VERSION 5.8 ;
BUSBITCHARS "[]" ;
DIVIDERCHAR "/" ;
UNITS
    DATABASE MICRONS 1000 ;
END UNITS

VIA ino_fetch_via1_2_1000_440_1_2_410_410
  VIARULE via1Array ;
  CUTSIZE 0.19 0.19 ;
  LAYERS Metal1 Via1 Metal2 ;
  CUTSPACING 0.22 0.22 ;
  ENCLOSURE 0.05 0.125 0.005 0.05 ;
  ROWCOL 1 2 ;
END ino_fetch_via1_2_1000_440_1_2_410_410

VIA ino_fetch_via2_3_1000_440_1_2_410_410
  VIARULE via2Array ;
  CUTSIZE 0.19 0.19 ;
  LAYERS Metal2 Via2 Metal3 ;
  CUTSPACING 0.22 0.22 ;
  ENCLOSURE 0.005 0.05 0.05 0.005 ;
  ROWCOL 1 2 ;
END ino_fetch_via2_3_1000_440_1_2_410_410

VIA ino_fetch_via3_4_1000_440_1_2_410_410
  VIARULE via3Array ;
  CUTSIZE 0.19 0.19 ;
  LAYERS Metal3 Via3 Metal4 ;
  CUTSPACING 0.22 0.22 ;
  ENCLOSURE 0.05 0.005 0.2 0.05 ;
  ROWCOL 1 2 ;
END ino_fetch_via3_4_1000_440_1_2_410_410

VIA ino_fetch_via4_5_1000_2000_1_1_840_840
  VIARULE viaTop1Array ;
  CUTSIZE 0.42 0.42 ;
  LAYERS Metal4 TopVia1 TopMetal1 ;
  CUTSPACING 0.42 0.42 ;
  ENCLOSURE 0.29 0.1 0.42 0.79 ;
END ino_fetch_via4_5_1000_2000_1_1_840_840

VIA ino_fetch_via4_5_1000_1640_1_1_840_840
  VIARULE viaTop1Array ;
  CUTSIZE 0.42 0.42 ;
  LAYERS Metal4 TopVia1 TopMetal1 ;
  CUTSPACING 0.42 0.42 ;
  ENCLOSURE 0.29 0.1 0.42 0.61 ;
END ino_fetch_via4_5_1000_1640_1_1_840_840

VIA ino_fetch_via4_5_1000_1400_1_1_840_840
  VIARULE viaTop1Array ;
  CUTSIZE 0.42 0.42 ;
  LAYERS Metal4 TopVia1 TopMetal1 ;
  CUTSPACING 0.42 0.42 ;
  ENCLOSURE 0.29 0.1 0.42 0.49 ;
END ino_fetch_via4_5_1000_1400_1_1_840_840

VIA ino_fetch_via4_5_4420_2000_1_4_840_840
  VIARULE viaTop1Array ;
  CUTSIZE 0.42 0.42 ;
  LAYERS Metal4 TopVia1 TopMetal1 ;
  CUTSPACING 0.42 0.42 ;
  ENCLOSURE 0.74 0.79 0.42 0.79 ;
  ROWCOL 1 4 ;
END ino_fetch_via4_5_4420_2000_1_4_840_840

VIA ino_fetch_via4_5_2810_2000_1_2_840_840
  VIARULE viaTop1Array ;
  CUTSIZE 0.42 0.42 ;
  LAYERS Metal4 TopVia1 TopMetal1 ;
  CUTSPACING 0.42 0.42 ;
  ENCLOSURE 0.775 0.79 0.42 0.79 ;
  ROWCOL 1 2 ;
END ino_fetch_via4_5_2810_2000_1_2_840_840

VIA ino_fetch_via4_5_4420_1650_1_4_840_840
  VIARULE viaTop1Array ;
  CUTSIZE 0.42 0.42 ;
  LAYERS Metal4 TopVia1 TopMetal1 ;
  CUTSPACING 0.42 0.42 ;
  ENCLOSURE 0.74 0.615 0.42 0.615 ;
  ROWCOL 1 4 ;
END ino_fetch_via4_5_4420_1650_1_4_840_840

VIA ino_fetch_via4_5_2810_1650_1_2_840_840
  VIARULE viaTop1Array ;
  CUTSIZE 0.42 0.42 ;
  LAYERS Metal4 TopVia1 TopMetal1 ;
  CUTSPACING 0.42 0.42 ;
  ENCLOSURE 0.775 0.615 0.42 0.615 ;
  ROWCOL 1 2 ;
END ino_fetch_via4_5_2810_1650_1_2_840_840

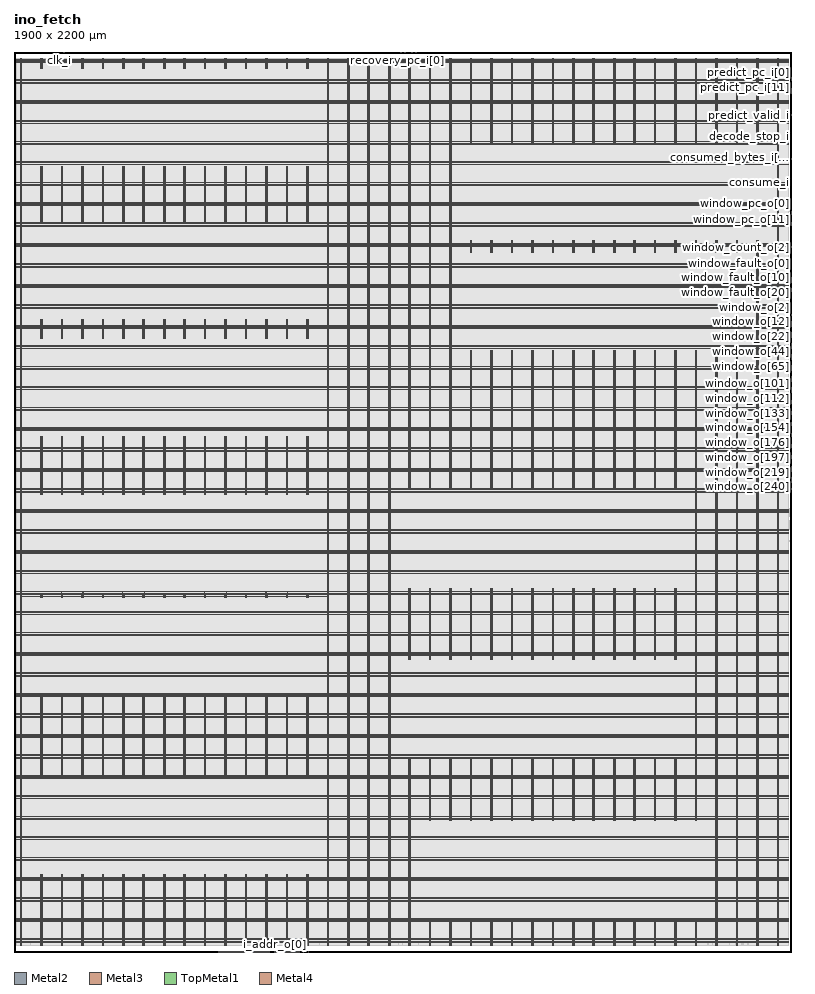
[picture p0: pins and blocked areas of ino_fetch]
MACRO ino_fetch
  FOREIGN ino_fetch 0 0 ;
  CLASS BLOCK ;
  SIZE 1900 BY 2200 ;
  PIN clk_i
    DIRECTION INPUT ;
    USE SIGNAL ;
    PORT
      LAYER Metal2 ;
        RECT  110.68 2199.6 111.08 2200 ;
    END
  END clk_i
  PIN consume_i
    DIRECTION INPUT ;
    USE SIGNAL ;
    PORT
      LAYER Metal3 ;
        RECT  1899.6 1880.98 1900 1881.38 ;
    END
  END consume_i
  PIN consumed_bytes_i[0]
    DIRECTION INPUT ;
    USE SIGNAL ;
    PORT
      LAYER Metal3 ;
        RECT  1899.6 1941.46 1900 1941.86 ;
    END
  END consumed_bytes_i[0]
  PIN consumed_bytes_i[1]
    DIRECTION INPUT ;
    USE SIGNAL ;
    PORT
      LAYER Metal3 ;
        RECT  1899.6 1939.78 1900 1940.18 ;
    END
  END consumed_bytes_i[1]
  PIN consumed_bytes_i[2]
    DIRECTION INPUT ;
    USE SIGNAL ;
    PORT
      LAYER Metal3 ;
        RECT  1899.6 1938.1 1900 1938.5 ;
    END
  END consumed_bytes_i[2]
  PIN consumed_bytes_i[3]
    DIRECTION INPUT ;
    USE SIGNAL ;
    PORT
      LAYER Metal3 ;
        RECT  1899.6 1936.42 1900 1936.82 ;
    END
  END consumed_bytes_i[3]
  PIN consumed_bytes_i[4]
    DIRECTION INPUT ;
    USE SIGNAL ;
    PORT
      LAYER Metal3 ;
        RECT  1899.6 1934.74 1900 1935.14 ;
    END
  END consumed_bytes_i[4]
  PIN consumed_bytes_i[5]
    DIRECTION INPUT ;
    USE SIGNAL ;
    PORT
      LAYER Metal3 ;
        RECT  1899.6 1933.06 1900 1933.46 ;
    END
  END consumed_bytes_i[5]
  PIN decode_stop_i
    DIRECTION INPUT ;
    USE SIGNAL ;
    PORT
      LAYER Metal3 ;
        RECT  1899.6 1993.54 1900 1993.94 ;
    END
  END decode_stop_i
  PIN halt_i
    DIRECTION INPUT ;
    USE SIGNAL ;
    PORT
      LAYER Metal2 ;
        RECT  122.2 2199.6 122.6 2200 ;
    END
  END halt_i
  PIN i_addr_o[0]
    DIRECTION OUTPUT ;
    USE SIGNAL ;
    PORT
      LAYER Metal2 ;
        RECT  636.76 0 637.16 0.4 ;
    END
  END i_addr_o[0]
  PIN i_addr_o[10]
    DIRECTION OUTPUT ;
    USE SIGNAL ;
    PORT
      LAYER Metal2 ;
        RECT  655.96 0 656.36 0.4 ;
    END
  END i_addr_o[10]
  PIN i_addr_o[11]
    DIRECTION OUTPUT ;
    USE SIGNAL ;
    PORT
      LAYER Metal2 ;
        RECT  657.88 0 658.28 0.4 ;
    END
  END i_addr_o[11]
  PIN i_addr_o[12]
    DIRECTION OUTPUT ;
    USE SIGNAL ;
    PORT
      LAYER Metal2 ;
        RECT  659.8 0 660.2 0.4 ;
    END
  END i_addr_o[12]
  PIN i_addr_o[13]
    DIRECTION OUTPUT ;
    USE SIGNAL ;
    PORT
      LAYER Metal2 ;
        RECT  661.72 0 662.12 0.4 ;
    END
  END i_addr_o[13]
  PIN i_addr_o[14]
    DIRECTION OUTPUT ;
    USE SIGNAL ;
    PORT
      LAYER Metal2 ;
        RECT  663.64 0 664.04 0.4 ;
    END
  END i_addr_o[14]
  PIN i_addr_o[15]
    DIRECTION OUTPUT ;
    USE SIGNAL ;
    PORT
      LAYER Metal2 ;
        RECT  665.56 0 665.96 0.4 ;
    END
  END i_addr_o[15]
  PIN i_addr_o[16]
    DIRECTION OUTPUT ;
    USE SIGNAL ;
    PORT
      LAYER Metal2 ;
        RECT  667.48 0 667.88 0.4 ;
    END
  END i_addr_o[16]
  PIN i_addr_o[17]
    DIRECTION OUTPUT ;
    USE SIGNAL ;
    PORT
      LAYER Metal2 ;
        RECT  669.4 0 669.8 0.4 ;
    END
  END i_addr_o[17]
  PIN i_addr_o[18]
    DIRECTION OUTPUT ;
    USE SIGNAL ;
    PORT
      LAYER Metal2 ;
        RECT  671.32 0 671.72 0.4 ;
    END
  END i_addr_o[18]
  PIN i_addr_o[19]
    DIRECTION OUTPUT ;
    USE SIGNAL ;
    PORT
      LAYER Metal2 ;
        RECT  673.24 0 673.64 0.4 ;
    END
  END i_addr_o[19]
  PIN i_addr_o[1]
    DIRECTION OUTPUT ;
    USE SIGNAL ;
    PORT
      LAYER Metal2 ;
        RECT  638.68 0 639.08 0.4 ;
    END
  END i_addr_o[1]
  PIN i_addr_o[20]
    DIRECTION OUTPUT ;
    USE SIGNAL ;
    PORT
      LAYER Metal2 ;
        RECT  675.16 0 675.56 0.4 ;
    END
  END i_addr_o[20]
  PIN i_addr_o[21]
    DIRECTION OUTPUT ;
    USE SIGNAL ;
    PORT
      LAYER Metal2 ;
        RECT  677.08 0 677.48 0.4 ;
    END
  END i_addr_o[21]
  PIN i_addr_o[22]
    DIRECTION OUTPUT ;
    USE SIGNAL ;
    PORT
      LAYER Metal2 ;
        RECT  679 0 679.4 0.4 ;
    END
  END i_addr_o[22]
  PIN i_addr_o[23]
    DIRECTION OUTPUT ;
    USE SIGNAL ;
    PORT
      LAYER Metal2 ;
        RECT  680.92 0 681.32 0.4 ;
    END
  END i_addr_o[23]
  PIN i_addr_o[24]
    DIRECTION OUTPUT ;
    USE SIGNAL ;
    PORT
      LAYER Metal2 ;
        RECT  682.84 0 683.24 0.4 ;
    END
  END i_addr_o[24]
  PIN i_addr_o[25]
    DIRECTION OUTPUT ;
    USE SIGNAL ;
    PORT
      LAYER Metal2 ;
        RECT  684.76 0 685.16 0.4 ;
    END
  END i_addr_o[25]
  PIN i_addr_o[26]
    DIRECTION OUTPUT ;
    USE SIGNAL ;
    PORT
      LAYER Metal2 ;
        RECT  686.68 0 687.08 0.4 ;
    END
  END i_addr_o[26]
  PIN i_addr_o[27]
    DIRECTION OUTPUT ;
    USE SIGNAL ;
    PORT
      LAYER Metal2 ;
        RECT  688.6 0 689 0.4 ;
    END
  END i_addr_o[27]
  PIN i_addr_o[28]
    DIRECTION OUTPUT ;
    USE SIGNAL ;
    PORT
      LAYER Metal2 ;
        RECT  690.52 0 690.92 0.4 ;
    END
  END i_addr_o[28]
  PIN i_addr_o[29]
    DIRECTION OUTPUT ;
    USE SIGNAL ;
    PORT
      LAYER Metal2 ;
        RECT  692.44 0 692.84 0.4 ;
    END
  END i_addr_o[29]
  PIN i_addr_o[2]
    DIRECTION OUTPUT ;
    USE SIGNAL ;
    PORT
      LAYER Metal2 ;
        RECT  640.6 0 641 0.4 ;
    END
  END i_addr_o[2]
  PIN i_addr_o[30]
    DIRECTION OUTPUT ;
    USE SIGNAL ;
    PORT
      LAYER Metal2 ;
        RECT  694.36 0 694.76 0.4 ;
    END
  END i_addr_o[30]
  PIN i_addr_o[31]
    DIRECTION OUTPUT ;
    USE SIGNAL ;
    PORT
      LAYER Metal2 ;
        RECT  696.28 0 696.68 0.4 ;
    END
  END i_addr_o[31]
  PIN i_addr_o[3]
    DIRECTION OUTPUT ;
    USE SIGNAL ;
    PORT
      LAYER Metal2 ;
        RECT  642.52 0 642.92 0.4 ;
    END
  END i_addr_o[3]
  PIN i_addr_o[4]
    DIRECTION OUTPUT ;
    USE SIGNAL ;
    PORT
      LAYER Metal2 ;
        RECT  644.44 0 644.84 0.4 ;
    END
  END i_addr_o[4]
  PIN i_addr_o[5]
    DIRECTION OUTPUT ;
    USE SIGNAL ;
    PORT
      LAYER Metal2 ;
        RECT  646.36 0 646.76 0.4 ;
    END
  END i_addr_o[5]
  PIN i_addr_o[6]
    DIRECTION OUTPUT ;
    USE SIGNAL ;
    PORT
      LAYER Metal2 ;
        RECT  648.28 0 648.68 0.4 ;
    END
  END i_addr_o[6]
  PIN i_addr_o[7]
    DIRECTION OUTPUT ;
    USE SIGNAL ;
    PORT
      LAYER Metal2 ;
        RECT  650.2 0 650.6 0.4 ;
    END
  END i_addr_o[7]
  PIN i_addr_o[8]
    DIRECTION OUTPUT ;
    USE SIGNAL ;
    PORT
      LAYER Metal2 ;
        RECT  652.12 0 652.52 0.4 ;
    END
  END i_addr_o[8]
  PIN i_addr_o[9]
    DIRECTION OUTPUT ;
    USE SIGNAL ;
    PORT
      LAYER Metal2 ;
        RECT  654.04 0 654.44 0.4 ;
    END
  END i_addr_o[9]
  PIN i_fault_i
    DIRECTION INPUT ;
    USE SIGNAL ;
    PORT
      LAYER Metal2 ;
        RECT  719.32 0 719.72 0.4 ;
    END
  END i_fault_i
  PIN i_rdata_i[0]
    DIRECTION INPUT ;
    USE SIGNAL ;
    PORT
      LAYER Metal2 ;
        RECT  500.44 0 500.84 0.4 ;
    END
  END i_rdata_i[0]
  PIN i_rdata_i[10]
    DIRECTION INPUT ;
    USE SIGNAL ;
    PORT
      LAYER Metal2 ;
        RECT  519.64 0 520.04 0.4 ;
    END
  END i_rdata_i[10]
  PIN i_rdata_i[11]
    DIRECTION INPUT ;
    USE SIGNAL ;
    PORT
      LAYER Metal2 ;
        RECT  521.56 0 521.96 0.4 ;
    END
  END i_rdata_i[11]
  PIN i_rdata_i[12]
    DIRECTION INPUT ;
    USE SIGNAL ;
    PORT
      LAYER Metal2 ;
        RECT  523.48 0 523.88 0.4 ;
    END
  END i_rdata_i[12]
  PIN i_rdata_i[13]
    DIRECTION INPUT ;
    USE SIGNAL ;
    PORT
      LAYER Metal2 ;
        RECT  525.4 0 525.8 0.4 ;
    END
  END i_rdata_i[13]
  PIN i_rdata_i[14]
    DIRECTION INPUT ;
    USE SIGNAL ;
    PORT
      LAYER Metal2 ;
        RECT  527.32 0 527.72 0.4 ;
    END
  END i_rdata_i[14]
  PIN i_rdata_i[15]
    DIRECTION INPUT ;
    USE SIGNAL ;
    PORT
      LAYER Metal2 ;
        RECT  529.24 0 529.64 0.4 ;
    END
  END i_rdata_i[15]
  PIN i_rdata_i[16]
    DIRECTION INPUT ;
    USE SIGNAL ;
    PORT
      LAYER Metal2 ;
        RECT  531.16 0 531.56 0.4 ;
    END
  END i_rdata_i[16]
  PIN i_rdata_i[17]
    DIRECTION INPUT ;
    USE SIGNAL ;
    PORT
      LAYER Metal2 ;
        RECT  533.08 0 533.48 0.4 ;
    END
  END i_rdata_i[17]
  PIN i_rdata_i[18]
    DIRECTION INPUT ;
    USE SIGNAL ;
    PORT
      LAYER Metal2 ;
        RECT  535 0 535.4 0.4 ;
    END
  END i_rdata_i[18]
  PIN i_rdata_i[19]
    DIRECTION INPUT ;
    USE SIGNAL ;
    PORT
      LAYER Metal2 ;
        RECT  536.92 0 537.32 0.4 ;
    END
  END i_rdata_i[19]
  PIN i_rdata_i[1]
    DIRECTION INPUT ;
    USE SIGNAL ;
    PORT
      LAYER Metal2 ;
        RECT  502.36 0 502.76 0.4 ;
    END
  END i_rdata_i[1]
  PIN i_rdata_i[20]
    DIRECTION INPUT ;
    USE SIGNAL ;
    PORT
      LAYER Metal2 ;
        RECT  538.84 0 539.24 0.4 ;
    END
  END i_rdata_i[20]
  PIN i_rdata_i[21]
    DIRECTION INPUT ;
    USE SIGNAL ;
    PORT
      LAYER Metal2 ;
        RECT  540.76 0 541.16 0.4 ;
    END
  END i_rdata_i[21]
  PIN i_rdata_i[22]
    DIRECTION INPUT ;
    USE SIGNAL ;
    PORT
      LAYER Metal2 ;
        RECT  542.68 0 543.08 0.4 ;
    END
  END i_rdata_i[22]
  PIN i_rdata_i[23]
    DIRECTION INPUT ;
    USE SIGNAL ;
    PORT
      LAYER Metal2 ;
        RECT  544.6 0 545 0.4 ;
    END
  END i_rdata_i[23]
  PIN i_rdata_i[24]
    DIRECTION INPUT ;
    USE SIGNAL ;
    PORT
      LAYER Metal2 ;
        RECT  546.52 0 546.92 0.4 ;
    END
  END i_rdata_i[24]
  PIN i_rdata_i[25]
    DIRECTION INPUT ;
    USE SIGNAL ;
    PORT
      LAYER Metal2 ;
        RECT  548.44 0 548.84 0.4 ;
    END
  END i_rdata_i[25]
  PIN i_rdata_i[26]
    DIRECTION INPUT ;
    USE SIGNAL ;
    PORT
      LAYER Metal2 ;
        RECT  550.36 0 550.76 0.4 ;
    END
  END i_rdata_i[26]
  PIN i_rdata_i[27]
    DIRECTION INPUT ;
    USE SIGNAL ;
    PORT
      LAYER Metal2 ;
        RECT  552.28 0 552.68 0.4 ;
    END
  END i_rdata_i[27]
  PIN i_rdata_i[28]
    DIRECTION INPUT ;
    USE SIGNAL ;
    PORT
      LAYER Metal2 ;
        RECT  554.2 0 554.6 0.4 ;
    END
  END i_rdata_i[28]
  PIN i_rdata_i[29]
    DIRECTION INPUT ;
    USE SIGNAL ;
    PORT
      LAYER Metal2 ;
        RECT  556.12 0 556.52 0.4 ;
    END
  END i_rdata_i[29]
  PIN i_rdata_i[2]
    DIRECTION INPUT ;
    USE SIGNAL ;
    PORT
      LAYER Metal2 ;
        RECT  504.28 0 504.68 0.4 ;
    END
  END i_rdata_i[2]
  PIN i_rdata_i[30]
    DIRECTION INPUT ;
    USE SIGNAL ;
    PORT
      LAYER Metal2 ;
        RECT  558.04 0 558.44 0.4 ;
    END
  END i_rdata_i[30]
  PIN i_rdata_i[31]
    DIRECTION INPUT ;
    USE SIGNAL ;
    PORT
      LAYER Metal2 ;
        RECT  559.96 0 560.36 0.4 ;
    END
  END i_rdata_i[31]
  PIN i_rdata_i[32]
    DIRECTION INPUT ;
    USE SIGNAL ;
    PORT
      LAYER Metal2 ;
        RECT  561.88 0 562.28 0.4 ;
    END
  END i_rdata_i[32]
  PIN i_rdata_i[33]
    DIRECTION INPUT ;
    USE SIGNAL ;
    PORT
      LAYER Metal2 ;
        RECT  563.8 0 564.2 0.4 ;
    END
  END i_rdata_i[33]
  PIN i_rdata_i[34]
    DIRECTION INPUT ;
    USE SIGNAL ;
    PORT
      LAYER Metal2 ;
        RECT  565.72 0 566.12 0.4 ;
    END
  END i_rdata_i[34]
  PIN i_rdata_i[35]
    DIRECTION INPUT ;
    USE SIGNAL ;
    PORT
      LAYER Metal2 ;
        RECT  567.64 0 568.04 0.4 ;
    END
  END i_rdata_i[35]
  PIN i_rdata_i[36]
    DIRECTION INPUT ;
    USE SIGNAL ;
    PORT
      LAYER Metal2 ;
        RECT  569.56 0 569.96 0.4 ;
    END
  END i_rdata_i[36]
  PIN i_rdata_i[37]
    DIRECTION INPUT ;
    USE SIGNAL ;
    PORT
      LAYER Metal2 ;
        RECT  571.48 0 571.88 0.4 ;
    END
  END i_rdata_i[37]
  PIN i_rdata_i[38]
    DIRECTION INPUT ;
    USE SIGNAL ;
    PORT
      LAYER Metal2 ;
        RECT  573.4 0 573.8 0.4 ;
    END
  END i_rdata_i[38]
  PIN i_rdata_i[39]
    DIRECTION INPUT ;
    USE SIGNAL ;
    PORT
      LAYER Metal2 ;
        RECT  575.32 0 575.72 0.4 ;
    END
  END i_rdata_i[39]
  PIN i_rdata_i[3]
    DIRECTION INPUT ;
    USE SIGNAL ;
    PORT
      LAYER Metal2 ;
        RECT  506.2 0 506.6 0.4 ;
    END
  END i_rdata_i[3]
  PIN i_rdata_i[40]
    DIRECTION INPUT ;
    USE SIGNAL ;
    PORT
      LAYER Metal2 ;
        RECT  577.24 0 577.64 0.4 ;
    END
  END i_rdata_i[40]
  PIN i_rdata_i[41]
    DIRECTION INPUT ;
    USE SIGNAL ;
    PORT
      LAYER Metal2 ;
        RECT  579.16 0 579.56 0.4 ;
    END
  END i_rdata_i[41]
  PIN i_rdata_i[42]
    DIRECTION INPUT ;
    USE SIGNAL ;
    PORT
      LAYER Metal2 ;
        RECT  581.08 0 581.48 0.4 ;
    END
  END i_rdata_i[42]
  PIN i_rdata_i[43]
    DIRECTION INPUT ;
    USE SIGNAL ;
    PORT
      LAYER Metal2 ;
        RECT  583 0 583.4 0.4 ;
    END
  END i_rdata_i[43]
  PIN i_rdata_i[44]
    DIRECTION INPUT ;
    USE SIGNAL ;
    PORT
      LAYER Metal2 ;
        RECT  584.92 0 585.32 0.4 ;
    END
  END i_rdata_i[44]
  PIN i_rdata_i[45]
    DIRECTION INPUT ;
    USE SIGNAL ;
    PORT
      LAYER Metal2 ;
        RECT  586.84 0 587.24 0.4 ;
    END
  END i_rdata_i[45]
  PIN i_rdata_i[46]
    DIRECTION INPUT ;
    USE SIGNAL ;
    PORT
      LAYER Metal2 ;
        RECT  588.76 0 589.16 0.4 ;
    END
  END i_rdata_i[46]
  PIN i_rdata_i[47]
    DIRECTION INPUT ;
    USE SIGNAL ;
    PORT
      LAYER Metal2 ;
        RECT  590.68 0 591.08 0.4 ;
    END
  END i_rdata_i[47]
  PIN i_rdata_i[48]
    DIRECTION INPUT ;
    USE SIGNAL ;
    PORT
      LAYER Metal2 ;
        RECT  592.6 0 593 0.4 ;
    END
  END i_rdata_i[48]
  PIN i_rdata_i[49]
    DIRECTION INPUT ;
    USE SIGNAL ;
    PORT
      LAYER Metal2 ;
        RECT  594.52 0 594.92 0.4 ;
    END
  END i_rdata_i[49]
  PIN i_rdata_i[4]
    DIRECTION INPUT ;
    USE SIGNAL ;
    PORT
      LAYER Metal2 ;
        RECT  508.12 0 508.52 0.4 ;
    END
  END i_rdata_i[4]
  PIN i_rdata_i[50]
    DIRECTION INPUT ;
    USE SIGNAL ;
    PORT
      LAYER Metal2 ;
        RECT  596.44 0 596.84 0.4 ;
    END
  END i_rdata_i[50]
  PIN i_rdata_i[51]
    DIRECTION INPUT ;
    USE SIGNAL ;
    PORT
      LAYER Metal2 ;
        RECT  598.36 0 598.76 0.4 ;
    END
  END i_rdata_i[51]
  PIN i_rdata_i[52]
    DIRECTION INPUT ;
    USE SIGNAL ;
    PORT
      LAYER Metal2 ;
        RECT  600.28 0 600.68 0.4 ;
    END
  END i_rdata_i[52]
  PIN i_rdata_i[53]
    DIRECTION INPUT ;
    USE SIGNAL ;
    PORT
      LAYER Metal2 ;
        RECT  602.2 0 602.6 0.4 ;
    END
  END i_rdata_i[53]
  PIN i_rdata_i[54]
    DIRECTION INPUT ;
    USE SIGNAL ;
    PORT
      LAYER Metal2 ;
        RECT  604.12 0 604.52 0.4 ;
    END
  END i_rdata_i[54]
  PIN i_rdata_i[55]
    DIRECTION INPUT ;
    USE SIGNAL ;
    PORT
      LAYER Metal2 ;
        RECT  606.04 0 606.44 0.4 ;
    END
  END i_rdata_i[55]
  PIN i_rdata_i[56]
    DIRECTION INPUT ;
    USE SIGNAL ;
    PORT
      LAYER Metal2 ;
        RECT  607.96 0 608.36 0.4 ;
    END
  END i_rdata_i[56]
  PIN i_rdata_i[57]
    DIRECTION INPUT ;
    USE SIGNAL ;
    PORT
      LAYER Metal2 ;
        RECT  609.88 0 610.28 0.4 ;
    END
  END i_rdata_i[57]
  PIN i_rdata_i[58]
    DIRECTION INPUT ;
    USE SIGNAL ;
    PORT
      LAYER Metal2 ;
        RECT  611.8 0 612.2 0.4 ;
    END
  END i_rdata_i[58]
  PIN i_rdata_i[59]
    DIRECTION INPUT ;
    USE SIGNAL ;
    PORT
      LAYER Metal2 ;
        RECT  613.72 0 614.12 0.4 ;
    END
  END i_rdata_i[59]
  PIN i_rdata_i[5]
    DIRECTION INPUT ;
    USE SIGNAL ;
    PORT
      LAYER Metal2 ;
        RECT  510.04 0 510.44 0.4 ;
    END
  END i_rdata_i[5]
  PIN i_rdata_i[60]
    DIRECTION INPUT ;
    USE SIGNAL ;
    PORT
      LAYER Metal2 ;
        RECT  615.64 0 616.04 0.4 ;
    END
  END i_rdata_i[60]
  PIN i_rdata_i[61]
    DIRECTION INPUT ;
    USE SIGNAL ;
    PORT
      LAYER Metal2 ;
        RECT  617.56 0 617.96 0.4 ;
    END
  END i_rdata_i[61]
  PIN i_rdata_i[62]
    DIRECTION INPUT ;
    USE SIGNAL ;
    PORT
      LAYER Metal2 ;
        RECT  619.48 0 619.88 0.4 ;
    END
  END i_rdata_i[62]
  PIN i_rdata_i[63]
    DIRECTION INPUT ;
    USE SIGNAL ;
    PORT
      LAYER Metal2 ;
        RECT  621.4 0 621.8 0.4 ;
    END
  END i_rdata_i[63]
  PIN i_rdata_i[6]
    DIRECTION INPUT ;
    USE SIGNAL ;
    PORT
      LAYER Metal2 ;
        RECT  511.96 0 512.36 0.4 ;
    END
  END i_rdata_i[6]
  PIN i_rdata_i[7]
    DIRECTION INPUT ;
    USE SIGNAL ;
    PORT
      LAYER Metal2 ;
        RECT  513.88 0 514.28 0.4 ;
    END
  END i_rdata_i[7]
  PIN i_rdata_i[8]
    DIRECTION INPUT ;
    USE SIGNAL ;
    PORT
      LAYER Metal2 ;
        RECT  515.8 0 516.2 0.4 ;
    END
  END i_rdata_i[8]
  PIN i_rdata_i[9]
    DIRECTION INPUT ;
    USE SIGNAL ;
    PORT
      LAYER Metal2 ;
        RECT  517.72 0 518.12 0.4 ;
    END
  END i_rdata_i[9]
  PIN i_ready_i
    DIRECTION INPUT ;
    USE SIGNAL ;
    PORT
      LAYER Metal2 ;
        RECT  625.24 0 625.64 0.4 ;
    END
  END i_ready_i
  PIN i_req_o
    DIRECTION OUTPUT ;
    USE SIGNAL ;
    PORT
      LAYER Metal2 ;
        RECT  707.8 0 708.2 0.4 ;
    END
  END i_req_o
  PIN i_rvalid_i
    DIRECTION INPUT ;
    USE SIGNAL ;
    PORT
      LAYER Metal2 ;
        RECT  623.32 0 623.72 0.4 ;
    END
  END i_rvalid_i
  PIN icache_invalidate_i
    DIRECTION INPUT ;
    USE SIGNAL ;
    PORT
      LAYER Metal2 ;
        RECT  133.72 2199.6 134.12 2200 ;
    END
  END icache_invalidate_i
  PIN predict_pc_i[0]
    DIRECTION INPUT ;
    USE SIGNAL ;
    PORT
      LAYER Metal3 ;
        RECT  1899.6 2149.78 1900 2150.18 ;
    END
  END predict_pc_i[0]
  PIN predict_pc_i[10]
    DIRECTION INPUT ;
    USE SIGNAL ;
    PORT
      LAYER Metal3 ;
        RECT  1899.6 2132.98 1900 2133.38 ;
    END
  END predict_pc_i[10]
  PIN predict_pc_i[11]
    DIRECTION INPUT ;
    USE SIGNAL ;
    PORT
      LAYER Metal3 ;
        RECT  1899.6 2131.3 1900 2131.7 ;
    END
  END predict_pc_i[11]
  PIN predict_pc_i[12]
    DIRECTION INPUT ;
    USE SIGNAL ;
    PORT
      LAYER Metal3 ;
        RECT  1899.6 2129.62 1900 2130.02 ;
    END
  END predict_pc_i[12]
  PIN predict_pc_i[13]
    DIRECTION INPUT ;
    USE SIGNAL ;
    PORT
      LAYER Metal3 ;
        RECT  1899.6 2127.94 1900 2128.34 ;
    END
  END predict_pc_i[13]
  PIN predict_pc_i[14]
    DIRECTION INPUT ;
    USE SIGNAL ;
    PORT
      LAYER Metal3 ;
        RECT  1899.6 2126.26 1900 2126.66 ;
    END
  END predict_pc_i[14]
  PIN predict_pc_i[15]
    DIRECTION INPUT ;
    USE SIGNAL ;
    PORT
      LAYER Metal3 ;
        RECT  1899.6 2124.58 1900 2124.98 ;
    END
  END predict_pc_i[15]
  PIN predict_pc_i[16]
    DIRECTION INPUT ;
    USE SIGNAL ;
    PORT
      LAYER Metal3 ;
        RECT  1899.6 2122.9 1900 2123.3 ;
    END
  END predict_pc_i[16]
  PIN predict_pc_i[17]
    DIRECTION INPUT ;
    USE SIGNAL ;
    PORT
      LAYER Metal3 ;
        RECT  1899.6 2121.22 1900 2121.62 ;
    END
  END predict_pc_i[17]
  PIN predict_pc_i[18]
    DIRECTION INPUT ;
    USE SIGNAL ;
    PORT
      LAYER Metal3 ;
        RECT  1899.6 2119.54 1900 2119.94 ;
    END
  END predict_pc_i[18]
  PIN predict_pc_i[19]
    DIRECTION INPUT ;
    USE SIGNAL ;
    PORT
      LAYER Metal3 ;
        RECT  1899.6 2117.86 1900 2118.26 ;
    END
  END predict_pc_i[19]
  PIN predict_pc_i[1]
    DIRECTION INPUT ;
    USE SIGNAL ;
    PORT
      LAYER Metal3 ;
        RECT  1899.6 2148.1 1900 2148.5 ;
    END
  END predict_pc_i[1]
  PIN predict_pc_i[20]
    DIRECTION INPUT ;
    USE SIGNAL ;
    PORT
      LAYER Metal3 ;
        RECT  1899.6 2116.18 1900 2116.58 ;
    END
  END predict_pc_i[20]
  PIN predict_pc_i[21]
    DIRECTION INPUT ;
    USE SIGNAL ;
    PORT
      LAYER Metal3 ;
        RECT  1899.6 2114.5 1900 2114.9 ;
    END
  END predict_pc_i[21]
  PIN predict_pc_i[22]
    DIRECTION INPUT ;
    USE SIGNAL ;
    PORT
      LAYER Metal3 ;
        RECT  1899.6 2112.82 1900 2113.22 ;
    END
  END predict_pc_i[22]
  PIN predict_pc_i[23]
    DIRECTION INPUT ;
    USE SIGNAL ;
    PORT
      LAYER Metal3 ;
        RECT  1899.6 2111.14 1900 2111.54 ;
    END
  END predict_pc_i[23]
  PIN predict_pc_i[24]
    DIRECTION INPUT ;
    USE SIGNAL ;
    PORT
      LAYER Metal3 ;
        RECT  1899.6 2109.46 1900 2109.86 ;
    END
  END predict_pc_i[24]
  PIN predict_pc_i[25]
    DIRECTION INPUT ;
    USE SIGNAL ;
    PORT
      LAYER Metal3 ;
        RECT  1899.6 2107.78 1900 2108.18 ;
    END
  END predict_pc_i[25]
  PIN predict_pc_i[26]
    DIRECTION INPUT ;
    USE SIGNAL ;
    PORT
      LAYER Metal3 ;
        RECT  1899.6 2106.1 1900 2106.5 ;
    END
  END predict_pc_i[26]
  PIN predict_pc_i[27]
    DIRECTION INPUT ;
    USE SIGNAL ;
    PORT
      LAYER Metal3 ;
        RECT  1899.6 2104.42 1900 2104.82 ;
    END
  END predict_pc_i[27]
  PIN predict_pc_i[28]
    DIRECTION INPUT ;
    USE SIGNAL ;
    PORT
      LAYER Metal3 ;
        RECT  1899.6 2102.74 1900 2103.14 ;
    END
  END predict_pc_i[28]
  PIN predict_pc_i[29]
    DIRECTION INPUT ;
    USE SIGNAL ;
    PORT
      LAYER Metal3 ;
        RECT  1899.6 2101.06 1900 2101.46 ;
    END
  END predict_pc_i[29]
  PIN predict_pc_i[2]
    DIRECTION INPUT ;
    USE SIGNAL ;
    PORT
      LAYER Metal3 ;
        RECT  1899.6 2146.42 1900 2146.82 ;
    END
  END predict_pc_i[2]
  PIN predict_pc_i[30]
    DIRECTION INPUT ;
    USE SIGNAL ;
    PORT
      LAYER Metal3 ;
        RECT  1899.6 2099.38 1900 2099.78 ;
    END
  END predict_pc_i[30]
  PIN predict_pc_i[31]
    DIRECTION INPUT ;
    USE SIGNAL ;
    PORT
      LAYER Metal3 ;
        RECT  1899.6 2097.7 1900 2098.1 ;
    END
  END predict_pc_i[31]
  PIN predict_pc_i[3]
    DIRECTION INPUT ;
    USE SIGNAL ;
    PORT
      LAYER Metal3 ;
        RECT  1899.6 2144.74 1900 2145.14 ;
    END
  END predict_pc_i[3]
  PIN predict_pc_i[4]
    DIRECTION INPUT ;
    USE SIGNAL ;
    PORT
      LAYER Metal3 ;
        RECT  1899.6 2143.06 1900 2143.46 ;
    END
  END predict_pc_i[4]
  PIN predict_pc_i[5]
    DIRECTION INPUT ;
    USE SIGNAL ;
    PORT
      LAYER Metal3 ;
        RECT  1899.6 2141.38 1900 2141.78 ;
    END
  END predict_pc_i[5]
  PIN predict_pc_i[6]
    DIRECTION INPUT ;
    USE SIGNAL ;
    PORT
      LAYER Metal3 ;
        RECT  1899.6 2139.7 1900 2140.1 ;
    END
  END predict_pc_i[6]
  PIN predict_pc_i[7]
    DIRECTION INPUT ;
    USE SIGNAL ;
    PORT
      LAYER Metal3 ;
        RECT  1899.6 2138.02 1900 2138.42 ;
    END
  END predict_pc_i[7]
  PIN predict_pc_i[8]
    DIRECTION INPUT ;
    USE SIGNAL ;
    PORT
      LAYER Metal3 ;
        RECT  1899.6 2136.34 1900 2136.74 ;
    END
  END predict_pc_i[8]
  PIN predict_pc_i[9]
    DIRECTION INPUT ;
    USE SIGNAL ;
    PORT
      LAYER Metal3 ;
        RECT  1899.6 2134.66 1900 2135.06 ;
    END
  END predict_pc_i[9]
  PIN predict_valid_i
    DIRECTION INPUT ;
    USE SIGNAL ;
    PORT
      LAYER Metal3 ;
        RECT  1899.6 2045.62 1900 2046.02 ;
    END
  END predict_valid_i
  PIN recovery_pc_i[0]
    DIRECTION INPUT ;
    USE SIGNAL ;
    PORT
      LAYER Metal2 ;
        RECT  938.2 2199.6 938.6 2200 ;
    END
  END recovery_pc_i[0]
  PIN recovery_pc_i[10]
    DIRECTION INPUT ;
    USE SIGNAL ;
    PORT
      LAYER Metal2 ;
        RECT  957.4 2199.6 957.8 2200 ;
    END
  END recovery_pc_i[10]
  PIN recovery_pc_i[11]
    DIRECTION INPUT ;
    USE SIGNAL ;
    PORT
      LAYER Metal2 ;
        RECT  959.32 2199.6 959.72 2200 ;
    END
  END recovery_pc_i[11]
  PIN recovery_pc_i[12]
    DIRECTION INPUT ;
    USE SIGNAL ;
    PORT
      LAYER Metal2 ;
        RECT  961.24 2199.6 961.64 2200 ;
    END
  END recovery_pc_i[12]
  PIN recovery_pc_i[13]
    DIRECTION INPUT ;
    USE SIGNAL ;
    PORT
      LAYER Metal2 ;
        RECT  963.16 2199.6 963.56 2200 ;
    END
  END recovery_pc_i[13]
  PIN recovery_pc_i[14]
    DIRECTION INPUT ;
    USE SIGNAL ;
    PORT
      LAYER Metal2 ;
        RECT  965.08 2199.6 965.48 2200 ;
    END
  END recovery_pc_i[14]
  PIN recovery_pc_i[15]
    DIRECTION INPUT ;
    USE SIGNAL ;
    PORT
      LAYER Metal2 ;
        RECT  967 2199.6 967.4 2200 ;
    END
  END recovery_pc_i[15]
  PIN recovery_pc_i[16]
    DIRECTION INPUT ;
    USE SIGNAL ;
    PORT
      LAYER Metal2 ;
        RECT  968.92 2199.6 969.32 2200 ;
    END
  END recovery_pc_i[16]
  PIN recovery_pc_i[17]
    DIRECTION INPUT ;
    USE SIGNAL ;
    PORT
      LAYER Metal2 ;
        RECT  970.84 2199.6 971.24 2200 ;
    END
  END recovery_pc_i[17]
  PIN recovery_pc_i[18]
    DIRECTION INPUT ;
    USE SIGNAL ;
    PORT
      LAYER Metal2 ;
        RECT  972.76 2199.6 973.16 2200 ;
    END
  END recovery_pc_i[18]
  PIN recovery_pc_i[19]
    DIRECTION INPUT ;
    USE SIGNAL ;
    PORT
      LAYER Metal2 ;
        RECT  974.68 2199.6 975.08 2200 ;
    END
  END recovery_pc_i[19]
  PIN recovery_pc_i[1]
    DIRECTION INPUT ;
    USE SIGNAL ;
    PORT
      LAYER Metal2 ;
        RECT  940.12 2199.6 940.52 2200 ;
    END
  END recovery_pc_i[1]
  PIN recovery_pc_i[20]
    DIRECTION INPUT ;
    USE SIGNAL ;
    PORT
      LAYER Metal2 ;
        RECT  976.6 2199.6 977 2200 ;
    END
  END recovery_pc_i[20]
  PIN recovery_pc_i[21]
    DIRECTION INPUT ;
    USE SIGNAL ;
    PORT
      LAYER Metal2 ;
        RECT  978.52 2199.6 978.92 2200 ;
    END
  END recovery_pc_i[21]
  PIN recovery_pc_i[22]
    DIRECTION INPUT ;
    USE SIGNAL ;
    PORT
      LAYER Metal2 ;
        RECT  980.44 2199.6 980.84 2200 ;
    END
  END recovery_pc_i[22]
  PIN recovery_pc_i[23]
    DIRECTION INPUT ;
    USE SIGNAL ;
    PORT
      LAYER Metal2 ;
        RECT  982.36 2199.6 982.76 2200 ;
    END
  END recovery_pc_i[23]
  PIN recovery_pc_i[24]
    DIRECTION INPUT ;
    USE SIGNAL ;
    PORT
      LAYER Metal2 ;
        RECT  984.28 2199.6 984.68 2200 ;
    END
  END recovery_pc_i[24]
  PIN recovery_pc_i[25]
    DIRECTION INPUT ;
    USE SIGNAL ;
    PORT
      LAYER Metal2 ;
        RECT  986.2 2199.6 986.6 2200 ;
    END
  END recovery_pc_i[25]
  PIN recovery_pc_i[26]
    DIRECTION INPUT ;
    USE SIGNAL ;
    PORT
      LAYER Metal2 ;
        RECT  988.12 2199.6 988.52 2200 ;
    END
  END recovery_pc_i[26]
  PIN recovery_pc_i[27]
    DIRECTION INPUT ;
    USE SIGNAL ;
    PORT
      LAYER Metal2 ;
        RECT  990.04 2199.6 990.44 2200 ;
    END
  END recovery_pc_i[27]
  PIN recovery_pc_i[28]
    DIRECTION INPUT ;
    USE SIGNAL ;
    PORT
      LAYER Metal2 ;
        RECT  991.96 2199.6 992.36 2200 ;
    END
  END recovery_pc_i[28]
  PIN recovery_pc_i[29]
    DIRECTION INPUT ;
    USE SIGNAL ;
    PORT
      LAYER Metal2 ;
        RECT  993.88 2199.6 994.28 2200 ;
    END
  END recovery_pc_i[29]
  PIN recovery_pc_i[2]
    DIRECTION INPUT ;
    USE SIGNAL ;
    PORT
      LAYER Metal2 ;
        RECT  942.04 2199.6 942.44 2200 ;
    END
  END recovery_pc_i[2]
  PIN recovery_pc_i[30]
    DIRECTION INPUT ;
    USE SIGNAL ;
    PORT
      LAYER Metal2 ;
        RECT  995.8 2199.6 996.2 2200 ;
    END
  END recovery_pc_i[30]
  PIN recovery_pc_i[31]
    DIRECTION INPUT ;
    USE SIGNAL ;
    PORT
      LAYER Metal2 ;
        RECT  997.72 2199.6 998.12 2200 ;
    END
  END recovery_pc_i[31]
  PIN recovery_pc_i[3]
    DIRECTION INPUT ;
    USE SIGNAL ;
    PORT
      LAYER Metal2 ;
        RECT  943.96 2199.6 944.36 2200 ;
    END
  END recovery_pc_i[3]
  PIN recovery_pc_i[4]
    DIRECTION INPUT ;
    USE SIGNAL ;
    PORT
      LAYER Metal2 ;
        RECT  945.88 2199.6 946.28 2200 ;
    END
  END recovery_pc_i[4]
  PIN recovery_pc_i[5]
    DIRECTION INPUT ;
    USE SIGNAL ;
    PORT
      LAYER Metal2 ;
        RECT  947.8 2199.6 948.2 2200 ;
    END
  END recovery_pc_i[5]
  PIN recovery_pc_i[6]
    DIRECTION INPUT ;
    USE SIGNAL ;
    PORT
      LAYER Metal2 ;
        RECT  949.72 2199.6 950.12 2200 ;
    END
  END recovery_pc_i[6]
  PIN recovery_pc_i[7]
    DIRECTION INPUT ;
    USE SIGNAL ;
    PORT
      LAYER Metal2 ;
        RECT  951.64 2199.6 952.04 2200 ;
    END
  END recovery_pc_i[7]
  PIN recovery_pc_i[8]
    DIRECTION INPUT ;
    USE SIGNAL ;
    PORT
      LAYER Metal2 ;
        RECT  953.56 2199.6 953.96 2200 ;
    END
  END recovery_pc_i[8]
  PIN recovery_pc_i[9]
    DIRECTION INPUT ;
    USE SIGNAL ;
    PORT
      LAYER Metal2 ;
        RECT  955.48 2199.6 955.88 2200 ;
    END
  END recovery_pc_i[9]
  PIN recovery_valid_i
    DIRECTION INPUT ;
    USE SIGNAL ;
    PORT
      LAYER Metal2 ;
        RECT  936.28 2199.6 936.68 2200 ;
    END
  END recovery_valid_i
  PIN reset_i
    DIRECTION INPUT ;
    USE SIGNAL ;
    PORT
      LAYER Metal2 ;
        RECT  99.16 2199.6 99.56 2200 ;
    END
  END reset_i
  PIN window_count_o[0]
    DIRECTION OUTPUT ;
    USE SIGNAL ;
    PORT
      LAYER Metal3 ;
        RECT  1899.6 1724.74 1900 1725.14 ;
    END
  END window_count_o[0]
  PIN window_count_o[1]
    DIRECTION OUTPUT ;
    USE SIGNAL ;
    PORT
      LAYER Metal3 ;
        RECT  1899.6 1723.06 1900 1723.46 ;
    END
  END window_count_o[1]
  PIN window_count_o[2]
    DIRECTION OUTPUT ;
    USE SIGNAL ;
    PORT
      LAYER Metal3 ;
        RECT  1899.6 1721.38 1900 1721.78 ;
    END
  END window_count_o[2]
  PIN window_count_o[3]
    DIRECTION OUTPUT ;
    USE SIGNAL ;
    PORT
      LAYER Metal3 ;
        RECT  1899.6 1719.7 1900 1720.1 ;
    END
  END window_count_o[3]
  PIN window_count_o[4]
    DIRECTION OUTPUT ;
    USE SIGNAL ;
    PORT
      LAYER Metal3 ;
        RECT  1899.6 1718.02 1900 1718.42 ;
    END
  END window_count_o[4]
  PIN window_count_o[5]
    DIRECTION OUTPUT ;
    USE SIGNAL ;
    PORT
      LAYER Metal3 ;
        RECT  1899.6 1716.34 1900 1716.74 ;
    END
  END window_count_o[5]
  PIN window_fault_o[0]
    DIRECTION OUTPUT ;
    USE SIGNAL ;
    PORT
      LAYER Metal3 ;
        RECT  1899.6 1664.26 1900 1664.66 ;
    END
  END window_fault_o[0]
  PIN window_fault_o[10]
    DIRECTION OUTPUT ;
    USE SIGNAL ;
    PORT
      LAYER Metal3 ;
        RECT  1899.6 1647.46 1900 1647.86 ;
    END
  END window_fault_o[10]
  PIN window_fault_o[11]
    DIRECTION OUTPUT ;
    USE SIGNAL ;
    PORT
      LAYER Metal3 ;
        RECT  1899.6 1645.78 1900 1646.18 ;
    END
  END window_fault_o[11]
  PIN window_fault_o[12]
    DIRECTION OUTPUT ;
    USE SIGNAL ;
    PORT
      LAYER Metal3 ;
        RECT  1899.6 1644.1 1900 1644.5 ;
    END
  END window_fault_o[12]
  PIN window_fault_o[13]
    DIRECTION OUTPUT ;
    USE SIGNAL ;
    PORT
      LAYER Metal3 ;
        RECT  1899.6 1642.42 1900 1642.82 ;
    END
  END window_fault_o[13]
  PIN window_fault_o[14]
    DIRECTION OUTPUT ;
    USE SIGNAL ;
    PORT
      LAYER Metal3 ;
        RECT  1899.6 1640.74 1900 1641.14 ;
    END
  END window_fault_o[14]
  PIN window_fault_o[15]
    DIRECTION OUTPUT ;
    USE SIGNAL ;
    PORT
      LAYER Metal3 ;
        RECT  1899.6 1639.06 1900 1639.46 ;
    END
  END window_fault_o[15]
  PIN window_fault_o[16]
    DIRECTION OUTPUT ;
    USE SIGNAL ;
    PORT
      LAYER Metal3 ;
        RECT  1899.6 1637.38 1900 1637.78 ;
    END
  END window_fault_o[16]
  PIN window_fault_o[17]
    DIRECTION OUTPUT ;
    USE SIGNAL ;
    PORT
      LAYER Metal3 ;
        RECT  1899.6 1635.7 1900 1636.1 ;
    END
  END window_fault_o[17]
  PIN window_fault_o[18]
    DIRECTION OUTPUT ;
    USE SIGNAL ;
    PORT
      LAYER Metal3 ;
        RECT  1899.6 1634.02 1900 1634.42 ;
    END
  END window_fault_o[18]
  PIN window_fault_o[19]
    DIRECTION OUTPUT ;
    USE SIGNAL ;
    PORT
      LAYER Metal3 ;
        RECT  1899.6 1632.34 1900 1632.74 ;
    END
  END window_fault_o[19]
  PIN window_fault_o[1]
    DIRECTION OUTPUT ;
    USE SIGNAL ;
    PORT
      LAYER Metal3 ;
        RECT  1899.6 1662.58 1900 1662.98 ;
    END
  END window_fault_o[1]
  PIN window_fault_o[20]
    DIRECTION OUTPUT ;
    USE SIGNAL ;
    PORT
      LAYER Metal3 ;
        RECT  1899.6 1630.66 1900 1631.06 ;
    END
  END window_fault_o[20]
  PIN window_fault_o[21]
    DIRECTION OUTPUT ;
    USE SIGNAL ;
    PORT
      LAYER Metal3 ;
        RECT  1899.6 1628.98 1900 1629.38 ;
    END
  END window_fault_o[21]
  PIN window_fault_o[22]
    DIRECTION OUTPUT ;
    USE SIGNAL ;
    PORT
      LAYER Metal3 ;
        RECT  1899.6 1627.3 1900 1627.7 ;
    END
  END window_fault_o[22]
  PIN window_fault_o[23]
    DIRECTION OUTPUT ;
    USE SIGNAL ;
    PORT
      LAYER Metal3 ;
        RECT  1899.6 1625.62 1900 1626.02 ;
    END
  END window_fault_o[23]
  PIN window_fault_o[24]
    DIRECTION OUTPUT ;
    USE SIGNAL ;
    PORT
      LAYER Metal3 ;
        RECT  1899.6 1623.94 1900 1624.34 ;
    END
  END window_fault_o[24]
  PIN window_fault_o[25]
    DIRECTION OUTPUT ;
    USE SIGNAL ;
    PORT
      LAYER Metal3 ;
        RECT  1899.6 1622.26 1900 1622.66 ;
    END
  END window_fault_o[25]
  PIN window_fault_o[26]
    DIRECTION OUTPUT ;
    USE SIGNAL ;
    PORT
      LAYER Metal3 ;
        RECT  1899.6 1620.58 1900 1620.98 ;
    END
  END window_fault_o[26]
  PIN window_fault_o[27]
    DIRECTION OUTPUT ;
    USE SIGNAL ;
    PORT
      LAYER Metal3 ;
        RECT  1899.6 1618.9 1900 1619.3 ;
    END
  END window_fault_o[27]
  PIN window_fault_o[28]
    DIRECTION OUTPUT ;
    USE SIGNAL ;
    PORT
      LAYER Metal3 ;
        RECT  1899.6 1617.22 1900 1617.62 ;
    END
  END window_fault_o[28]
  PIN window_fault_o[29]
    DIRECTION OUTPUT ;
    USE SIGNAL ;
    PORT
      LAYER Metal3 ;
        RECT  1899.6 1615.54 1900 1615.94 ;
    END
  END window_fault_o[29]
  PIN window_fault_o[2]
    DIRECTION OUTPUT ;
    USE SIGNAL ;
    PORT
      LAYER Metal3 ;
        RECT  1899.6 1660.9 1900 1661.3 ;
    END
  END window_fault_o[2]
  PIN window_fault_o[30]
    DIRECTION OUTPUT ;
    USE SIGNAL ;
    PORT
      LAYER Metal3 ;
        RECT  1899.6 1613.86 1900 1614.26 ;
    END
  END window_fault_o[30]
  PIN window_fault_o[31]
    DIRECTION OUTPUT ;
    USE SIGNAL ;
    PORT
      LAYER Metal3 ;
        RECT  1899.6 1612.18 1900 1612.58 ;
    END
  END window_fault_o[31]
  PIN window_fault_o[3]
    DIRECTION OUTPUT ;
    USE SIGNAL ;
    PORT
      LAYER Metal3 ;
        RECT  1899.6 1659.22 1900 1659.62 ;
    END
  END window_fault_o[3]
  PIN window_fault_o[4]
    DIRECTION OUTPUT ;
    USE SIGNAL ;
    PORT
      LAYER Metal3 ;
        RECT  1899.6 1657.54 1900 1657.94 ;
    END
  END window_fault_o[4]
  PIN window_fault_o[5]
    DIRECTION OUTPUT ;
    USE SIGNAL ;
    PORT
      LAYER Metal3 ;
        RECT  1899.6 1655.86 1900 1656.26 ;
    END
  END window_fault_o[5]
  PIN window_fault_o[6]
    DIRECTION OUTPUT ;
    USE SIGNAL ;
    PORT
      LAYER Metal3 ;
        RECT  1899.6 1654.18 1900 1654.58 ;
    END
  END window_fault_o[6]
  PIN window_fault_o[7]
    DIRECTION OUTPUT ;
    USE SIGNAL ;
    PORT
      LAYER Metal3 ;
        RECT  1899.6 1652.5 1900 1652.9 ;
    END
  END window_fault_o[7]
  PIN window_fault_o[8]
    DIRECTION OUTPUT ;
    USE SIGNAL ;
    PORT
      LAYER Metal3 ;
        RECT  1899.6 1650.82 1900 1651.22 ;
    END
  END window_fault_o[8]
  PIN window_fault_o[9]
    DIRECTION OUTPUT ;
    USE SIGNAL ;
    PORT
      LAYER Metal3 ;
        RECT  1899.6 1649.14 1900 1649.54 ;
    END
  END window_fault_o[9]
  PIN window_o[0]
    DIRECTION OUTPUT ;
    USE SIGNAL ;
    PORT
      LAYER Metal3 ;
        RECT  1899.6 1560.1 1900 1560.5 ;
    END
  END window_o[0]
  PIN window_o[100]
    DIRECTION OUTPUT ;
    USE SIGNAL ;
    PORT
      LAYER Metal3 ;
        RECT  1899.6 1392.1 1900 1392.5 ;
    END
  END window_o[100]
  PIN window_o[101]
    DIRECTION OUTPUT ;
    USE SIGNAL ;
    PORT
      LAYER Metal3 ;
        RECT  1899.6 1390.42 1900 1390.82 ;
    END
  END window_o[101]
  PIN window_o[102]
    DIRECTION OUTPUT ;
    USE SIGNAL ;
    PORT
      LAYER Metal3 ;
        RECT  1899.6 1388.74 1900 1389.14 ;
    END
  END window_o[102]
  PIN window_o[103]
    DIRECTION OUTPUT ;
    USE SIGNAL ;
    PORT
      LAYER Metal3 ;
        RECT  1899.6 1387.06 1900 1387.46 ;
    END
  END window_o[103]
  PIN window_o[104]
    DIRECTION OUTPUT ;
    USE SIGNAL ;
    PORT
      LAYER Metal3 ;
        RECT  1899.6 1385.38 1900 1385.78 ;
    END
  END window_o[104]
  PIN window_o[105]
    DIRECTION OUTPUT ;
    USE SIGNAL ;
    PORT
      LAYER Metal3 ;
        RECT  1899.6 1383.7 1900 1384.1 ;
    END
  END window_o[105]
  PIN window_o[106]
    DIRECTION OUTPUT ;
    USE SIGNAL ;
    PORT
      LAYER Metal3 ;
        RECT  1899.6 1382.02 1900 1382.42 ;
    END
  END window_o[106]
  PIN window_o[107]
    DIRECTION OUTPUT ;
    USE SIGNAL ;
    PORT
      LAYER Metal3 ;
        RECT  1899.6 1380.34 1900 1380.74 ;
    END
  END window_o[107]
  PIN window_o[108]
    DIRECTION OUTPUT ;
    USE SIGNAL ;
    PORT
      LAYER Metal3 ;
        RECT  1899.6 1378.66 1900 1379.06 ;
    END
  END window_o[108]
  PIN window_o[109]
    DIRECTION OUTPUT ;
    USE SIGNAL ;
    PORT
      LAYER Metal3 ;
        RECT  1899.6 1376.98 1900 1377.38 ;
    END
  END window_o[109]
  PIN window_o[10]
    DIRECTION OUTPUT ;
    USE SIGNAL ;
    PORT
      LAYER Metal3 ;
        RECT  1899.6 1543.3 1900 1543.7 ;
    END
  END window_o[10]
  PIN window_o[110]
    DIRECTION OUTPUT ;
    USE SIGNAL ;
    PORT
      LAYER Metal3 ;
        RECT  1899.6 1375.3 1900 1375.7 ;
    END
  END window_o[110]
  PIN window_o[111]
    DIRECTION OUTPUT ;
    USE SIGNAL ;
    PORT
      LAYER Metal3 ;
        RECT  1899.6 1373.62 1900 1374.02 ;
    END
  END window_o[111]
  PIN window_o[112]
    DIRECTION OUTPUT ;
    USE SIGNAL ;
    PORT
      LAYER Metal3 ;
        RECT  1899.6 1371.94 1900 1372.34 ;
    END
  END window_o[112]
  PIN window_o[113]
    DIRECTION OUTPUT ;
    USE SIGNAL ;
    PORT
      LAYER Metal3 ;
        RECT  1899.6 1370.26 1900 1370.66 ;
    END
  END window_o[113]
  PIN window_o[114]
    DIRECTION OUTPUT ;
    USE SIGNAL ;
    PORT
      LAYER Metal3 ;
        RECT  1899.6 1368.58 1900 1368.98 ;
    END
  END window_o[114]
  PIN window_o[115]
    DIRECTION OUTPUT ;
    USE SIGNAL ;
    PORT
      LAYER Metal3 ;
        RECT  1899.6 1366.9 1900 1367.3 ;
    END
  END window_o[115]
  PIN window_o[116]
    DIRECTION OUTPUT ;
    USE SIGNAL ;
    PORT
      LAYER Metal3 ;
        RECT  1899.6 1365.22 1900 1365.62 ;
    END
  END window_o[116]
  PIN window_o[117]
    DIRECTION OUTPUT ;
    USE SIGNAL ;
    PORT
      LAYER Metal3 ;
        RECT  1899.6 1363.54 1900 1363.94 ;
    END
  END window_o[117]
  PIN window_o[118]
    DIRECTION OUTPUT ;
    USE SIGNAL ;
    PORT
      LAYER Metal3 ;
        RECT  1899.6 1361.86 1900 1362.26 ;
    END
  END window_o[118]
  PIN window_o[119]
    DIRECTION OUTPUT ;
    USE SIGNAL ;
    PORT
      LAYER Metal3 ;
        RECT  1899.6 1360.18 1900 1360.58 ;
    END
  END window_o[119]
  PIN window_o[11]
    DIRECTION OUTPUT ;
    USE SIGNAL ;
    PORT
      LAYER Metal3 ;
        RECT  1899.6 1541.62 1900 1542.02 ;
    END
  END window_o[11]
  PIN window_o[120]
    DIRECTION OUTPUT ;
    USE SIGNAL ;
    PORT
      LAYER Metal3 ;
        RECT  1899.6 1358.5 1900 1358.9 ;
    END
  END window_o[120]
  PIN window_o[121]
    DIRECTION OUTPUT ;
    USE SIGNAL ;
    PORT
      LAYER Metal3 ;
        RECT  1899.6 1356.82 1900 1357.22 ;
    END
  END window_o[121]
  PIN window_o[122]
    DIRECTION OUTPUT ;
    USE SIGNAL ;
    PORT
      LAYER Metal3 ;
        RECT  1899.6 1355.14 1900 1355.54 ;
    END
  END window_o[122]
  PIN window_o[123]
    DIRECTION OUTPUT ;
    USE SIGNAL ;
    PORT
      LAYER Metal3 ;
        RECT  1899.6 1353.46 1900 1353.86 ;
    END
  END window_o[123]
  PIN window_o[124]
    DIRECTION OUTPUT ;
    USE SIGNAL ;
    PORT
      LAYER Metal3 ;
        RECT  1899.6 1351.78 1900 1352.18 ;
    END
  END window_o[124]
  PIN window_o[125]
    DIRECTION OUTPUT ;
    USE SIGNAL ;
    PORT
      LAYER Metal3 ;
        RECT  1899.6 1350.1 1900 1350.5 ;
    END
  END window_o[125]
  PIN window_o[126]
    DIRECTION OUTPUT ;
    USE SIGNAL ;
    PORT
      LAYER Metal3 ;
        RECT  1899.6 1348.42 1900 1348.82 ;
    END
  END window_o[126]
  PIN window_o[127]
    DIRECTION OUTPUT ;
    USE SIGNAL ;
    PORT
      LAYER Metal3 ;
        RECT  1899.6 1346.74 1900 1347.14 ;
    END
  END window_o[127]
  PIN window_o[128]
    DIRECTION OUTPUT ;
    USE SIGNAL ;
    PORT
      LAYER Metal3 ;
        RECT  1899.6 1345.06 1900 1345.46 ;
    END
  END window_o[128]
  PIN window_o[129]
    DIRECTION OUTPUT ;
    USE SIGNAL ;
    PORT
      LAYER Metal3 ;
        RECT  1899.6 1343.38 1900 1343.78 ;
    END
  END window_o[129]
  PIN window_o[12]
    DIRECTION OUTPUT ;
    USE SIGNAL ;
    PORT
      LAYER Metal3 ;
        RECT  1899.6 1539.94 1900 1540.34 ;
    END
  END window_o[12]
  PIN window_o[130]
    DIRECTION OUTPUT ;
    USE SIGNAL ;
    PORT
      LAYER Metal3 ;
        RECT  1899.6 1341.7 1900 1342.1 ;
    END
  END window_o[130]
  PIN window_o[131]
    DIRECTION OUTPUT ;
    USE SIGNAL ;
    PORT
      LAYER Metal3 ;
        RECT  1899.6 1340.02 1900 1340.42 ;
    END
  END window_o[131]
  PIN window_o[132]
    DIRECTION OUTPUT ;
    USE SIGNAL ;
    PORT
      LAYER Metal3 ;
        RECT  1899.6 1338.34 1900 1338.74 ;
    END
  END window_o[132]
  PIN window_o[133]
    DIRECTION OUTPUT ;
    USE SIGNAL ;
    PORT
      LAYER Metal3 ;
        RECT  1899.6 1336.66 1900 1337.06 ;
    END
  END window_o[133]
  PIN window_o[134]
    DIRECTION OUTPUT ;
    USE SIGNAL ;
    PORT
      LAYER Metal3 ;
        RECT  1899.6 1334.98 1900 1335.38 ;
    END
  END window_o[134]
  PIN window_o[135]
    DIRECTION OUTPUT ;
    USE SIGNAL ;
    PORT
      LAYER Metal3 ;
        RECT  1899.6 1333.3 1900 1333.7 ;
    END
  END window_o[135]
  PIN window_o[136]
    DIRECTION OUTPUT ;
    USE SIGNAL ;
    PORT
      LAYER Metal3 ;
        RECT  1899.6 1331.62 1900 1332.02 ;
    END
  END window_o[136]
  PIN window_o[137]
    DIRECTION OUTPUT ;
    USE SIGNAL ;
    PORT
      LAYER Metal3 ;
        RECT  1899.6 1329.94 1900 1330.34 ;
    END
  END window_o[137]
  PIN window_o[138]
    DIRECTION OUTPUT ;
    USE SIGNAL ;
    PORT
      LAYER Metal3 ;
        RECT  1899.6 1328.26 1900 1328.66 ;
    END
  END window_o[138]
  PIN window_o[139]
    DIRECTION OUTPUT ;
    USE SIGNAL ;
    PORT
      LAYER Metal3 ;
        RECT  1899.6 1326.58 1900 1326.98 ;
    END
  END window_o[139]
  PIN window_o[13]
    DIRECTION OUTPUT ;
    USE SIGNAL ;
    PORT
      LAYER Metal3 ;
        RECT  1899.6 1538.26 1900 1538.66 ;
    END
  END window_o[13]
  PIN window_o[140]
    DIRECTION OUTPUT ;
    USE SIGNAL ;
    PORT
      LAYER Metal3 ;
        RECT  1899.6 1324.9 1900 1325.3 ;
    END
  END window_o[140]
  PIN window_o[141]
    DIRECTION OUTPUT ;
    USE SIGNAL ;
    PORT
      LAYER Metal3 ;
        RECT  1899.6 1323.22 1900 1323.62 ;
    END
  END window_o[141]
  PIN window_o[142]
    DIRECTION OUTPUT ;
    USE SIGNAL ;
    PORT
      LAYER Metal3 ;
        RECT  1899.6 1321.54 1900 1321.94 ;
    END
  END window_o[142]
  PIN window_o[143]
    DIRECTION OUTPUT ;
    USE SIGNAL ;
    PORT
      LAYER Metal3 ;
        RECT  1899.6 1319.86 1900 1320.26 ;
    END
  END window_o[143]
  PIN window_o[144]
    DIRECTION OUTPUT ;
    USE SIGNAL ;
    PORT
      LAYER Metal3 ;
        RECT  1899.6 1318.18 1900 1318.58 ;
    END
  END window_o[144]
  PIN window_o[145]
    DIRECTION OUTPUT ;
    USE SIGNAL ;
    PORT
      LAYER Metal3 ;
        RECT  1899.6 1316.5 1900 1316.9 ;
    END
  END window_o[145]
  PIN window_o[146]
    DIRECTION OUTPUT ;
    USE SIGNAL ;
    PORT
      LAYER Metal3 ;
        RECT  1899.6 1314.82 1900 1315.22 ;
    END
  END window_o[146]
  PIN window_o[147]
    DIRECTION OUTPUT ;
    USE SIGNAL ;
    PORT
      LAYER Metal3 ;
        RECT  1899.6 1313.14 1900 1313.54 ;
    END
  END window_o[147]
  PIN window_o[148]
    DIRECTION OUTPUT ;
    USE SIGNAL ;
    PORT
      LAYER Metal3 ;
        RECT  1899.6 1311.46 1900 1311.86 ;
    END
  END window_o[148]
  PIN window_o[149]
    DIRECTION OUTPUT ;
    USE SIGNAL ;
    PORT
      LAYER Metal3 ;
        RECT  1899.6 1309.78 1900 1310.18 ;
    END
  END window_o[149]
  PIN window_o[14]
    DIRECTION OUTPUT ;
    USE SIGNAL ;
    PORT
      LAYER Metal3 ;
        RECT  1899.6 1536.58 1900 1536.98 ;
    END
  END window_o[14]
  PIN window_o[150]
    DIRECTION OUTPUT ;
    USE SIGNAL ;
    PORT
      LAYER Metal3 ;
        RECT  1899.6 1308.1 1900 1308.5 ;
    END
  END window_o[150]
  PIN window_o[151]
    DIRECTION OUTPUT ;
    USE SIGNAL ;
    PORT
      LAYER Metal3 ;
        RECT  1899.6 1306.42 1900 1306.82 ;
    END
  END window_o[151]
  PIN window_o[152]
    DIRECTION OUTPUT ;
    USE SIGNAL ;
    PORT
      LAYER Metal3 ;
        RECT  1899.6 1304.74 1900 1305.14 ;
    END
  END window_o[152]
  PIN window_o[153]
    DIRECTION OUTPUT ;
    USE SIGNAL ;
    PORT
      LAYER Metal3 ;
        RECT  1899.6 1303.06 1900 1303.46 ;
    END
  END window_o[153]
  PIN window_o[154]
    DIRECTION OUTPUT ;
    USE SIGNAL ;
    PORT
      LAYER Metal3 ;
        RECT  1899.6 1301.38 1900 1301.78 ;
    END
  END window_o[154]
  PIN window_o[155]
    DIRECTION OUTPUT ;
    USE SIGNAL ;
    PORT
      LAYER Metal3 ;
        RECT  1899.6 1299.7 1900 1300.1 ;
    END
  END window_o[155]
  PIN window_o[156]
    DIRECTION OUTPUT ;
    USE SIGNAL ;
    PORT
      LAYER Metal3 ;
        RECT  1899.6 1298.02 1900 1298.42 ;
    END
  END window_o[156]
  PIN window_o[157]
    DIRECTION OUTPUT ;
    USE SIGNAL ;
    PORT
      LAYER Metal3 ;
        RECT  1899.6 1296.34 1900 1296.74 ;
    END
  END window_o[157]
  PIN window_o[158]
    DIRECTION OUTPUT ;
    USE SIGNAL ;
    PORT
      LAYER Metal3 ;
        RECT  1899.6 1294.66 1900 1295.06 ;
    END
  END window_o[158]
  PIN window_o[159]
    DIRECTION OUTPUT ;
    USE SIGNAL ;
    PORT
      LAYER Metal3 ;
        RECT  1899.6 1292.98 1900 1293.38 ;
    END
  END window_o[159]
  PIN window_o[15]
    DIRECTION OUTPUT ;
    USE SIGNAL ;
    PORT
      LAYER Metal3 ;
        RECT  1899.6 1534.9 1900 1535.3 ;
    END
  END window_o[15]
  PIN window_o[160]
    DIRECTION OUTPUT ;
    USE SIGNAL ;
    PORT
      LAYER Metal3 ;
        RECT  1899.6 1291.3 1900 1291.7 ;
    END
  END window_o[160]
  PIN window_o[161]
    DIRECTION OUTPUT ;
    USE SIGNAL ;
    PORT
      LAYER Metal3 ;
        RECT  1899.6 1289.62 1900 1290.02 ;
    END
  END window_o[161]
  PIN window_o[162]
    DIRECTION OUTPUT ;
    USE SIGNAL ;
    PORT
      LAYER Metal3 ;
        RECT  1899.6 1287.94 1900 1288.34 ;
    END
  END window_o[162]
  PIN window_o[163]
    DIRECTION OUTPUT ;
    USE SIGNAL ;
    PORT
      LAYER Metal3 ;
        RECT  1899.6 1286.26 1900 1286.66 ;
    END
  END window_o[163]
  PIN window_o[164]
    DIRECTION OUTPUT ;
    USE SIGNAL ;
    PORT
      LAYER Metal3 ;
        RECT  1899.6 1284.58 1900 1284.98 ;
    END
  END window_o[164]
  PIN window_o[165]
    DIRECTION OUTPUT ;
    USE SIGNAL ;
    PORT
      LAYER Metal3 ;
        RECT  1899.6 1282.9 1900 1283.3 ;
    END
  END window_o[165]
  PIN window_o[166]
    DIRECTION OUTPUT ;
    USE SIGNAL ;
    PORT
      LAYER Metal3 ;
        RECT  1899.6 1281.22 1900 1281.62 ;
    END
  END window_o[166]
  PIN window_o[167]
    DIRECTION OUTPUT ;
    USE SIGNAL ;
    PORT
      LAYER Metal3 ;
        RECT  1899.6 1279.54 1900 1279.94 ;
    END
  END window_o[167]
  PIN window_o[168]
    DIRECTION OUTPUT ;
    USE SIGNAL ;
    PORT
      LAYER Metal3 ;
        RECT  1899.6 1277.86 1900 1278.26 ;
    END
  END window_o[168]
  PIN window_o[169]
    DIRECTION OUTPUT ;
    USE SIGNAL ;
    PORT
      LAYER Metal3 ;
        RECT  1899.6 1276.18 1900 1276.58 ;
    END
  END window_o[169]
  PIN window_o[16]
    DIRECTION OUTPUT ;
    USE SIGNAL ;
    PORT
      LAYER Metal3 ;
        RECT  1899.6 1533.22 1900 1533.62 ;
    END
  END window_o[16]
  PIN window_o[170]
    DIRECTION OUTPUT ;
    USE SIGNAL ;
    PORT
      LAYER Metal3 ;
        RECT  1899.6 1274.5 1900 1274.9 ;
    END
  END window_o[170]
  PIN window_o[171]
    DIRECTION OUTPUT ;
    USE SIGNAL ;
    PORT
      LAYER Metal3 ;
        RECT  1899.6 1272.82 1900 1273.22 ;
    END
  END window_o[171]
  PIN window_o[172]
    DIRECTION OUTPUT ;
    USE SIGNAL ;
    PORT
      LAYER Metal3 ;
        RECT  1899.6 1271.14 1900 1271.54 ;
    END
  END window_o[172]
  PIN window_o[173]
    DIRECTION OUTPUT ;
    USE SIGNAL ;
    PORT
      LAYER Metal3 ;
        RECT  1899.6 1269.46 1900 1269.86 ;
    END
  END window_o[173]
  PIN window_o[174]
    DIRECTION OUTPUT ;
    USE SIGNAL ;
    PORT
      LAYER Metal3 ;
        RECT  1899.6 1267.78 1900 1268.18 ;
    END
  END window_o[174]
  PIN window_o[175]
    DIRECTION OUTPUT ;
    USE SIGNAL ;
    PORT
      LAYER Metal3 ;
        RECT  1899.6 1266.1 1900 1266.5 ;
    END
  END window_o[175]
  PIN window_o[176]
    DIRECTION OUTPUT ;
    USE SIGNAL ;
    PORT
      LAYER Metal3 ;
        RECT  1899.6 1264.42 1900 1264.82 ;
    END
  END window_o[176]
  PIN window_o[177]
    DIRECTION OUTPUT ;
    USE SIGNAL ;
    PORT
      LAYER Metal3 ;
        RECT  1899.6 1262.74 1900 1263.14 ;
    END
  END window_o[177]
  PIN window_o[178]
    DIRECTION OUTPUT ;
    USE SIGNAL ;
    PORT
      LAYER Metal3 ;
        RECT  1899.6 1261.06 1900 1261.46 ;
    END
  END window_o[178]
  PIN window_o[179]
    DIRECTION OUTPUT ;
    USE SIGNAL ;
    PORT
      LAYER Metal3 ;
        RECT  1899.6 1259.38 1900 1259.78 ;
    END
  END window_o[179]
  PIN window_o[17]
    DIRECTION OUTPUT ;
    USE SIGNAL ;
    PORT
      LAYER Metal3 ;
        RECT  1899.6 1531.54 1900 1531.94 ;
    END
  END window_o[17]
  PIN window_o[180]
    DIRECTION OUTPUT ;
    USE SIGNAL ;
    PORT
      LAYER Metal3 ;
        RECT  1899.6 1257.7 1900 1258.1 ;
    END
  END window_o[180]
  PIN window_o[181]
    DIRECTION OUTPUT ;
    USE SIGNAL ;
    PORT
      LAYER Metal3 ;
        RECT  1899.6 1256.02 1900 1256.42 ;
    END
  END window_o[181]
  PIN window_o[182]
    DIRECTION OUTPUT ;
    USE SIGNAL ;
    PORT
      LAYER Metal3 ;
        RECT  1899.6 1254.34 1900 1254.74 ;
    END
  END window_o[182]
  PIN window_o[183]
    DIRECTION OUTPUT ;
    USE SIGNAL ;
    PORT
      LAYER Metal3 ;
        RECT  1899.6 1252.66 1900 1253.06 ;
    END
  END window_o[183]
  PIN window_o[184]
    DIRECTION OUTPUT ;
    USE SIGNAL ;
    PORT
      LAYER Metal3 ;
        RECT  1899.6 1250.98 1900 1251.38 ;
    END
  END window_o[184]
  PIN window_o[185]
    DIRECTION OUTPUT ;
    USE SIGNAL ;
    PORT
      LAYER Metal3 ;
        RECT  1899.6 1249.3 1900 1249.7 ;
    END
  END window_o[185]
  PIN window_o[186]
    DIRECTION OUTPUT ;
    USE SIGNAL ;
    PORT
      LAYER Metal3 ;
        RECT  1899.6 1247.62 1900 1248.02 ;
    END
  END window_o[186]
  PIN window_o[187]
    DIRECTION OUTPUT ;
    USE SIGNAL ;
    PORT
      LAYER Metal3 ;
        RECT  1899.6 1245.94 1900 1246.34 ;
    END
  END window_o[187]
  PIN window_o[188]
    DIRECTION OUTPUT ;
    USE SIGNAL ;
    PORT
      LAYER Metal3 ;
        RECT  1899.6 1244.26 1900 1244.66 ;
    END
  END window_o[188]
  PIN window_o[189]
    DIRECTION OUTPUT ;
    USE SIGNAL ;
    PORT
      LAYER Metal3 ;
        RECT  1899.6 1242.58 1900 1242.98 ;
    END
  END window_o[189]
  PIN window_o[18]
    DIRECTION OUTPUT ;
    USE SIGNAL ;
    PORT
      LAYER Metal3 ;
        RECT  1899.6 1529.86 1900 1530.26 ;
    END
  END window_o[18]
  PIN window_o[190]
    DIRECTION OUTPUT ;
    USE SIGNAL ;
    PORT
      LAYER Metal3 ;
        RECT  1899.6 1240.9 1900 1241.3 ;
    END
  END window_o[190]
  PIN window_o[191]
    DIRECTION OUTPUT ;
    USE SIGNAL ;
    PORT
      LAYER Metal3 ;
        RECT  1899.6 1239.22 1900 1239.62 ;
    END
  END window_o[191]
  PIN window_o[192]
    DIRECTION OUTPUT ;
    USE SIGNAL ;
    PORT
      LAYER Metal3 ;
        RECT  1899.6 1237.54 1900 1237.94 ;
    END
  END window_o[192]
  PIN window_o[193]
    DIRECTION OUTPUT ;
    USE SIGNAL ;
    PORT
      LAYER Metal3 ;
        RECT  1899.6 1235.86 1900 1236.26 ;
    END
  END window_o[193]
  PIN window_o[194]
    DIRECTION OUTPUT ;
    USE SIGNAL ;
    PORT
      LAYER Metal3 ;
        RECT  1899.6 1234.18 1900 1234.58 ;
    END
  END window_o[194]
  PIN window_o[195]
    DIRECTION OUTPUT ;
    USE SIGNAL ;
    PORT
      LAYER Metal3 ;
        RECT  1899.6 1232.5 1900 1232.9 ;
    END
  END window_o[195]
  PIN window_o[196]
    DIRECTION OUTPUT ;
    USE SIGNAL ;
    PORT
      LAYER Metal3 ;
        RECT  1899.6 1230.82 1900 1231.22 ;
    END
  END window_o[196]
  PIN window_o[197]
    DIRECTION OUTPUT ;
    USE SIGNAL ;
    PORT
      LAYER Metal3 ;
        RECT  1899.6 1229.14 1900 1229.54 ;
    END
  END window_o[197]
  PIN window_o[198]
    DIRECTION OUTPUT ;
    USE SIGNAL ;
    PORT
      LAYER Metal3 ;
        RECT  1899.6 1227.46 1900 1227.86 ;
    END
  END window_o[198]
  PIN window_o[199]
    DIRECTION OUTPUT ;
    USE SIGNAL ;
    PORT
      LAYER Metal3 ;
        RECT  1899.6 1225.78 1900 1226.18 ;
    END
  END window_o[199]
  PIN window_o[19]
    DIRECTION OUTPUT ;
    USE SIGNAL ;
    PORT
      LAYER Metal3 ;
        RECT  1899.6 1528.18 1900 1528.58 ;
    END
  END window_o[19]
  PIN window_o[1]
    DIRECTION OUTPUT ;
    USE SIGNAL ;
    PORT
      LAYER Metal3 ;
        RECT  1899.6 1558.42 1900 1558.82 ;
    END
  END window_o[1]
  PIN window_o[200]
    DIRECTION OUTPUT ;
    USE SIGNAL ;
    PORT
      LAYER Metal3 ;
        RECT  1899.6 1224.1 1900 1224.5 ;
    END
  END window_o[200]
  PIN window_o[201]
    DIRECTION OUTPUT ;
    USE SIGNAL ;
    PORT
      LAYER Metal3 ;
        RECT  1899.6 1222.42 1900 1222.82 ;
    END
  END window_o[201]
  PIN window_o[202]
    DIRECTION OUTPUT ;
    USE SIGNAL ;
    PORT
      LAYER Metal3 ;
        RECT  1899.6 1220.74 1900 1221.14 ;
    END
  END window_o[202]
  PIN window_o[203]
    DIRECTION OUTPUT ;
    USE SIGNAL ;
    PORT
      LAYER Metal3 ;
        RECT  1899.6 1219.06 1900 1219.46 ;
    END
  END window_o[203]
  PIN window_o[204]
    DIRECTION OUTPUT ;
    USE SIGNAL ;
    PORT
      LAYER Metal3 ;
        RECT  1899.6 1217.38 1900 1217.78 ;
    END
  END window_o[204]
  PIN window_o[205]
    DIRECTION OUTPUT ;
    USE SIGNAL ;
    PORT
      LAYER Metal3 ;
        RECT  1899.6 1215.7 1900 1216.1 ;
    END
  END window_o[205]
  PIN window_o[206]
    DIRECTION OUTPUT ;
    USE SIGNAL ;
    PORT
      LAYER Metal3 ;
        RECT  1899.6 1214.02 1900 1214.42 ;
    END
  END window_o[206]
  PIN window_o[207]
    DIRECTION OUTPUT ;
    USE SIGNAL ;
    PORT
      LAYER Metal3 ;
        RECT  1899.6 1212.34 1900 1212.74 ;
    END
  END window_o[207]
  PIN window_o[208]
    DIRECTION OUTPUT ;
    USE SIGNAL ;
    PORT
      LAYER Metal3 ;
        RECT  1899.6 1210.66 1900 1211.06 ;
    END
  END window_o[208]
  PIN window_o[209]
    DIRECTION OUTPUT ;
    USE SIGNAL ;
    PORT
      LAYER Metal3 ;
        RECT  1899.6 1208.98 1900 1209.38 ;
    END
  END window_o[209]
  PIN window_o[20]
    DIRECTION OUTPUT ;
    USE SIGNAL ;
    PORT
      LAYER Metal3 ;
        RECT  1899.6 1526.5 1900 1526.9 ;
    END
  END window_o[20]
  PIN window_o[210]
    DIRECTION OUTPUT ;
    USE SIGNAL ;
    PORT
      LAYER Metal3 ;
        RECT  1899.6 1207.3 1900 1207.7 ;
    END
  END window_o[210]
  PIN window_o[211]
    DIRECTION OUTPUT ;
    USE SIGNAL ;
    PORT
      LAYER Metal3 ;
        RECT  1899.6 1205.62 1900 1206.02 ;
    END
  END window_o[211]
  PIN window_o[212]
    DIRECTION OUTPUT ;
    USE SIGNAL ;
    PORT
      LAYER Metal3 ;
        RECT  1899.6 1203.94 1900 1204.34 ;
    END
  END window_o[212]
  PIN window_o[213]
    DIRECTION OUTPUT ;
    USE SIGNAL ;
    PORT
      LAYER Metal3 ;
        RECT  1899.6 1202.26 1900 1202.66 ;
    END
  END window_o[213]
  PIN window_o[214]
    DIRECTION OUTPUT ;
    USE SIGNAL ;
    PORT
      LAYER Metal3 ;
        RECT  1899.6 1200.58 1900 1200.98 ;
    END
  END window_o[214]
  PIN window_o[215]
    DIRECTION OUTPUT ;
    USE SIGNAL ;
    PORT
      LAYER Metal3 ;
        RECT  1899.6 1198.9 1900 1199.3 ;
    END
  END window_o[215]
  PIN window_o[216]
    DIRECTION OUTPUT ;
    USE SIGNAL ;
    PORT
      LAYER Metal3 ;
        RECT  1899.6 1197.22 1900 1197.62 ;
    END
  END window_o[216]
  PIN window_o[217]
    DIRECTION OUTPUT ;
    USE SIGNAL ;
    PORT
      LAYER Metal3 ;
        RECT  1899.6 1195.54 1900 1195.94 ;
    END
  END window_o[217]
  PIN window_o[218]
    DIRECTION OUTPUT ;
    USE SIGNAL ;
    PORT
      LAYER Metal3 ;
        RECT  1899.6 1193.86 1900 1194.26 ;
    END
  END window_o[218]
  PIN window_o[219]
    DIRECTION OUTPUT ;
    USE SIGNAL ;
    PORT
      LAYER Metal3 ;
        RECT  1899.6 1192.18 1900 1192.58 ;
    END
  END window_o[219]
  PIN window_o[21]
    DIRECTION OUTPUT ;
    USE SIGNAL ;
    PORT
      LAYER Metal3 ;
        RECT  1899.6 1524.82 1900 1525.22 ;
    END
  END window_o[21]
  PIN window_o[220]
    DIRECTION OUTPUT ;
    USE SIGNAL ;
    PORT
      LAYER Metal3 ;
        RECT  1899.6 1190.5 1900 1190.9 ;
    END
  END window_o[220]
  PIN window_o[221]
    DIRECTION OUTPUT ;
    USE SIGNAL ;
    PORT
      LAYER Metal3 ;
        RECT  1899.6 1188.82 1900 1189.22 ;
    END
  END window_o[221]
  PIN window_o[222]
    DIRECTION OUTPUT ;
    USE SIGNAL ;
    PORT
      LAYER Metal3 ;
        RECT  1899.6 1187.14 1900 1187.54 ;
    END
  END window_o[222]
  PIN window_o[223]
    DIRECTION OUTPUT ;
    USE SIGNAL ;
    PORT
      LAYER Metal3 ;
        RECT  1899.6 1185.46 1900 1185.86 ;
    END
  END window_o[223]
  PIN window_o[224]
    DIRECTION OUTPUT ;
    USE SIGNAL ;
    PORT
      LAYER Metal3 ;
        RECT  1899.6 1183.78 1900 1184.18 ;
    END
  END window_o[224]
  PIN window_o[225]
    DIRECTION OUTPUT ;
    USE SIGNAL ;
    PORT
      LAYER Metal3 ;
        RECT  1899.6 1182.1 1900 1182.5 ;
    END
  END window_o[225]
  PIN window_o[226]
    DIRECTION OUTPUT ;
    USE SIGNAL ;
    PORT
      LAYER Metal3 ;
        RECT  1899.6 1180.42 1900 1180.82 ;
    END
  END window_o[226]
  PIN window_o[227]
    DIRECTION OUTPUT ;
    USE SIGNAL ;
    PORT
      LAYER Metal3 ;
        RECT  1899.6 1178.74 1900 1179.14 ;
    END
  END window_o[227]
  PIN window_o[228]
    DIRECTION OUTPUT ;
    USE SIGNAL ;
    PORT
      LAYER Metal3 ;
        RECT  1899.6 1177.06 1900 1177.46 ;
    END
  END window_o[228]
  PIN window_o[229]
    DIRECTION OUTPUT ;
    USE SIGNAL ;
    PORT
      LAYER Metal3 ;
        RECT  1899.6 1175.38 1900 1175.78 ;
    END
  END window_o[229]
  PIN window_o[22]
    DIRECTION OUTPUT ;
    USE SIGNAL ;
    PORT
      LAYER Metal3 ;
        RECT  1899.6 1523.14 1900 1523.54 ;
    END
  END window_o[22]
  PIN window_o[230]
    DIRECTION OUTPUT ;
    USE SIGNAL ;
    PORT
      LAYER Metal3 ;
        RECT  1899.6 1173.7 1900 1174.1 ;
    END
  END window_o[230]
  PIN window_o[231]
    DIRECTION OUTPUT ;
    USE SIGNAL ;
    PORT
      LAYER Metal3 ;
        RECT  1899.6 1172.02 1900 1172.42 ;
    END
  END window_o[231]
  PIN window_o[232]
    DIRECTION OUTPUT ;
    USE SIGNAL ;
    PORT
      LAYER Metal3 ;
        RECT  1899.6 1170.34 1900 1170.74 ;
    END
  END window_o[232]
  PIN window_o[233]
    DIRECTION OUTPUT ;
    USE SIGNAL ;
    PORT
      LAYER Metal3 ;
        RECT  1899.6 1168.66 1900 1169.06 ;
    END
  END window_o[233]
  PIN window_o[234]
    DIRECTION OUTPUT ;
    USE SIGNAL ;
    PORT
      LAYER Metal3 ;
        RECT  1899.6 1166.98 1900 1167.38 ;
    END
  END window_o[234]
  PIN window_o[235]
    DIRECTION OUTPUT ;
    USE SIGNAL ;
    PORT
      LAYER Metal3 ;
        RECT  1899.6 1165.3 1900 1165.7 ;
    END
  END window_o[235]
  PIN window_o[236]
    DIRECTION OUTPUT ;
    USE SIGNAL ;
    PORT
      LAYER Metal3 ;
        RECT  1899.6 1163.62 1900 1164.02 ;
    END
  END window_o[236]
  PIN window_o[237]
    DIRECTION OUTPUT ;
    USE SIGNAL ;
    PORT
      LAYER Metal3 ;
        RECT  1899.6 1161.94 1900 1162.34 ;
    END
  END window_o[237]
  PIN window_o[238]
    DIRECTION OUTPUT ;
    USE SIGNAL ;
    PORT
      LAYER Metal3 ;
        RECT  1899.6 1160.26 1900 1160.66 ;
    END
  END window_o[238]
  PIN window_o[239]
    DIRECTION OUTPUT ;
    USE SIGNAL ;
    PORT
      LAYER Metal3 ;
        RECT  1899.6 1158.58 1900 1158.98 ;
    END
  END window_o[239]
  PIN window_o[23]
    DIRECTION OUTPUT ;
    USE SIGNAL ;
    PORT
      LAYER Metal3 ;
        RECT  1899.6 1521.46 1900 1521.86 ;
    END
  END window_o[23]
  PIN window_o[240]
    DIRECTION OUTPUT ;
    USE SIGNAL ;
    PORT
      LAYER Metal3 ;
        RECT  1899.6 1156.9 1900 1157.3 ;
    END
  END window_o[240]
  PIN window_o[241]
    DIRECTION OUTPUT ;
    USE SIGNAL ;
    PORT
      LAYER Metal3 ;
        RECT  1899.6 1155.22 1900 1155.62 ;
    END
  END window_o[241]
  PIN window_o[242]
    DIRECTION OUTPUT ;
    USE SIGNAL ;
    PORT
      LAYER Metal3 ;
        RECT  1899.6 1153.54 1900 1153.94 ;
    END
  END window_o[242]
  PIN window_o[243]
    DIRECTION OUTPUT ;
    USE SIGNAL ;
    PORT
      LAYER Metal3 ;
        RECT  1899.6 1151.86 1900 1152.26 ;
    END
  END window_o[243]
  PIN window_o[244]
    DIRECTION OUTPUT ;
    USE SIGNAL ;
    PORT
      LAYER Metal3 ;
        RECT  1899.6 1150.18 1900 1150.58 ;
    END
  END window_o[244]
  PIN window_o[245]
    DIRECTION OUTPUT ;
    USE SIGNAL ;
    PORT
      LAYER Metal3 ;
        RECT  1899.6 1148.5 1900 1148.9 ;
    END
  END window_o[245]
  PIN window_o[246]
    DIRECTION OUTPUT ;
    USE SIGNAL ;
    PORT
      LAYER Metal3 ;
        RECT  1899.6 1146.82 1900 1147.22 ;
    END
  END window_o[246]
  PIN window_o[247]
    DIRECTION OUTPUT ;
    USE SIGNAL ;
    PORT
      LAYER Metal3 ;
        RECT  1899.6 1145.14 1900 1145.54 ;
    END
  END window_o[247]
  PIN window_o[248]
    DIRECTION OUTPUT ;
    USE SIGNAL ;
    PORT
      LAYER Metal3 ;
        RECT  1899.6 1143.46 1900 1143.86 ;
    END
  END window_o[248]
  PIN window_o[249]
    DIRECTION OUTPUT ;
    USE SIGNAL ;
    PORT
      LAYER Metal3 ;
        RECT  1899.6 1141.78 1900 1142.18 ;
    END
  END window_o[249]
  PIN window_o[24]
    DIRECTION OUTPUT ;
    USE SIGNAL ;
    PORT
      LAYER Metal3 ;
        RECT  1899.6 1519.78 1900 1520.18 ;
    END
  END window_o[24]
  PIN window_o[250]
    DIRECTION OUTPUT ;
    USE SIGNAL ;
    PORT
      LAYER Metal3 ;
        RECT  1899.6 1140.1 1900 1140.5 ;
    END
  END window_o[250]
  PIN window_o[251]
    DIRECTION OUTPUT ;
    USE SIGNAL ;
    PORT
      LAYER Metal3 ;
        RECT  1899.6 1138.42 1900 1138.82 ;
    END
  END window_o[251]
  PIN window_o[252]
    DIRECTION OUTPUT ;
    USE SIGNAL ;
    PORT
      LAYER Metal3 ;
        RECT  1899.6 1136.74 1900 1137.14 ;
    END
  END window_o[252]
  PIN window_o[253]
    DIRECTION OUTPUT ;
    USE SIGNAL ;
    PORT
      LAYER Metal3 ;
        RECT  1899.6 1135.06 1900 1135.46 ;
    END
  END window_o[253]
  PIN window_o[254]
    DIRECTION OUTPUT ;
    USE SIGNAL ;
    PORT
      LAYER Metal3 ;
        RECT  1899.6 1133.38 1900 1133.78 ;
    END
  END window_o[254]
  PIN window_o[255]
    DIRECTION OUTPUT ;
    USE SIGNAL ;
    PORT
      LAYER Metal3 ;
        RECT  1899.6 1131.7 1900 1132.1 ;
    END
  END window_o[255]
  PIN window_o[25]
    DIRECTION OUTPUT ;
    USE SIGNAL ;
    PORT
      LAYER Metal3 ;
        RECT  1899.6 1518.1 1900 1518.5 ;
    END
  END window_o[25]
  PIN window_o[26]
    DIRECTION OUTPUT ;
    USE SIGNAL ;
    PORT
      LAYER Metal3 ;
        RECT  1899.6 1516.42 1900 1516.82 ;
    END
  END window_o[26]
  PIN window_o[27]
    DIRECTION OUTPUT ;
    USE SIGNAL ;
    PORT
      LAYER Metal3 ;
        RECT  1899.6 1514.74 1900 1515.14 ;
    END
  END window_o[27]
  PIN window_o[28]
    DIRECTION OUTPUT ;
    USE SIGNAL ;
    PORT
      LAYER Metal3 ;
        RECT  1899.6 1513.06 1900 1513.46 ;
    END
  END window_o[28]
  PIN window_o[29]
    DIRECTION OUTPUT ;
    USE SIGNAL ;
    PORT
      LAYER Metal3 ;
        RECT  1899.6 1511.38 1900 1511.78 ;
    END
  END window_o[29]
  PIN window_o[2]
    DIRECTION OUTPUT ;
    USE SIGNAL ;
    PORT
      LAYER Metal3 ;
        RECT  1899.6 1556.74 1900 1557.14 ;
    END
  END window_o[2]
  PIN window_o[30]
    DIRECTION OUTPUT ;
    USE SIGNAL ;
    PORT
      LAYER Metal3 ;
        RECT  1899.6 1509.7 1900 1510.1 ;
    END
  END window_o[30]
  PIN window_o[31]
    DIRECTION OUTPUT ;
    USE SIGNAL ;
    PORT
      LAYER Metal3 ;
        RECT  1899.6 1508.02 1900 1508.42 ;
    END
  END window_o[31]
  PIN window_o[32]
    DIRECTION OUTPUT ;
    USE SIGNAL ;
    PORT
      LAYER Metal3 ;
        RECT  1899.6 1506.34 1900 1506.74 ;
    END
  END window_o[32]
  PIN window_o[33]
    DIRECTION OUTPUT ;
    USE SIGNAL ;
    PORT
      LAYER Metal3 ;
        RECT  1899.6 1504.66 1900 1505.06 ;
    END
  END window_o[33]
  PIN window_o[34]
    DIRECTION OUTPUT ;
    USE SIGNAL ;
    PORT
      LAYER Metal3 ;
        RECT  1899.6 1502.98 1900 1503.38 ;
    END
  END window_o[34]
  PIN window_o[35]
    DIRECTION OUTPUT ;
    USE SIGNAL ;
    PORT
      LAYER Metal3 ;
        RECT  1899.6 1501.3 1900 1501.7 ;
    END
  END window_o[35]
  PIN window_o[36]
    DIRECTION OUTPUT ;
    USE SIGNAL ;
    PORT
      LAYER Metal3 ;
        RECT  1899.6 1499.62 1900 1500.02 ;
    END
  END window_o[36]
  PIN window_o[37]
    DIRECTION OUTPUT ;
    USE SIGNAL ;
    PORT
      LAYER Metal3 ;
        RECT  1899.6 1497.94 1900 1498.34 ;
    END
  END window_o[37]
  PIN window_o[38]
    DIRECTION OUTPUT ;
    USE SIGNAL ;
    PORT
      LAYER Metal3 ;
        RECT  1899.6 1496.26 1900 1496.66 ;
    END
  END window_o[38]
  PIN window_o[39]
    DIRECTION OUTPUT ;
    USE SIGNAL ;
    PORT
      LAYER Metal3 ;
        RECT  1899.6 1494.58 1900 1494.98 ;
    END
  END window_o[39]
  PIN window_o[3]
    DIRECTION OUTPUT ;
    USE SIGNAL ;
    PORT
      LAYER Metal3 ;
        RECT  1899.6 1555.06 1900 1555.46 ;
    END
  END window_o[3]
  PIN window_o[40]
    DIRECTION OUTPUT ;
    USE SIGNAL ;
    PORT
      LAYER Metal3 ;
        RECT  1899.6 1492.9 1900 1493.3 ;
    END
  END window_o[40]
  PIN window_o[41]
    DIRECTION OUTPUT ;
    USE SIGNAL ;
    PORT
      LAYER Metal3 ;
        RECT  1899.6 1491.22 1900 1491.62 ;
    END
  END window_o[41]
  PIN window_o[42]
    DIRECTION OUTPUT ;
    USE SIGNAL ;
    PORT
      LAYER Metal3 ;
        RECT  1899.6 1489.54 1900 1489.94 ;
    END
  END window_o[42]
  PIN window_o[43]
    DIRECTION OUTPUT ;
    USE SIGNAL ;
    PORT
      LAYER Metal3 ;
        RECT  1899.6 1487.86 1900 1488.26 ;
    END
  END window_o[43]
  PIN window_o[44]
    DIRECTION OUTPUT ;
    USE SIGNAL ;
    PORT
      LAYER Metal3 ;
        RECT  1899.6 1486.18 1900 1486.58 ;
    END
  END window_o[44]
  PIN window_o[45]
    DIRECTION OUTPUT ;
    USE SIGNAL ;
    PORT
      LAYER Metal3 ;
        RECT  1899.6 1484.5 1900 1484.9 ;
    END
  END window_o[45]
  PIN window_o[46]
    DIRECTION OUTPUT ;
    USE SIGNAL ;
    PORT
      LAYER Metal3 ;
        RECT  1899.6 1482.82 1900 1483.22 ;
    END
  END window_o[46]
  PIN window_o[47]
    DIRECTION OUTPUT ;
    USE SIGNAL ;
    PORT
      LAYER Metal3 ;
        RECT  1899.6 1481.14 1900 1481.54 ;
    END
  END window_o[47]
  PIN window_o[48]
    DIRECTION OUTPUT ;
    USE SIGNAL ;
    PORT
      LAYER Metal3 ;
        RECT  1899.6 1479.46 1900 1479.86 ;
    END
  END window_o[48]
  PIN window_o[49]
    DIRECTION OUTPUT ;
    USE SIGNAL ;
    PORT
      LAYER Metal3 ;
        RECT  1899.6 1477.78 1900 1478.18 ;
    END
  END window_o[49]
  PIN window_o[4]
    DIRECTION OUTPUT ;
    USE SIGNAL ;
    PORT
      LAYER Metal3 ;
        RECT  1899.6 1553.38 1900 1553.78 ;
    END
  END window_o[4]
  PIN window_o[50]
    DIRECTION OUTPUT ;
    USE SIGNAL ;
    PORT
      LAYER Metal3 ;
        RECT  1899.6 1476.1 1900 1476.5 ;
    END
  END window_o[50]
  PIN window_o[51]
    DIRECTION OUTPUT ;
    USE SIGNAL ;
    PORT
      LAYER Metal3 ;
        RECT  1899.6 1474.42 1900 1474.82 ;
    END
  END window_o[51]
  PIN window_o[52]
    DIRECTION OUTPUT ;
    USE SIGNAL ;
    PORT
      LAYER Metal3 ;
        RECT  1899.6 1472.74 1900 1473.14 ;
    END
  END window_o[52]
  PIN window_o[53]
    DIRECTION OUTPUT ;
    USE SIGNAL ;
    PORT
      LAYER Metal3 ;
        RECT  1899.6 1471.06 1900 1471.46 ;
    END
  END window_o[53]
  PIN window_o[54]
    DIRECTION OUTPUT ;
    USE SIGNAL ;
    PORT
      LAYER Metal3 ;
        RECT  1899.6 1469.38 1900 1469.78 ;
    END
  END window_o[54]
  PIN window_o[55]
    DIRECTION OUTPUT ;
    USE SIGNAL ;
    PORT
      LAYER Metal3 ;
        RECT  1899.6 1467.7 1900 1468.1 ;
    END
  END window_o[55]
  PIN window_o[56]
    DIRECTION OUTPUT ;
    USE SIGNAL ;
    PORT
      LAYER Metal3 ;
        RECT  1899.6 1466.02 1900 1466.42 ;
    END
  END window_o[56]
  PIN window_o[57]
    DIRECTION OUTPUT ;
    USE SIGNAL ;
    PORT
      LAYER Metal3 ;
        RECT  1899.6 1464.34 1900 1464.74 ;
    END
  END window_o[57]
  PIN window_o[58]
    DIRECTION OUTPUT ;
    USE SIGNAL ;
    PORT
      LAYER Metal3 ;
        RECT  1899.6 1462.66 1900 1463.06 ;
    END
  END window_o[58]
  PIN window_o[59]
    DIRECTION OUTPUT ;
    USE SIGNAL ;
    PORT
      LAYER Metal3 ;
        RECT  1899.6 1460.98 1900 1461.38 ;
    END
  END window_o[59]
  PIN window_o[5]
    DIRECTION OUTPUT ;
    USE SIGNAL ;
    PORT
      LAYER Metal3 ;
        RECT  1899.6 1551.7 1900 1552.1 ;
    END
  END window_o[5]
  PIN window_o[60]
    DIRECTION OUTPUT ;
    USE SIGNAL ;
    PORT
      LAYER Metal3 ;
        RECT  1899.6 1459.3 1900 1459.7 ;
    END
  END window_o[60]
  PIN window_o[61]
    DIRECTION OUTPUT ;
    USE SIGNAL ;
    PORT
      LAYER Metal3 ;
        RECT  1899.6 1457.62 1900 1458.02 ;
    END
  END window_o[61]
  PIN window_o[62]
    DIRECTION OUTPUT ;
    USE SIGNAL ;
    PORT
      LAYER Metal3 ;
        RECT  1899.6 1455.94 1900 1456.34 ;
    END
  END window_o[62]
  PIN window_o[63]
    DIRECTION OUTPUT ;
    USE SIGNAL ;
    PORT
      LAYER Metal3 ;
        RECT  1899.6 1454.26 1900 1454.66 ;
    END
  END window_o[63]
  PIN window_o[64]
    DIRECTION OUTPUT ;
    USE SIGNAL ;
    PORT
      LAYER Metal3 ;
        RECT  1899.6 1452.58 1900 1452.98 ;
    END
  END window_o[64]
  PIN window_o[65]
    DIRECTION OUTPUT ;
    USE SIGNAL ;
    PORT
      LAYER Metal3 ;
        RECT  1899.6 1450.9 1900 1451.3 ;
    END
  END window_o[65]
  PIN window_o[66]
    DIRECTION OUTPUT ;
    USE SIGNAL ;
    PORT
      LAYER Metal3 ;
        RECT  1899.6 1449.22 1900 1449.62 ;
    END
  END window_o[66]
  PIN window_o[67]
    DIRECTION OUTPUT ;
    USE SIGNAL ;
    PORT
      LAYER Metal3 ;
        RECT  1899.6 1447.54 1900 1447.94 ;
    END
  END window_o[67]
  PIN window_o[68]
    DIRECTION OUTPUT ;
    USE SIGNAL ;
    PORT
      LAYER Metal3 ;
        RECT  1899.6 1445.86 1900 1446.26 ;
    END
  END window_o[68]
  PIN window_o[69]
    DIRECTION OUTPUT ;
    USE SIGNAL ;
    PORT
      LAYER Metal3 ;
        RECT  1899.6 1444.18 1900 1444.58 ;
    END
  END window_o[69]
  PIN window_o[6]
    DIRECTION OUTPUT ;
    USE SIGNAL ;
    PORT
      LAYER Metal3 ;
        RECT  1899.6 1550.02 1900 1550.42 ;
    END
  END window_o[6]
  PIN window_o[70]
    DIRECTION OUTPUT ;
    USE SIGNAL ;
    PORT
      LAYER Metal3 ;
        RECT  1899.6 1442.5 1900 1442.9 ;
    END
  END window_o[70]
  PIN window_o[71]
    DIRECTION OUTPUT ;
    USE SIGNAL ;
    PORT
      LAYER Metal3 ;
        RECT  1899.6 1440.82 1900 1441.22 ;
    END
  END window_o[71]
  PIN window_o[72]
    DIRECTION OUTPUT ;
    USE SIGNAL ;
    PORT
      LAYER Metal3 ;
        RECT  1899.6 1439.14 1900 1439.54 ;
    END
  END window_o[72]
  PIN window_o[73]
    DIRECTION OUTPUT ;
    USE SIGNAL ;
    PORT
      LAYER Metal3 ;
        RECT  1899.6 1437.46 1900 1437.86 ;
    END
  END window_o[73]
  PIN window_o[74]
    DIRECTION OUTPUT ;
    USE SIGNAL ;
    PORT
      LAYER Metal3 ;
        RECT  1899.6 1435.78 1900 1436.18 ;
    END
  END window_o[74]
  PIN window_o[75]
    DIRECTION OUTPUT ;
    USE SIGNAL ;
    PORT
      LAYER Metal3 ;
        RECT  1899.6 1434.1 1900 1434.5 ;
    END
  END window_o[75]
  PIN window_o[76]
    DIRECTION OUTPUT ;
    USE SIGNAL ;
    PORT
      LAYER Metal3 ;
        RECT  1899.6 1432.42 1900 1432.82 ;
    END
  END window_o[76]
  PIN window_o[77]
    DIRECTION OUTPUT ;
    USE SIGNAL ;
    PORT
      LAYER Metal3 ;
        RECT  1899.6 1430.74 1900 1431.14 ;
    END
  END window_o[77]
  PIN window_o[78]
    DIRECTION OUTPUT ;
    USE SIGNAL ;
    PORT
      LAYER Metal3 ;
        RECT  1899.6 1429.06 1900 1429.46 ;
    END
  END window_o[78]
  PIN window_o[79]
    DIRECTION OUTPUT ;
    USE SIGNAL ;
    PORT
      LAYER Metal3 ;
        RECT  1899.6 1427.38 1900 1427.78 ;
    END
  END window_o[79]
  PIN window_o[7]
    DIRECTION OUTPUT ;
    USE SIGNAL ;
    PORT
      LAYER Metal3 ;
        RECT  1899.6 1548.34 1900 1548.74 ;
    END
  END window_o[7]
  PIN window_o[80]
    DIRECTION OUTPUT ;
    USE SIGNAL ;
    PORT
      LAYER Metal3 ;
        RECT  1899.6 1425.7 1900 1426.1 ;
    END
  END window_o[80]
  PIN window_o[81]
    DIRECTION OUTPUT ;
    USE SIGNAL ;
    PORT
      LAYER Metal3 ;
        RECT  1899.6 1424.02 1900 1424.42 ;
    END
  END window_o[81]
  PIN window_o[82]
    DIRECTION OUTPUT ;
    USE SIGNAL ;
    PORT
      LAYER Metal3 ;
        RECT  1899.6 1422.34 1900 1422.74 ;
    END
  END window_o[82]
  PIN window_o[83]
    DIRECTION OUTPUT ;
    USE SIGNAL ;
    PORT
      LAYER Metal3 ;
        RECT  1899.6 1420.66 1900 1421.06 ;
    END
  END window_o[83]
  PIN window_o[84]
    DIRECTION OUTPUT ;
    USE SIGNAL ;
    PORT
      LAYER Metal3 ;
        RECT  1899.6 1418.98 1900 1419.38 ;
    END
  END window_o[84]
  PIN window_o[85]
    DIRECTION OUTPUT ;
    USE SIGNAL ;
    PORT
      LAYER Metal3 ;
        RECT  1899.6 1417.3 1900 1417.7 ;
    END
  END window_o[85]
  PIN window_o[86]
    DIRECTION OUTPUT ;
    USE SIGNAL ;
    PORT
      LAYER Metal3 ;
        RECT  1899.6 1415.62 1900 1416.02 ;
    END
  END window_o[86]
  PIN window_o[87]
    DIRECTION OUTPUT ;
    USE SIGNAL ;
    PORT
      LAYER Metal3 ;
        RECT  1899.6 1413.94 1900 1414.34 ;
    END
  END window_o[87]
  PIN window_o[88]
    DIRECTION OUTPUT ;
    USE SIGNAL ;
    PORT
      LAYER Metal3 ;
        RECT  1899.6 1412.26 1900 1412.66 ;
    END
  END window_o[88]
  PIN window_o[89]
    DIRECTION OUTPUT ;
    USE SIGNAL ;
    PORT
      LAYER Metal3 ;
        RECT  1899.6 1410.58 1900 1410.98 ;
    END
  END window_o[89]
  PIN window_o[8]
    DIRECTION OUTPUT ;
    USE SIGNAL ;
    PORT
      LAYER Metal3 ;
        RECT  1899.6 1546.66 1900 1547.06 ;
    END
  END window_o[8]
  PIN window_o[90]
    DIRECTION OUTPUT ;
    USE SIGNAL ;
    PORT
      LAYER Metal3 ;
        RECT  1899.6 1408.9 1900 1409.3 ;
    END
  END window_o[90]
  PIN window_o[91]
    DIRECTION OUTPUT ;
    USE SIGNAL ;
    PORT
      LAYER Metal3 ;
        RECT  1899.6 1407.22 1900 1407.62 ;
    END
  END window_o[91]
  PIN window_o[92]
    DIRECTION OUTPUT ;
    USE SIGNAL ;
    PORT
      LAYER Metal3 ;
        RECT  1899.6 1405.54 1900 1405.94 ;
    END
  END window_o[92]
  PIN window_o[93]
    DIRECTION OUTPUT ;
    USE SIGNAL ;
    PORT
      LAYER Metal3 ;
        RECT  1899.6 1403.86 1900 1404.26 ;
    END
  END window_o[93]
  PIN window_o[94]
    DIRECTION OUTPUT ;
    USE SIGNAL ;
    PORT
      LAYER Metal3 ;
        RECT  1899.6 1402.18 1900 1402.58 ;
    END
  END window_o[94]
  PIN window_o[95]
    DIRECTION OUTPUT ;
    USE SIGNAL ;
    PORT
      LAYER Metal3 ;
        RECT  1899.6 1400.5 1900 1400.9 ;
    END
  END window_o[95]
  PIN window_o[96]
    DIRECTION OUTPUT ;
    USE SIGNAL ;
    PORT
      LAYER Metal3 ;
        RECT  1899.6 1398.82 1900 1399.22 ;
    END
  END window_o[96]
  PIN window_o[97]
    DIRECTION OUTPUT ;
    USE SIGNAL ;
    PORT
      LAYER Metal3 ;
        RECT  1899.6 1397.14 1900 1397.54 ;
    END
  END window_o[97]
  PIN window_o[98]
    DIRECTION OUTPUT ;
    USE SIGNAL ;
    PORT
      LAYER Metal3 ;
        RECT  1899.6 1395.46 1900 1395.86 ;
    END
  END window_o[98]
  PIN window_o[99]
    DIRECTION OUTPUT ;
    USE SIGNAL ;
    PORT
      LAYER Metal3 ;
        RECT  1899.6 1393.78 1900 1394.18 ;
    END
  END window_o[99]
  PIN window_o[9]
    DIRECTION OUTPUT ;
    USE SIGNAL ;
    PORT
      LAYER Metal3 ;
        RECT  1899.6 1544.98 1900 1545.38 ;
    END
  END window_o[9]
  PIN window_pc_o[0]
    DIRECTION OUTPUT ;
    USE SIGNAL ;
    PORT
      LAYER Metal3 ;
        RECT  1899.6 1828.9 1900 1829.3 ;
    END
  END window_pc_o[0]
  PIN window_pc_o[10]
    DIRECTION OUTPUT ;
    USE SIGNAL ;
    PORT
      LAYER Metal3 ;
        RECT  1899.6 1812.1 1900 1812.5 ;
    END
  END window_pc_o[10]
  PIN window_pc_o[11]
    DIRECTION OUTPUT ;
    USE SIGNAL ;
    PORT
      LAYER Metal3 ;
        RECT  1899.6 1810.42 1900 1810.82 ;
    END
  END window_pc_o[11]
  PIN window_pc_o[12]
    DIRECTION OUTPUT ;
    USE SIGNAL ;
    PORT
      LAYER Metal3 ;
        RECT  1899.6 1808.74 1900 1809.14 ;
    END
  END window_pc_o[12]
  PIN window_pc_o[13]
    DIRECTION OUTPUT ;
    USE SIGNAL ;
    PORT
      LAYER Metal3 ;
        RECT  1899.6 1807.06 1900 1807.46 ;
    END
  END window_pc_o[13]
  PIN window_pc_o[14]
    DIRECTION OUTPUT ;
    USE SIGNAL ;
    PORT
      LAYER Metal3 ;
        RECT  1899.6 1805.38 1900 1805.78 ;
    END
  END window_pc_o[14]
  PIN window_pc_o[15]
    DIRECTION OUTPUT ;
    USE SIGNAL ;
    PORT
      LAYER Metal3 ;
        RECT  1899.6 1803.7 1900 1804.1 ;
    END
  END window_pc_o[15]
  PIN window_pc_o[16]
    DIRECTION OUTPUT ;
    USE SIGNAL ;
    PORT
      LAYER Metal3 ;
        RECT  1899.6 1802.02 1900 1802.42 ;
    END
  END window_pc_o[16]
  PIN window_pc_o[17]
    DIRECTION OUTPUT ;
    USE SIGNAL ;
    PORT
      LAYER Metal3 ;
        RECT  1899.6 1800.34 1900 1800.74 ;
    END
  END window_pc_o[17]
  PIN window_pc_o[18]
    DIRECTION OUTPUT ;
    USE SIGNAL ;
    PORT
      LAYER Metal3 ;
        RECT  1899.6 1798.66 1900 1799.06 ;
    END
  END window_pc_o[18]
  PIN window_pc_o[19]
    DIRECTION OUTPUT ;
    USE SIGNAL ;
    PORT
      LAYER Metal3 ;
        RECT  1899.6 1796.98 1900 1797.38 ;
    END
  END window_pc_o[19]
  PIN window_pc_o[1]
    DIRECTION OUTPUT ;
    USE SIGNAL ;
    PORT
      LAYER Metal3 ;
        RECT  1899.6 1827.22 1900 1827.62 ;
    END
  END window_pc_o[1]
  PIN window_pc_o[20]
    DIRECTION OUTPUT ;
    USE SIGNAL ;
    PORT
      LAYER Metal3 ;
        RECT  1899.6 1795.3 1900 1795.7 ;
    END
  END window_pc_o[20]
  PIN window_pc_o[21]
    DIRECTION OUTPUT ;
    USE SIGNAL ;
    PORT
      LAYER Metal3 ;
        RECT  1899.6 1793.62 1900 1794.02 ;
    END
  END window_pc_o[21]
  PIN window_pc_o[22]
    DIRECTION OUTPUT ;
    USE SIGNAL ;
    PORT
      LAYER Metal3 ;
        RECT  1899.6 1791.94 1900 1792.34 ;
    END
  END window_pc_o[22]
  PIN window_pc_o[23]
    DIRECTION OUTPUT ;
    USE SIGNAL ;
    PORT
      LAYER Metal3 ;
        RECT  1899.6 1790.26 1900 1790.66 ;
    END
  END window_pc_o[23]
  PIN window_pc_o[24]
    DIRECTION OUTPUT ;
    USE SIGNAL ;
    PORT
      LAYER Metal3 ;
        RECT  1899.6 1788.58 1900 1788.98 ;
    END
  END window_pc_o[24]
  PIN window_pc_o[25]
    DIRECTION OUTPUT ;
    USE SIGNAL ;
    PORT
      LAYER Metal3 ;
        RECT  1899.6 1786.9 1900 1787.3 ;
    END
  END window_pc_o[25]
  PIN window_pc_o[26]
    DIRECTION OUTPUT ;
    USE SIGNAL ;
    PORT
      LAYER Metal3 ;
        RECT  1899.6 1785.22 1900 1785.62 ;
    END
  END window_pc_o[26]
  PIN window_pc_o[27]
    DIRECTION OUTPUT ;
    USE SIGNAL ;
    PORT
      LAYER Metal3 ;
        RECT  1899.6 1783.54 1900 1783.94 ;
    END
  END window_pc_o[27]
  PIN window_pc_o[28]
    DIRECTION OUTPUT ;
    USE SIGNAL ;
    PORT
      LAYER Metal3 ;
        RECT  1899.6 1781.86 1900 1782.26 ;
    END
  END window_pc_o[28]
  PIN window_pc_o[29]
    DIRECTION OUTPUT ;
    USE SIGNAL ;
    PORT
      LAYER Metal3 ;
        RECT  1899.6 1780.18 1900 1780.58 ;
    END
  END window_pc_o[29]
  PIN window_pc_o[2]
    DIRECTION OUTPUT ;
    USE SIGNAL ;
    PORT
      LAYER Metal3 ;
        RECT  1899.6 1825.54 1900 1825.94 ;
    END
  END window_pc_o[2]
  PIN window_pc_o[30]
    DIRECTION OUTPUT ;
    USE SIGNAL ;
    PORT
      LAYER Metal3 ;
        RECT  1899.6 1778.5 1900 1778.9 ;
    END
  END window_pc_o[30]
  PIN window_pc_o[31]
    DIRECTION OUTPUT ;
    USE SIGNAL ;
    PORT
      LAYER Metal3 ;
        RECT  1899.6 1776.82 1900 1777.22 ;
    END
  END window_pc_o[31]
  PIN window_pc_o[3]
    DIRECTION OUTPUT ;
    USE SIGNAL ;
    PORT
      LAYER Metal3 ;
        RECT  1899.6 1823.86 1900 1824.26 ;
    END
  END window_pc_o[3]
  PIN window_pc_o[4]
    DIRECTION OUTPUT ;
    USE SIGNAL ;
    PORT
      LAYER Metal3 ;
        RECT  1899.6 1822.18 1900 1822.58 ;
    END
  END window_pc_o[4]
  PIN window_pc_o[5]
    DIRECTION OUTPUT ;
    USE SIGNAL ;
    PORT
      LAYER Metal3 ;
        RECT  1899.6 1820.5 1900 1820.9 ;
    END
  END window_pc_o[5]
  PIN window_pc_o[6]
    DIRECTION OUTPUT ;
    USE SIGNAL ;
    PORT
      LAYER Metal3 ;
        RECT  1899.6 1818.82 1900 1819.22 ;
    END
  END window_pc_o[6]
  PIN window_pc_o[7]
    DIRECTION OUTPUT ;
    USE SIGNAL ;
    PORT
      LAYER Metal3 ;
        RECT  1899.6 1817.14 1900 1817.54 ;
    END
  END window_pc_o[7]
  PIN window_pc_o[8]
    DIRECTION OUTPUT ;
    USE SIGNAL ;
    PORT
      LAYER Metal3 ;
        RECT  1899.6 1815.46 1900 1815.86 ;
    END
  END window_pc_o[8]
  PIN window_pc_o[9]
    DIRECTION OUTPUT ;
    USE SIGNAL ;
    PORT
      LAYER Metal3 ;
        RECT  1899.6 1813.78 1900 1814.18 ;
    END
  END window_pc_o[9]
  PIN VPWR
    DIRECTION INOUT ;
    USE POWER ;
    PORT
      LAYER TopMetal1 ;
        RECT  5.76 2174.12 1894.08 2176.12 ;
        RECT  5.76 2124.12 1894.08 2126.12 ;
        RECT  5.76 2074.12 1894.08 2076.12 ;
        RECT  5.76 2024.12 1894.08 2026.12 ;
        RECT  5.76 1974.12 1894.08 1976.12 ;
        RECT  5.76 1924.12 1894.08 1926.12 ;
        RECT  5.76 1874.12 1894.08 1876.12 ;
        RECT  5.76 1824.12 1894.08 1826.12 ;
        RECT  5.76 1774.12 1894.08 1776.12 ;
        RECT  5.76 1724.12 1894.08 1726.12 ;
        RECT  5.76 1674.12 1894.08 1676.12 ;
        RECT  5.76 1624.12 1894.08 1626.12 ;
        RECT  5.76 1574.12 1894.08 1576.12 ;
        RECT  5.76 1524.12 1894.08 1526.12 ;
        RECT  5.76 1474.12 1894.08 1476.12 ;
        RECT  5.76 1424.12 1894.08 1426.12 ;
        RECT  5.76 1374.12 1894.08 1376.12 ;
        RECT  5.76 1324.12 1894.08 1326.12 ;
        RECT  5.76 1274.12 1894.08 1276.12 ;
        RECT  5.76 1224.12 1894.08 1226.12 ;
        RECT  5.76 1174.12 1894.08 1176.12 ;
        RECT  5.76 1124.12 1894.08 1126.12 ;
        RECT  5.76 1074.12 1894.08 1076.12 ;
        RECT  5.76 1024.12 1894.08 1026.12 ;
        RECT  5.76 974.12 1894.08 976.12 ;
        RECT  5.76 924.12 1894.08 926.12 ;
        RECT  5.76 874.12 1894.08 876.12 ;
        RECT  5.76 824.12 1894.08 826.12 ;
        RECT  5.76 774.12 1894.08 776.12 ;
        RECT  5.76 724.12 1894.08 726.12 ;
        RECT  5.76 674.12 1894.08 676.12 ;
        RECT  5.76 624.12 1894.08 626.12 ;
        RECT  5.76 574.12 1894.08 576.12 ;
        RECT  5.76 524.12 1894.08 526.12 ;
        RECT  5.76 474.12 1894.08 476.12 ;
        RECT  5.76 424.12 1894.08 426.12 ;
        RECT  5.76 374.12 1894.08 376.12 ;
        RECT  5.76 324.12 1894.08 326.12 ;
        RECT  5.76 274.12 1894.08 276.12 ;
        RECT  5.76 224.12 1894.08 226.12 ;
        RECT  5.76 174.12 1894.08 176.12 ;
        RECT  5.76 124.12 1894.08 126.12 ;
        RECT  5.76 74.12 1894.08 76.12 ;
        RECT  5.76 24.12 1894.08 26.12 ;
      LAYER Metal4 ;
        RECT  1865.26 14.9 1866.26 2185.06 ;
        RECT  1815.26 1979.65 1816.26 2185.06 ;
        RECT  1815.26 14.9 1816.26 1739.4 ;
        RECT  1765.26 1979.89 1766.26 2185.06 ;
        RECT  1765.26 1710.25 1766.26 1739.16 ;
        RECT  1765.26 14.9 1766.26 1469.52 ;
        RECT  1715.26 1979.89 1716.26 2185.06 ;
        RECT  1715.26 1710.25 1716.26 1739.16 ;
        RECT  1715.26 14.9 1716.26 1469.52 ;
        RECT  1665.26 1979.65 1666.26 2185.06 ;
        RECT  1665.26 1710.01 1666.26 1739.4 ;
        RECT  1665.26 322.25 1666.26 1469.76 ;
        RECT  1665.26 14.9 1666.26 81.52 ;
        RECT  1615.26 1979.89 1616.26 2185.06 ;
        RECT  1615.26 1710.25 1616.26 1739.16 ;
        RECT  1615.26 1129.97 1616.26 1469.52 ;
        RECT  1615.26 714.2 1616.26 889.24 ;
        RECT  1615.26 322.25 1616.26 473.52 ;
        RECT  1615.26 14.9 1616.26 81.52 ;
        RECT  1565.26 1979.89 1566.26 2185.06 ;
        RECT  1565.26 1710.25 1566.26 1739.16 ;
        RECT  1565.26 1129.97 1566.26 1469.52 ;
        RECT  1565.26 714.2 1566.26 889.24 ;
        RECT  1565.26 322.01 1566.26 473.52 ;
        RECT  1565.26 14.9 1566.26 81.76 ;
        RECT  1515.26 1979.65 1516.26 2185.06 ;
        RECT  1515.26 1710.01 1516.26 1739.4 ;
        RECT  1515.26 1129.73 1516.26 1469.76 ;
        RECT  1515.26 714.01 1516.26 889.48 ;
        RECT  1515.26 322.25 1516.26 473.76 ;
        RECT  1515.26 14.9 1516.26 81.52 ;
        RECT  1465.26 1979.89 1466.26 2185.06 ;
        RECT  1465.26 1710.25 1466.26 1739.16 ;
        RECT  1465.26 1129.97 1466.26 1469.52 ;
        RECT  1465.26 714.2 1466.26 889.24 ;
        RECT  1465.26 322.25 1466.26 473.52 ;
        RECT  1465.26 14.9 1466.26 81.52 ;
        RECT  1415.26 1979.65 1416.26 2185.06 ;
        RECT  1415.26 1710.25 1416.26 1739.4 ;
        RECT  1415.26 1129.97 1416.26 1469.52 ;
        RECT  1415.26 714.2 1416.26 889.24 ;
        RECT  1415.26 322.01 1416.26 473.52 ;
        RECT  1415.26 14.9 1416.26 81.76 ;
        RECT  1365.26 1979.89 1366.26 2185.06 ;
        RECT  1365.26 1710.25 1366.26 1739.16 ;
        RECT  1365.26 1129.73 1366.26 1469.52 ;
        RECT  1365.26 714.01 1366.26 889.48 ;
        RECT  1365.26 322.25 1366.26 473.76 ;
        RECT  1365.26 14.9 1366.26 81.52 ;
        RECT  1315.26 1979.65 1316.26 2185.06 ;
        RECT  1315.26 1710.01 1316.26 1739.4 ;
        RECT  1315.26 1129.97 1316.26 1469.76 ;
        RECT  1315.26 714.2 1316.26 889.24 ;
        RECT  1315.26 322.25 1316.26 473.52 ;
        RECT  1315.26 14.9 1316.26 81.52 ;
        RECT  1265.26 1979.89 1266.26 2185.06 ;
        RECT  1265.26 1710.25 1266.26 1739.16 ;
        RECT  1265.26 1129.97 1266.26 1469.52 ;
        RECT  1265.26 714.2 1266.26 889.24 ;
        RECT  1265.26 322.25 1266.26 473.52 ;
        RECT  1265.26 14.9 1266.26 81.52 ;
        RECT  1215.26 1979.89 1216.26 2185.06 ;
        RECT  1215.26 1710.25 1216.26 1739.16 ;
        RECT  1215.26 1129.97 1216.26 1469.52 ;
        RECT  1215.26 714.2 1216.26 889.24 ;
        RECT  1215.26 322.01 1216.26 473.52 ;
        RECT  1215.26 14.9 1216.26 81.76 ;
        RECT  1165.26 1979.89 1166.26 2185.06 ;
        RECT  1165.26 1710.01 1166.26 1739.16 ;
        RECT  1165.26 1129.73 1166.26 1469.76 ;
        RECT  1165.26 714.01 1166.26 889.48 ;
        RECT  1165.26 322.25 1166.26 473.76 ;
        RECT  1165.26 14.9 1166.26 81.52 ;
        RECT  1115.26 1979.65 1116.26 2185.06 ;
        RECT  1115.26 1710.25 1116.26 1739.4 ;
        RECT  1115.26 1129.97 1116.26 1469.52 ;
        RECT  1115.26 714.2 1116.26 889.24 ;
        RECT  1115.26 322.25 1116.26 473.52 ;
        RECT  1115.26 14.9 1116.26 81.52 ;
        RECT  1065.26 1129.97 1066.26 2185.06 ;
        RECT  1065.26 714.2 1066.26 889.24 ;
        RECT  1065.26 322.01 1066.26 473.52 ;
        RECT  1065.26 14.9 1066.26 81.76 ;
        RECT  1015.26 1129.73 1016.26 2185.06 ;
        RECT  1015.26 714.01 1016.26 889.48 ;
        RECT  1015.26 322.25 1016.26 473.76 ;
        RECT  1015.26 14.9 1016.26 81.52 ;
        RECT  965.26 1129.97 966.26 2185.06 ;
        RECT  965.26 714.2 966.26 889.24 ;
        RECT  965.26 14.9 966.26 473.52 ;
        RECT  915.26 14.9 916.26 2185.06 ;
        RECT  865.26 14.9 866.26 2185.06 ;
        RECT  815.26 14.9 816.26 2185.06 ;
        RECT  765.26 14.9 766.26 2185.06 ;
        RECT  715.26 2160.25 716.26 2185.06 ;
        RECT  715.26 1786.25 716.26 1919.52 ;
        RECT  715.26 1500.25 716.26 1545.52 ;
        RECT  715.26 1118.25 716.26 1259.52 ;
        RECT  715.26 866.25 716.26 877.52 ;
        RECT  715.26 430.25 716.26 625.52 ;
        RECT  715.26 14.9 716.26 189.52 ;
        RECT  665.26 2160.25 666.26 2185.06 ;
        RECT  665.26 1786.25 666.26 1919.52 ;
        RECT  665.26 1500.25 666.26 1545.52 ;
        RECT  665.26 1118.25 666.26 1259.52 ;
        RECT  665.26 866.25 666.26 877.52 ;
        RECT  665.26 430.25 666.26 625.52 ;
        RECT  665.26 14.9 666.26 189.52 ;
        RECT  615.26 2160.01 616.26 2185.06 ;
        RECT  615.26 1786.01 616.26 1919.76 ;
        RECT  615.26 1500.01 616.26 1545.76 ;
        RECT  615.26 1118.01 616.26 1259.76 ;
        RECT  615.26 866.01 616.26 877.76 ;
        RECT  615.26 430.01 616.26 625.76 ;
        RECT  615.26 14.9 616.26 189.76 ;
        RECT  565.26 2160.25 566.26 2185.06 ;
        RECT  565.26 1786.25 566.26 1919.52 ;
        RECT  565.26 1500.25 566.26 1545.52 ;
        RECT  565.26 1118.25 566.26 1259.52 ;
        RECT  565.26 866.25 566.26 877.52 ;
        RECT  565.26 430.25 566.26 625.52 ;
        RECT  565.26 14.9 566.26 189.52 ;
        RECT  515.26 2160.25 516.26 2185.06 ;
        RECT  515.26 1786.25 516.26 1919.52 ;
        RECT  515.26 1500.25 516.26 1545.52 ;
        RECT  515.26 1118.25 516.26 1259.52 ;
        RECT  515.26 866.25 516.26 877.52 ;
        RECT  515.26 430.25 516.26 625.52 ;
        RECT  515.26 14.9 516.26 189.52 ;
        RECT  465.26 2160.01 466.26 2185.06 ;
        RECT  465.26 1786.01 466.26 1919.76 ;
        RECT  465.26 1500.01 466.26 1545.76 ;
        RECT  465.26 1118.01 466.26 1259.76 ;
        RECT  465.26 866.01 466.26 877.76 ;
        RECT  465.26 430.01 466.26 625.76 ;
        RECT  465.26 14.9 466.26 189.76 ;
        RECT  415.26 2160.25 416.26 2185.06 ;
        RECT  415.26 1786.25 416.26 1919.52 ;
        RECT  415.26 1500.25 416.26 1545.52 ;
        RECT  415.26 1118.25 416.26 1259.52 ;
        RECT  415.26 866.25 416.26 877.52 ;
        RECT  415.26 430.25 416.26 625.52 ;
        RECT  415.26 14.9 416.26 189.52 ;
        RECT  365.26 2160.25 366.26 2185.06 ;
        RECT  365.26 1786.25 366.26 1919.52 ;
        RECT  365.26 1500.25 366.26 1545.52 ;
        RECT  365.26 1118.25 366.26 1259.52 ;
        RECT  365.26 866.25 366.26 877.52 ;
        RECT  365.26 430.25 366.26 625.52 ;
        RECT  365.26 14.9 366.26 189.52 ;
        RECT  315.26 2160.25 316.26 2185.06 ;
        RECT  315.26 1786.25 316.26 1919.52 ;
        RECT  315.26 1500.25 316.26 1545.52 ;
        RECT  315.26 1118.25 316.26 1259.52 ;
        RECT  315.26 866.25 316.26 877.52 ;
        RECT  315.26 430.25 316.26 625.52 ;
        RECT  315.26 14.9 316.26 189.52 ;
        RECT  265.26 2160.01 266.26 2185.06 ;
        RECT  265.26 1786.01 266.26 1919.76 ;
        RECT  265.26 1500.01 266.26 1545.76 ;
        RECT  265.26 1118.01 266.26 1259.76 ;
        RECT  265.26 866.01 266.26 877.76 ;
        RECT  265.26 430.01 266.26 625.76 ;
        RECT  265.26 14.9 266.26 189.76 ;
        RECT  215.26 2160.25 216.26 2185.06 ;
        RECT  215.26 1786.25 216.26 1919.52 ;
        RECT  215.26 1500.25 216.26 1545.52 ;
        RECT  215.26 1118.25 216.26 1259.52 ;
        RECT  215.26 866.25 216.26 877.52 ;
        RECT  215.26 430.25 216.26 625.52 ;
        RECT  215.26 14.9 216.26 189.52 ;
        RECT  165.26 2160.25 166.26 2185.06 ;
        RECT  165.26 1786.25 166.26 1919.52 ;
        RECT  165.26 1500.25 166.26 1545.52 ;
        RECT  165.26 1118.25 166.26 1259.52 ;
        RECT  165.26 866.25 166.26 877.52 ;
        RECT  165.26 430.25 166.26 625.52 ;
        RECT  165.26 14.9 166.26 189.52 ;
        RECT  115.26 2160.01 116.26 2185.06 ;
        RECT  115.26 1786.01 116.26 1919.76 ;
        RECT  115.26 1500.01 116.26 1545.76 ;
        RECT  115.26 1118.01 116.26 1259.76 ;
        RECT  115.26 866.01 116.26 877.76 ;
        RECT  115.26 430.01 116.26 625.76 ;
        RECT  115.26 14.9 116.26 189.76 ;
        RECT  65.26 2160.25 66.26 2185.06 ;
        RECT  65.26 1786.25 66.26 1919.52 ;
        RECT  65.26 1500.25 66.26 1545.52 ;
        RECT  65.26 1118.25 66.26 1259.52 ;
        RECT  65.26 866.25 66.26 877.52 ;
        RECT  65.26 430.25 66.26 625.52 ;
        RECT  65.26 14.9 66.26 189.52 ;
        RECT  15.26 14.9 16.26 2185.06 ;
    END
  END VPWR
  PIN VGND
    DIRECTION INOUT ;
    USE GROUND ;
    PORT
      LAYER TopMetal1 ;
        RECT  18.13 868.425 769.39 870.065 ;
        RECT  5.76 2180.12 1894.08 2182.12 ;
        RECT  5.76 2130.12 1894.08 2132.12 ;
        RECT  5.76 2080.12 1894.08 2082.12 ;
        RECT  5.76 2030.12 1894.08 2032.12 ;
        RECT  5.76 1980.12 1894.08 1982.12 ;
        RECT  5.76 1930.12 1894.08 1932.12 ;
        RECT  5.76 1880.12 1894.08 1882.12 ;
        RECT  5.76 1830.12 1894.08 1832.12 ;
        RECT  5.76 1780.12 1894.08 1782.12 ;
        RECT  5.76 1730.12 1894.08 1732.12 ;
        RECT  5.76 1680.12 1894.08 1682.12 ;
        RECT  5.76 1630.12 1894.08 1632.12 ;
        RECT  5.76 1580.12 1894.08 1582.12 ;
        RECT  5.76 1530.12 1894.08 1532.12 ;
        RECT  5.76 1480.12 1894.08 1482.12 ;
        RECT  5.76 1430.12 1894.08 1432.12 ;
        RECT  5.76 1380.12 1894.08 1382.12 ;
        RECT  5.76 1330.12 1894.08 1332.12 ;
        RECT  5.76 1280.12 1894.08 1282.12 ;
        RECT  5.76 1230.12 1894.08 1232.12 ;
        RECT  5.76 1180.12 1894.08 1182.12 ;
        RECT  5.76 1130.12 1894.08 1132.12 ;
        RECT  5.76 1080.12 1894.08 1082.12 ;
        RECT  5.76 1030.12 1894.08 1032.12 ;
        RECT  5.76 980.12 1894.08 982.12 ;
        RECT  5.76 930.12 1894.08 932.12 ;
        RECT  5.76 880.12 1894.08 882.12 ;
        RECT  5.76 830.12 1894.08 832.12 ;
        RECT  5.76 780.12 1894.08 782.12 ;
        RECT  5.76 730.12 1894.08 732.12 ;
        RECT  5.76 680.12 1894.08 682.12 ;
        RECT  5.76 630.12 1894.08 632.12 ;
        RECT  5.76 580.12 1894.08 582.12 ;
        RECT  5.76 530.12 1894.08 532.12 ;
        RECT  5.76 480.12 1894.08 482.12 ;
        RECT  5.76 430.12 1894.08 432.12 ;
        RECT  5.76 380.12 1894.08 382.12 ;
        RECT  5.76 330.12 1894.08 332.12 ;
        RECT  5.76 280.12 1894.08 282.12 ;
        RECT  5.76 230.12 1894.08 232.12 ;
        RECT  5.76 180.12 1894.08 182.12 ;
        RECT  5.76 130.12 1894.08 132.12 ;
        RECT  5.76 80.12 1894.08 82.12 ;
        RECT  5.76 30.12 1894.08 32.12 ;
      LAYER Metal4 ;
        RECT  1868.26 14.9 1869.26 2185.06 ;
        RECT  1818.26 1979.65 1819.26 2185.06 ;
        RECT  1818.26 14.9 1819.26 1739.4 ;
        RECT  1768.26 1979.89 1769.26 2185.06 ;
        RECT  1768.26 1710.25 1769.26 1739.16 ;
        RECT  1768.26 14.9 1769.26 1469.52 ;
        RECT  1718.26 1979.65 1719.26 2185.06 ;
        RECT  1718.26 1710.01 1719.26 1739.4 ;
        RECT  1718.26 14.9 1719.26 1469.76 ;
        RECT  1668.26 1979.89 1669.26 2185.06 ;
        RECT  1668.26 1710.25 1669.26 1739.16 ;
        RECT  1668.26 322.25 1669.26 1469.52 ;
        RECT  1668.26 14.9 1669.26 81.52 ;
        RECT  1618.26 1979.89 1619.26 2185.06 ;
        RECT  1618.26 1710.25 1619.26 1739.16 ;
        RECT  1618.26 1129.97 1619.26 1469.52 ;
        RECT  1618.26 714.25 1619.26 889.24 ;
        RECT  1618.26 322.01 1619.26 473.52 ;
        RECT  1618.26 14.9 1619.26 81.76 ;
        RECT  1568.26 1979.65 1569.26 2185.06 ;
        RECT  1568.26 1710.01 1569.26 1739.4 ;
        RECT  1568.26 1129.73 1569.26 1469.76 ;
        RECT  1568.26 714.01 1569.26 889.48 ;
        RECT  1568.26 322.25 1569.26 473.76 ;
        RECT  1568.26 14.9 1569.26 81.52 ;
        RECT  1518.26 1979.65 1519.26 2185.06 ;
        RECT  1518.26 1710.25 1519.26 1739.4 ;
        RECT  1518.26 1129.97 1519.26 1469.52 ;
        RECT  1518.26 714.25 1519.26 889.24 ;
        RECT  1518.26 322.25 1519.26 473.52 ;
        RECT  1518.26 14.9 1519.26 81.52 ;
        RECT  1468.26 1979.89 1469.26 2185.06 ;
        RECT  1468.26 1710.25 1469.26 1739.16 ;
        RECT  1468.26 1129.97 1469.26 1469.52 ;
        RECT  1468.26 714.25 1469.26 889.24 ;
        RECT  1468.26 322.01 1469.26 473.52 ;
        RECT  1468.26 14.9 1469.26 81.76 ;
        RECT  1418.26 1979.65 1419.26 2185.06 ;
        RECT  1418.26 1710.25 1419.26 1739.4 ;
        RECT  1418.26 1129.73 1419.26 1469.52 ;
        RECT  1418.26 714.01 1419.26 889.48 ;
        RECT  1418.26 322.25 1419.26 473.76 ;
        RECT  1418.26 14.9 1419.26 81.52 ;
        RECT  1368.26 1979.65 1369.26 2185.06 ;
        RECT  1368.26 1710.01 1369.26 1739.4 ;
        RECT  1368.26 1129.97 1369.26 1469.76 ;
        RECT  1368.26 714.25 1369.26 889.24 ;
        RECT  1368.26 322.25 1369.26 473.52 ;
        RECT  1368.26 14.9 1369.26 81.52 ;
        RECT  1318.26 1979.89 1319.26 2185.06 ;
        RECT  1318.26 1710.25 1319.26 1739.16 ;
        RECT  1318.26 1129.97 1319.26 1469.52 ;
        RECT  1318.26 714.25 1319.26 889.24 ;
        RECT  1318.26 322.25 1319.26 473.52 ;
        RECT  1318.26 14.9 1319.26 81.52 ;
        RECT  1268.26 1979.89 1269.26 2185.06 ;
        RECT  1268.26 1710.25 1269.26 1739.16 ;
        RECT  1268.26 1129.97 1269.26 1469.52 ;
        RECT  1268.26 714.25 1269.26 889.24 ;
        RECT  1268.26 322.01 1269.26 473.52 ;
        RECT  1268.26 14.9 1269.26 81.76 ;
        RECT  1218.26 1979.89 1219.26 2185.06 ;
        RECT  1218.26 1710.01 1219.26 1739.16 ;
        RECT  1218.26 1129.73 1219.26 1469.76 ;
        RECT  1218.26 714.01 1219.26 889.48 ;
        RECT  1218.26 322.25 1219.26 473.76 ;
        RECT  1218.26 14.9 1219.26 81.52 ;
        RECT  1168.26 1979.89 1169.26 2185.06 ;
        RECT  1168.26 1710.25 1169.26 1739.16 ;
        RECT  1168.26 1129.97 1169.26 1469.52 ;
        RECT  1168.26 714.25 1169.26 889.24 ;
        RECT  1168.26 322.25 1169.26 473.52 ;
        RECT  1168.26 14.9 1169.26 81.52 ;
        RECT  1118.26 1979.65 1119.26 2185.06 ;
        RECT  1118.26 1710.25 1119.26 1739.4 ;
        RECT  1118.26 1129.97 1119.26 1469.52 ;
        RECT  1118.26 714.25 1119.26 889.24 ;
        RECT  1118.26 322.01 1119.26 473.52 ;
        RECT  1118.26 14.9 1119.26 81.76 ;
        RECT  1068.26 1129.73 1069.26 2185.06 ;
        RECT  1068.26 714.01 1069.26 889.48 ;
        RECT  1068.26 322.25 1069.26 473.76 ;
        RECT  1068.26 14.9 1069.26 81.52 ;
        RECT  1018.26 1129.97 1019.26 2185.06 ;
        RECT  1018.26 714.25 1019.26 889.24 ;
        RECT  1018.26 322.25 1019.26 473.52 ;
        RECT  1018.26 14.9 1019.26 81.52 ;
        RECT  968.26 1129.97 969.26 2185.06 ;
        RECT  968.26 714.25 969.26 889.24 ;
        RECT  968.26 14.9 969.26 473.52 ;
        RECT  918.26 14.9 919.26 2185.06 ;
        RECT  868.26 14.9 869.26 2185.06 ;
        RECT  818.26 14.9 819.26 2185.06 ;
        RECT  768.26 14.9 769.26 2185.06 ;
        RECT  718.26 2160.25 719.26 2185.06 ;
        RECT  718.26 1786.25 719.26 1919.52 ;
        RECT  718.26 1500.25 719.26 1545.52 ;
        RECT  718.26 1118.25 719.26 1259.52 ;
        RECT  718.26 866.25 719.26 877.52 ;
        RECT  718.26 430.12 719.26 625.52 ;
        RECT  718.26 14.9 719.26 189.52 ;
        RECT  668.26 2160.01 669.26 2185.06 ;
        RECT  668.26 1786.01 669.26 1919.76 ;
        RECT  668.26 1500.01 669.26 1545.76 ;
        RECT  668.26 1118.01 669.26 1259.76 ;
        RECT  668.26 866.01 669.26 877.76 ;
        RECT  668.26 430.01 669.26 625.76 ;
        RECT  668.26 14.9 669.26 189.76 ;
        RECT  618.26 2160.25 619.26 2185.06 ;
        RECT  618.26 1786.25 619.26 1919.52 ;
        RECT  618.26 1500.25 619.26 1545.52 ;
        RECT  618.26 1118.25 619.26 1259.52 ;
        RECT  618.26 866.25 619.26 877.52 ;
        RECT  618.26 430.12 619.26 625.52 ;
        RECT  618.26 14.9 619.26 189.52 ;
        RECT  568.26 2160.25 569.26 2185.06 ;
        RECT  568.26 1786.25 569.26 1919.52 ;
        RECT  568.26 1500.25 569.26 1545.52 ;
        RECT  568.26 1118.25 569.26 1259.52 ;
        RECT  568.26 866.25 569.26 877.52 ;
        RECT  568.26 430.12 569.26 625.52 ;
        RECT  568.26 14.9 569.26 189.52 ;
        RECT  518.26 2160.01 519.26 2185.06 ;
        RECT  518.26 1786.01 519.26 1919.76 ;
        RECT  518.26 1500.01 519.26 1545.76 ;
        RECT  518.26 1118.01 519.26 1259.76 ;
        RECT  518.26 866.01 519.26 877.76 ;
        RECT  518.26 430.01 519.26 625.76 ;
        RECT  518.26 14.9 519.26 189.76 ;
        RECT  468.26 2160.25 469.26 2185.06 ;
        RECT  468.26 1786.25 469.26 1919.52 ;
        RECT  468.26 1500.25 469.26 1545.52 ;
        RECT  468.26 1118.25 469.26 1259.52 ;
        RECT  468.26 866.25 469.26 877.52 ;
        RECT  468.26 430.12 469.26 625.52 ;
        RECT  468.26 14.9 469.26 189.52 ;
        RECT  418.26 2160.25 419.26 2185.06 ;
        RECT  418.26 1786.25 419.26 1919.52 ;
        RECT  418.26 1500.25 419.26 1545.52 ;
        RECT  418.26 1118.25 419.26 1259.52 ;
        RECT  418.26 866.25 419.26 877.52 ;
        RECT  418.26 430.12 419.26 625.52 ;
        RECT  418.26 14.9 419.26 189.52 ;
        RECT  368.26 2160.25 369.26 2185.06 ;
        RECT  368.26 1786.25 369.26 1919.52 ;
        RECT  368.26 1500.25 369.26 1545.52 ;
        RECT  368.26 1118.25 369.26 1259.52 ;
        RECT  368.26 866.25 369.26 877.52 ;
        RECT  368.26 430.12 369.26 625.52 ;
        RECT  368.26 14.9 369.26 189.52 ;
        RECT  318.26 2160.01 319.26 2185.06 ;
        RECT  318.26 1786.01 319.26 1919.76 ;
        RECT  318.26 1500.01 319.26 1545.76 ;
        RECT  318.26 1118.01 319.26 1259.76 ;
        RECT  318.26 866.01 319.26 877.76 ;
        RECT  318.26 430.01 319.26 625.76 ;
        RECT  318.26 14.9 319.26 189.76 ;
        RECT  268.26 2160.25 269.26 2185.06 ;
        RECT  268.26 1786.25 269.26 1919.52 ;
        RECT  268.26 1500.25 269.26 1545.52 ;
        RECT  268.26 1118.25 269.26 1259.52 ;
        RECT  268.26 866.25 269.26 877.52 ;
        RECT  268.26 430.12 269.26 625.52 ;
        RECT  268.26 14.9 269.26 189.52 ;
        RECT  218.26 2160.25 219.26 2185.06 ;
        RECT  218.26 1786.25 219.26 1919.52 ;
        RECT  218.26 1500.25 219.26 1545.52 ;
        RECT  218.26 1118.25 219.26 1259.52 ;
        RECT  218.26 866.25 219.26 877.52 ;
        RECT  218.26 430.12 219.26 625.52 ;
        RECT  218.26 14.9 219.26 189.52 ;
        RECT  168.26 2160.01 169.26 2185.06 ;
        RECT  168.26 1786.01 169.26 1919.76 ;
        RECT  168.26 1500.01 169.26 1545.76 ;
        RECT  168.26 1118.01 169.26 1259.76 ;
        RECT  168.26 866.01 169.26 877.76 ;
        RECT  168.26 430.01 169.26 625.76 ;
        RECT  168.26 14.9 169.26 189.76 ;
        RECT  118.26 2160.25 119.26 2185.06 ;
        RECT  118.26 1786.25 119.26 1919.52 ;
        RECT  118.26 1500.25 119.26 1545.52 ;
        RECT  118.26 1118.25 119.26 1259.52 ;
        RECT  118.26 866.25 119.26 877.52 ;
        RECT  118.26 430.12 119.26 625.52 ;
        RECT  118.26 14.9 119.26 189.52 ;
        RECT  68.26 2160.25 69.26 2185.06 ;
        RECT  68.26 1786.25 69.26 1919.52 ;
        RECT  68.26 1500.25 69.26 1545.52 ;
        RECT  68.26 1118.25 69.26 1259.52 ;
        RECT  68.26 866.25 69.26 877.52 ;
        RECT  68.26 430.12 69.26 625.52 ;
        RECT  68.26 14.9 69.26 189.52 ;
        RECT  18.26 14.9 19.26 2185.06 ;
    END
  END VGND
  OBS
    LAYER Metal1 ;
     RECT  5.76 14.9 39.84 2185.06 ;
     RECT  39.84 430.7 49.451 623.92 ;
     RECT  39.84 1118.66 49.591 1258.96 ;
     RECT  49.451 419.387 50 623.92 ;
     RECT  49.557 634.274 50 638.494 ;
     RECT  49.591 1118.66 50 1271.778 ;
     RECT  39.84 1927.692 50 1931.912 ;
     RECT  50 1556 50.161 1775.77 ;
     RECT  39.84 1787.72 50.161 1916.68 ;
     RECT  50 888 50.368 1107.77 ;
     RECT  50 1118.66 50.368 1489.77 ;
     RECT  50 1927.692 50.483 2149.77 ;
     RECT  50 634.274 51.058 855.77 ;
     RECT  50.483 1927.548 56.122 2149.77 ;
     RECT  56.122 1926.605 57.963 2149.77 ;
     RECT  50 200 58.142 623.92 ;
     RECT  51.058 633.999 58.142 855.77 ;
     RECT  57.963 1926.482 58.574 2149.77 ;
     RECT  58.574 1926.439 59.205 2149.77 ;
     RECT  59.205 1926.384 64.202 2149.77 ;
     RECT  50.161 1556 65.946 1916.68 ;
     RECT  64.202 1926.338 65.946 2149.77 ;
     RECT  65.946 1556 108.835 2149.77 ;
     RECT  108.835 1556 119.411 1916.68 ;
     RECT  108.835 1926.973 119.411 2149.77 ;
     RECT  119.411 1556 156.878 2149.77 ;
     RECT  156.878 1926.626 160.48 2149.77 ;
     RECT  156.878 1556 171.33 1916.922 ;
     RECT  160.48 1926.656 171.33 2149.77 ;
     RECT  171.33 1556 179.767 2149.77 ;
     RECT  179.767 1556 190.341 1916.68 ;
     RECT  179.767 1930 190.341 2149.77 ;
     RECT  190.341 1556 196.728 2149.77 ;
     RECT  196.728 1556 207.973 1916.68 ;
     RECT  196.728 1930 207.973 2149.77 ;
     RECT  207.973 1556 209.893 2149.77 ;
     RECT  50.368 888 214.465 1489.77 ;
     RECT  214.465 888 224.115 1260.31 ;
     RECT  214.465 1270 224.115 1489.77 ;
     RECT  209.893 1556 225.372 1916.68 ;
     RECT  209.893 1930 225.372 2149.77 ;
     RECT  225.372 1556 227.612 2149.77 ;
     RECT  227.612 1785.584 231.953 2149.77 ;
     RECT  58.142 200 239.571 855.77 ;
     RECT  227.612 1556 243.465 1775.77 ;
     RECT  231.953 1785.584 243.465 1917.486 ;
     RECT  243.465 1556 243.486 1917.486 ;
     RECT  231.953 1930 243.486 2149.77 ;
     RECT  224.115 888 245.097 1489.77 ;
     RECT  243.486 1556 245.385 2149.77 ;
     RECT  245.385 1786.915 245.406 2149.77 ;
     RECT  239.571 200 254.05 624.436 ;
     RECT  239.571 636 254.05 855.77 ;
     RECT  245.406 1786.915 256.044 1916.68 ;
     RECT  254.05 200 256.507 855.77 ;
     RECT  256.044 1786.941 256.559 1916.68 ;
     RECT  256.507 200 257.046 626.322 ;
     RECT  256.559 1786.964 257.075 1916.68 ;
     RECT  257.075 1787.258 260.797 1916.68 ;
     RECT  245.406 1930 260.797 2149.77 ;
     RECT  245.097 888 261.026 1260.357 ;
     RECT  245.097 1270 261.026 1489.77 ;
     RECT  260.797 1787.258 261.572 2149.77 ;
     RECT  257.046 200 261.642 624.336 ;
     RECT  261.026 888 261.674 1489.77 ;
     RECT  261.572 1787.552 262.717 2149.77 ;
     RECT  261.674 1117.615 262.946 1489.77 ;
     RECT  262.946 1117.615 263.121 1260.06 ;
     RECT  262.717 1787.552 266.202 1916.68 ;
     RECT  263.121 1117.648 266.221 1260.06 ;
     RECT  261.642 200 267.337 624.083 ;
     RECT  266.221 1117.709 267.583 1260.06 ;
     RECT  266.202 1787.595 267.586 1916.68 ;
     RECT  267.337 429.592 271.784 624.083 ;
     RECT  271.784 429.592 272.311 625.083 ;
     RECT  272.311 429.592 273.737 625.19 ;
     RECT  267.583 1117.943 274.023 1260.06 ;
     RECT  273.737 429.644 274.231 625.19 ;
     RECT  274.231 429.644 274.261 625.127 ;
     RECT  274.023 1117.97 274.416 1260.06 ;
     RECT  274.416 1117.97 274.55 1259.779 ;
     RECT  274.261 429.689 274.779 625.127 ;
     RECT  274.55 1118.022 275.059 1259.779 ;
     RECT  267.586 1787.72 278.674 1916.68 ;
     RECT  262.717 1930 278.674 2149.77 ;
     RECT  274.779 429.817 279.193 625.127 ;
     RECT  279.193 429.938 280.58 625.127 ;
     RECT  278.674 1787.72 280.594 2149.77 ;
     RECT  275.059 1118.118 280.731 1259.779 ;
     RECT  280.58 429.938 283.66 623.92 ;
     RECT  280.731 1118.118 283.766 1259.287 ;
     RECT  283.66 430.09 285.002 623.92 ;
     RECT  283.766 1118.118 285.13 1258.98 ;
     RECT  285.13 1118.118 289.415 1258.96 ;
     RECT  289.415 1117.783 289.927 1258.96 ;
     RECT  280.594 1787.72 290.155 1916.68 ;
     RECT  289.927 1117.756 290.443 1258.96 ;
     RECT  290.443 1117.733 292.363 1258.96 ;
     RECT  290.155 1787.655 294.938 1916.68 ;
     RECT  294.938 1787.134 296.342 1916.68 ;
     RECT  280.594 1930 296.342 2149.77 ;
     RECT  285.002 430.7 296.38 623.92 ;
     RECT  292.363 1117.956 296.814 1258.96 ;
     RECT  296.342 1787.134 296.858 2149.77 ;
     RECT  296.858 1787.537 298.262 2149.77 ;
     RECT  296.38 430.7 298.3 625.527 ;
     RECT  296.814 1118.424 301.471 1258.96 ;
     RECT  298.262 1787.537 301.536 1916.68 ;
     RECT  301.471 1118.542 302.876 1258.96 ;
     RECT  301.536 1787.715 302.887 1916.68 ;
     RECT  298.3 430.7 314.058 623.92 ;
     RECT  314.058 430.7 315.978 624.831 ;
     RECT  302.876 1118.66 317.478 1258.96 ;
     RECT  317.478 1118.537 319.398 1258.96 ;
     RECT  319.398 1118.583 320.762 1258.96 ;
     RECT  320.762 1118.66 330.839 1258.96 ;
     RECT  315.978 430.7 330.963 623.92 ;
     RECT  330.963 430.452 330.988 623.92 ;
     RECT  330.839 1118.199 331.254 1258.96 ;
     RECT  330.988 430.452 332.448 624.07 ;
     RECT  332.448 430.113 332.466 624.07 ;
     RECT  331.254 1118.199 332.759 1259.417 ;
     RECT  332.759 1118.289 332.806 1259.417 ;
     RECT  332.806 1118.289 334.267 1259.766 ;
     RECT  332.466 430.113 334.368 625.02 ;
     RECT  334.368 430.7 334.386 625.02 ;
     RECT  334.267 1118.66 334.726 1259.766 ;
     RECT  302.887 1787.72 354.845 1916.68 ;
     RECT  354.845 1787.72 356.765 1916.992 ;
     RECT  334.726 1118.66 424.102 1258.96 ;
     RECT  424.102 1118.226 426.022 1258.96 ;
     RECT  356.765 1787.72 427.816 1916.68 ;
     RECT  334.386 430.7 427.926 623.92 ;
     RECT  427.816 1787.72 429.736 1917.261 ;
     RECT  427.926 430.7 429.846 624.611 ;
     RECT  426.022 1118.327 430.439 1258.96 ;
     RECT  429.846 430.7 450.131 623.92 ;
     RECT  450.131 430.7 452.051 624.312 ;
     RECT  430.439 1118.66 483.405 1258.96 ;
     RECT  429.736 1787.72 486.217 1916.68 ;
     RECT  452.051 430.7 487.904 623.92 ;
     RECT  483.405 1118.622 488.027 1258.96 ;
     RECT  486.217 1787.72 488.137 1918.067 ;
     RECT  487.904 430.7 489.824 624.653 ;
     RECT  488.027 1118.246 489.947 1258.96 ;
     RECT  489.947 1118.346 499.69 1258.96 ;
     RECT  489.824 430.7 499.764 623.92 ;
     RECT  499.69 1117.81 501.052 1258.96 ;
     RECT  499.764 430.343 501.122 623.92 ;
     RECT  501.052 1117.617 502.972 1258.96 ;
     RECT  488.137 1787.72 503.68 1916.68 ;
     RECT  298.262 1930 503.68 2149.77 ;
     RECT  501.122 430.254 505.573 623.92 ;
     RECT  256.507 636 505.573 855.77 ;
     RECT  503.68 1787.72 505.6 2149.77 ;
     RECT  505.6 1787.72 505.661 1916.68 ;
     RECT  505.573 430.254 505.763 855.77 ;
     RECT  505.763 429.782 507.493 855.77 ;
     RECT  502.972 1117.709 507.493 1258.96 ;
     RECT  507.493 429.782 507.683 625.22 ;
     RECT  505.661 1787.514 510.118 1916.68 ;
     RECT  507.493 1118.109 517.24 1258.96 ;
     RECT  507.683 429.804 517.44 625.22 ;
     RECT  517.24 1117.859 518.611 1258.96 ;
     RECT  267.337 200 518.791 419.77 ;
     RECT  517.44 429.457 518.791 625.22 ;
     RECT  518.791 200 518.835 625.22 ;
     RECT  507.493 636 518.835 855.77 ;
     RECT  245.385 1556 521.624 1775.77 ;
     RECT  510.118 1787.3 521.624 1916.68 ;
     RECT  521.624 1556 521.918 1916.68 ;
     RECT  505.6 1930 521.918 2149.77 ;
     RECT  518.611 1117.802 523.21 1258.96 ;
     RECT  521.918 1556 523.544 2149.77 ;
     RECT  523.544 1787.72 523.838 2149.77 ;
     RECT  518.835 200 525.446 855.77 ;
     RECT  261.674 888 527.713 1107.77 ;
     RECT  523.21 1117.758 527.713 1258.96 ;
     RECT  523.544 1556 538.975 1775.77 ;
     RECT  523.838 1787.72 538.975 1916.68 ;
     RECT  538.975 1556 539.485 1916.68 ;
     RECT  523.838 1930 539.485 2149.77 ;
     RECT  525.446 200 540.847 623.92 ;
     RECT  525.446 636 540.847 855.77 ;
     RECT  539.485 1556 540.895 2149.77 ;
     RECT  540.895 1785.747 541.405 2149.77 ;
     RECT  540.895 1556 552.675 1775.77 ;
     RECT  541.405 1785.747 552.675 1916.68 ;
     RECT  527.713 888 556.94 1258.96 ;
     RECT  262.946 1270 556.94 1489.77 ;
     RECT  552.675 1556 556.996 1916.68 ;
     RECT  541.405 1930 556.996 2149.77 ;
     RECT  556.94 888 558.86 1489.77 ;
     RECT  556.996 1556 558.916 2149.77 ;
     RECT  558.916 1556 560.296 1916.738 ;
     RECT  540.847 200 560.75 855.77 ;
     RECT  560.75 200 570.542 623.92 ;
     RECT  560.75 636 570.542 855.77 ;
     RECT  560.296 1556 574.695 1916.68 ;
     RECT  558.916 1930 574.695 2149.77 ;
     RECT  558.86 888 574.928 1258.96 ;
     RECT  558.86 1270 574.928 1489.77 ;
     RECT  574.695 1556 576.615 2149.77 ;
     RECT  570.542 200 576.788 855.77 ;
     RECT  574.928 888 576.848 1489.77 ;
     RECT  576.615 1556 582.27 1918.453 ;
     RECT  582.27 1556 582.786 1917.277 ;
     RECT  576.788 200 587.982 623.92 ;
     RECT  576.788 636 587.982 855.77 ;
     RECT  582.786 1556 592.432 1916.68 ;
     RECT  576.615 1930 592.432 2149.77 ;
     RECT  592.432 1556 594.352 2149.77 ;
     RECT  594.352 1556 595.428 1918.782 ;
     RECT  595.428 1556 605.994 1916.68 ;
     RECT  587.982 200 609.757 855.77 ;
     RECT  605.994 1556 609.957 1917.607 ;
     RECT  594.352 1930 609.957 2149.77 ;
     RECT  576.848 888 610.137 1258.96 ;
     RECT  576.848 1270 610.137 1489.77 ;
     RECT  609.957 1556 611.877 2149.77 ;
     RECT  609.757 200 612.056 625.317 ;
     RECT  610.137 888 612.057 1489.77 ;
     RECT  612.056 200 623.353 624.73 ;
     RECT  609.757 636 623.353 855.77 ;
     RECT  611.877 1556 627.135 1916.68 ;
     RECT  611.877 1930 627.135 2149.77 ;
     RECT  612.057 888 627.733 1258.96 ;
     RECT  612.057 1270 627.733 1489.77 ;
     RECT  627.733 888 629.653 1489.77 ;
     RECT  623.353 200 637.134 855.77 ;
     RECT  629.653 888 645.424 1258.96 ;
     RECT  629.653 1270 645.424 1489.77 ;
     RECT  627.135 1556 647.006 2149.77 ;
     RECT  637.134 200 647.183 623.92 ;
     RECT  637.134 636 647.183 855.77 ;
     RECT  645.424 888 647.344 1489.77 ;
     RECT  647.183 200 649.103 855.77 ;
     RECT  647.006 1556 658.103 1916.792 ;
     RECT  647.006 1930 658.103 2149.77 ;
     RECT  649.103 200 659.206 623.92 ;
     RECT  649.103 636 659.206 855.77 ;
     RECT  659.206 200 662.667 855.77 ;
     RECT  647.344 888 662.876 1258.96 ;
     RECT  647.344 1270 662.876 1489.77 ;
     RECT  662.876 888 664.796 1489.77 ;
     RECT  658.103 1556 665.491 2149.77 ;
     RECT  665.491 1556 680.543 1916.68 ;
     RECT  665.491 1930 680.543 2149.77 ;
     RECT  664.796 888 680.99 1258.96 ;
     RECT  664.796 1270 680.99 1489.77 ;
     RECT  662.667 200 681.182 623.92 ;
     RECT  662.667 636 681.182 855.77 ;
     RECT  680.543 1556 682.463 2149.77 ;
     RECT  680.99 888 682.91 1489.77 ;
     RECT  681.182 200 683.102 855.77 ;
     RECT  682.463 1926.621 683.95 2149.77 ;
     RECT  682.463 1556 689.073 1916.99 ;
     RECT  683.102 200 694.523 623.92 ;
     RECT  683.102 636 694.523 855.77 ;
     RECT  683.95 1930 695.09 2149.77 ;
     RECT  694.523 200 698.045 855.77 ;
     RECT  682.91 888 698.607 1258.96 ;
     RECT  689.073 1556 698.883 1916.68 ;
     RECT  695.09 1927.612 698.883 2149.77 ;
     RECT  698.607 888 700.527 1259.086 ;
     RECT  698.883 1556 700.803 2149.77 ;
     RECT  698.045 636 711.924 855.77 ;
     RECT  700.527 888 714.448 1258.96 ;
     RECT  682.91 1270 714.448 1489.77 ;
     RECT  700.803 1930 716.316 2149.77 ;
     RECT  698.045 200 716.371 623.92 ;
     RECT  711.924 633.545 716.371 855.77 ;
     RECT  716.316 1926.795 718.236 2149.77 ;
     RECT  714.448 888 722.123 1489.77 ;
     RECT  716.371 200 726.991 855.77 ;
     RECT  700.803 1556 727.407 1916.68 ;
     RECT  727.407 1556 729.327 1920.07 ;
     RECT  39.84 1500.44 729.677 1542.46 ;
     RECT  722.123 1270 732.552 1489.77 ;
     RECT  729.677 1500.44 732.552 1542.706 ;
     RECT  726.991 634.744 733.66 855.77 ;
     RECT  722.123 888 734.341 1260.306 ;
     RECT  732.552 1270 734.341 1542.706 ;
     RECT  729.327 1556 734.436 1916.68 ;
     RECT  734.341 888 734.681 1542.706 ;
     RECT  726.991 200 734.756 623.92 ;
     RECT  733.66 634.808 735.448 855.77 ;
     RECT  734.756 200 735.49 419.77 ;
     RECT  735.448 636 735.49 855.77 ;
     RECT  734.681 888 735.49 1107.77 ;
     RECT  734.681 1118.66 735.49 1542.706 ;
     RECT  734.436 1556 735.49 1775.77 ;
     RECT  718.236 1930 735.49 2149.77 ;
     RECT  735.49 1118.66 736.261 1269.623 ;
     RECT  734.436 1787.72 740.466 1916.68 ;
     RECT  740.466 1787.72 744.915 1917.274 ;
     RECT  735.49 1675.772 745.229 1679.992 ;
     RECT  744.915 1784.871 745.298 1917.274 ;
     RECT  735.49 1325.09 745.323 1329.31 ;
     RECT  735.49 1297.515 745.376 1301.735 ;
     RECT  735.49 1632.266 745.395 1636.486 ;
     RECT  745.174 1934.978 745.396 1939.198 ;
     RECT  745.323 1324.013 745.47 1329.31 ;
     RECT  745.269 1448.519 745.494 1452.739 ;
     RECT  745.306 1718.337 745.507 1722.557 ;
     RECT  735.49 1693.361 745.536 1697.581 ;
     RECT  735.49 1498.583 745.739 1542.706 ;
     RECT  735.49 1660.48 745.748 1664.7 ;
     RECT  745.379 1392.735 745.796 1396.955 ;
     RECT  745.26 1770.079 745.814 1774.299 ;
     RECT  735.49 1604.246 745.855 1610.156 ;
     RECT  745.739 1498.583 745.856 1550.487 ;
     RECT  735.49 1352.033 745.898 1357.439 ;
     RECT  745.796 1378.981 745.898 1396.955 ;
     RECT  39.84 14.9 745.92 189.22 ;
     RECT  734.756 430.7 745.92 623.92 ;
     RECT  39.84 869.18 745.92 877.18 ;
     RECT  736.261 1118.66 745.92 1267.697 ;
     RECT  745.376 1296.446 745.92 1301.735 ;
     RECT  745.47 1324.013 745.92 1341.883 ;
     RECT  745.898 1352.033 745.92 1396.955 ;
     RECT  745.494 1447.899 745.92 1452.739 ;
     RECT  745.856 1490.556 745.92 1550.487 ;
     RECT  735.49 1576.726 745.92 1580.946 ;
     RECT  745.855 1594.423 745.92 1610.156 ;
     RECT  745.395 1632.266 745.92 1649.661 ;
     RECT  745.748 1659.563 745.92 1664.7 ;
     RECT  745.229 1675.214 745.92 1679.992 ;
     RECT  745.536 1692.695 745.92 1697.581 ;
     RECT  745.507 1718.337 745.92 1736.072 ;
     RECT  745.435 1746.511 745.92 1750.731 ;
     RECT  745.814 1769.266 745.92 1774.299 ;
     RECT  745.298 1784.563 745.92 1917.274 ;
     RECT  745.396 1934.361 745.92 1939.198 ;
     RECT  39.84 2161.94 745.92 2185.06 ;
     RECT  745.92 14.9 939.84 2185.06 ;
     RECT  939.84 1101.106 940.065 2185.06 ;
     RECT  939.84 14.9 949.75 472.72 ;
     RECT  949.75 14.9 950 486.526 ;
     RECT  939.84 1055.949 950 1060.169 ;
     RECT  939.84 1071.744 950 1075.964 ;
     RECT  939.84 1086.345 950 1090.565 ;
     RECT  940.065 1101.106 950 1105.326 ;
     RECT  940.065 1121.56 950 2185.06 ;
     RECT  950 14.9 989.76 703.77 ;
     RECT  989.76 324.86 999.704 703.77 ;
     RECT  999.704 311.99 1000 703.77 ;
     RECT  1000 92 1039.258 703.77 ;
     RECT  1039.258 92 1053.123 473.739 ;
     RECT  1053.123 92 1054.498 474.082 ;
     RECT  1039.258 484 1054.498 703.77 ;
     RECT  1054.498 92 1061.056 703.77 ;
     RECT  1061.056 92 1072.276 472.92 ;
     RECT  1061.056 484 1072.276 703.77 ;
     RECT  1072.276 92 1078.688 703.77 ;
     RECT  1078.688 92 1088.843 472.812 ;
     RECT  950 899.72 1089.6 2185.06 ;
     RECT  1089.6 1575.054 1089.626 1607.562 ;
     RECT  1089.6 1529.552 1089.686 1554.168 ;
     RECT  1089.6 1491.001 1089.766 1498.266 ;
     RECT  1089.626 1575.054 1089.806 1589.337 ;
     RECT  1089.6 1508.225 1089.914 1512.445 ;
     RECT  1088.843 92 1089.954 473.481 ;
     RECT  1078.688 484 1089.954 703.77 ;
     RECT  1089.686 1529.552 1090.005 1544.603 ;
     RECT  1089.954 92 1096.612 703.77 ;
     RECT  1089.766 1491.001 1100 1495.221 ;
     RECT  1090.005 1529.552 1100 1533.772 ;
     RECT  1089.806 1575.054 1100 1579.274 ;
     RECT  1089.626 1603.342 1100 1607.562 ;
     RECT  1089.6 1622.726 1100 1636.69 ;
     RECT  1089.6 1654.139 1100 1690.593 ;
     RECT  1100 1480 1100.199 1699.77 ;
     RECT  1100.199 1477.89 1101.874 1699.77 ;
     RECT  1096.612 92 1106.752 473.191 ;
     RECT  1096.612 484 1106.752 703.77 ;
     RECT  1101.874 1477.579 1108.643 1699.77 ;
     RECT  1108.643 1477.079 1109.229 1699.77 ;
     RECT  1109.229 1476.99 1109.788 1699.77 ;
     RECT  1106.752 92 1109.997 703.77 ;
     RECT  1089.6 1712.12 1114.56 2185.06 ;
     RECT  1109.788 1476.948 1114.584 1699.77 ;
     RECT  1114.56 1712.12 1114.749 1753.489 ;
     RECT  1114.56 1963.34 1114.768 1967.56 ;
     RECT  1114.56 1885.036 1115.161 1889.256 ;
     RECT  1089.6 899.72 1117.058 1466.86 ;
     RECT  1114.584 1476.715 1117.058 1699.77 ;
     RECT  1114.749 1712.12 1117.084 1743.22 ;
     RECT  1109.997 92 1124.867 473.17 ;
     RECT  1114.56 1787.692 1125 1791.912 ;
     RECT  1114.56 1801.92 1125 1806.14 ;
     RECT  1114.56 1817.863 1125 1822.083 ;
     RECT  1114.56 1835.561 1125 1839.781 ;
     RECT  1114.56 1851.021 1125 1855.241 ;
     RECT  1114.56 1869.938 1125 1874.158 ;
     RECT  1114.56 1900.642 1125 1904.862 ;
     RECT  1114.56 1919.669 1125 1933.494 ;
     RECT  1124.867 321.772 1125.897 473.17 ;
     RECT  1109.997 484 1125.897 703.77 ;
     RECT  1125 1749.64 1125.939 1969.41 ;
     RECT  1114.56 1980.5 1125.939 2185.06 ;
     RECT  1125.897 321.772 1127.886 703.77 ;
     RECT  1127.886 321.905 1129.232 703.77 ;
     RECT  1124.867 92 1140.538 311.77 ;
     RECT  1129.232 322.008 1140.538 703.77 ;
     RECT  1140.538 92 1142.458 703.77 ;
     RECT  1142.458 323.104 1145.275 703.77 ;
     RECT  1125.939 1749.64 1145.64 2185.06 ;
     RECT  1142.458 92 1157.987 311.77 ;
     RECT  1145.275 323.104 1157.987 472.72 ;
     RECT  1157.987 92 1159.907 472.72 ;
     RECT  1159.907 322.275 1161.819 472.72 ;
     RECT  1145.64 1749.64 1163.292 1969.41 ;
     RECT  1145.64 1980.5 1163.292 2185.06 ;
     RECT  1161.819 322.275 1163.739 473.047 ;
     RECT  1163.292 1749.64 1165.212 2185.06 ;
     RECT  1165.212 1749.64 1175.294 1969.41 ;
     RECT  1165.212 1980.5 1175.294 2185.06 ;
     RECT  1159.907 92 1175.835 311.77 ;
     RECT  1163.739 322.275 1175.835 472.72 ;
     RECT  1175.835 92 1177.755 472.72 ;
     RECT  1177.755 324.069 1178.952 472.72 ;
     RECT  1178.952 324.069 1180.872 473.726 ;
     RECT  1180.872 324.069 1182.32 472.72 ;
     RECT  1175.294 1749.64 1188.891 2185.06 ;
     RECT  1117.058 899.72 1192.292 1699.77 ;
     RECT  1177.755 92 1193.275 311.77 ;
     RECT  1182.32 324.553 1193.275 472.72 ;
     RECT  1193.275 92 1195.195 472.72 ;
     RECT  1188.891 1749.64 1205.846 1969.41 ;
     RECT  1188.891 1980.5 1205.846 2185.06 ;
     RECT  1192.292 899.72 1206.728 1119.49 ;
     RECT  1192.292 1129.295 1206.728 1699.77 ;
     RECT  1195.195 92 1210.519 311.77 ;
     RECT  1195.195 324.86 1210.519 472.72 ;
     RECT  1210.519 92 1212.439 472.72 ;
     RECT  1206.728 899.72 1214.346 1699.77 ;
     RECT  1205.846 1749.64 1214.663 2185.06 ;
     RECT  1214.346 1129.172 1219.181 1699.77 ;
     RECT  1214.663 1980.176 1219.183 2185.06 ;
     RECT  1212.439 324.072 1222.082 472.72 ;
     RECT  1222.082 324.041 1222.623 472.72 ;
     RECT  1212.439 92 1228.567 311.77 ;
     RECT  1222.623 324.027 1228.567 472.72 ;
     RECT  1228.567 92 1230.487 472.72 ;
     RECT  1214.346 899.72 1231.264 1119.49 ;
     RECT  1219.181 1129.321 1231.264 1699.77 ;
     RECT  1214.663 1749.64 1232.933 1969.41 ;
     RECT  1219.183 1980.5 1232.933 2185.06 ;
     RECT  1230.487 324.782 1233.734 472.72 ;
     RECT  1231.264 899.72 1234.603 1699.77 ;
     RECT  1232.933 1749.64 1234.853 2185.06 ;
     RECT  1234.603 1130 1236.537 1699.77 ;
     RECT  1233.734 324.86 1246.523 472.72 ;
     RECT  1246.523 323.328 1248.443 472.72 ;
     RECT  1117.084 1712.12 1250.393 1739.02 ;
     RECT  1236.537 1130 1251.65 1467.242 ;
     RECT  1236.537 1480 1251.65 1699.77 ;
     RECT  1248.443 324.538 1251.796 472.72 ;
     RECT  1250.393 1711.328 1252.313 1739.02 ;
     RECT  1251.796 324.757 1253.262 472.72 ;
     RECT  1251.65 1130 1253.789 1699.77 ;
     RECT  1253.789 1129.179 1255.709 1699.77 ;
     RECT  1252.313 1712.12 1257.412 1739.02 ;
     RECT  1234.853 1749.64 1257.412 1969.41 ;
     RECT  1234.853 1980.5 1259.293 2185.06 ;
     RECT  1257.412 1712.12 1259.332 1969.41 ;
     RECT  1255.709 1129.318 1260.483 1699.77 ;
     RECT  1259.332 1749.64 1263.133 1969.41 ;
     RECT  1259.293 1979.199 1263.133 2185.06 ;
     RECT  1260.483 1129.472 1264.505 1699.77 ;
     RECT  1264.505 1129.777 1264.735 1699.77 ;
     RECT  1263.133 1749.64 1265.533 2185.06 ;
     RECT  1264.735 1129.777 1265.792 1466.86 ;
     RECT  1265.792 1129.928 1266.41 1466.86 ;
     RECT  1266.41 1130 1275.61 1466.86 ;
     RECT  1275.61 1130 1278.649 1470.165 ;
     RECT  1264.735 1480 1278.649 1699.77 ;
     RECT  1278.649 1130 1281.689 1699.77 ;
     RECT  1281.689 1130 1291.362 1466.86 ;
     RECT  1281.689 1480 1291.362 1699.77 ;
     RECT  1291.362 1130 1305.814 1699.77 ;
     RECT  1259.332 1712.12 1306.247 1739.02 ;
     RECT  1265.533 1749.64 1306.247 1969.41 ;
     RECT  1305.814 1130 1306.311 1470.06 ;
     RECT  1306.311 1130 1306.77 1469.361 ;
     RECT  1306.247 1712.12 1308.647 1969.41 ;
     RECT  1306.77 1130 1318.108 1468.382 ;
     RECT  1253.262 324.86 1327.818 472.72 ;
     RECT  1318.108 1130 1328.641 1466.86 ;
     RECT  1327.818 324.86 1329.738 472.935 ;
     RECT  1328.641 1130 1331.681 1467.033 ;
     RECT  1305.814 1480 1331.681 1699.77 ;
     RECT  1308.647 1712.12 1332.803 1739.02 ;
     RECT  1308.647 1749.64 1332.803 1969.41 ;
     RECT  1331.681 1130 1333.601 1699.77 ;
     RECT  1332.803 1712.12 1334.723 1969.41 ;
     RECT  1333.601 1130 1335.141 1469.673 ;
     RECT  1335.141 1130 1349.903 1466.86 ;
     RECT  1329.738 324.86 1350.282 472.72 ;
     RECT  1349.903 1129.487 1351.53 1466.86 ;
     RECT  1350.282 324.86 1352.202 473.037 ;
     RECT  1351.53 1129.446 1353.45 1466.86 ;
     RECT  1352.202 324.86 1353.89 472.994 ;
     RECT  1234.603 899.72 1366.173 1119.49 ;
     RECT  1353.45 1129.915 1366.173 1466.86 ;
     RECT  1366.173 899.72 1372.413 1466.86 ;
     RECT  1372.413 1129.915 1382.26 1466.86 ;
     RECT  1382.26 1129.642 1383.58 1466.86 ;
     RECT  1353.89 324.86 1386.265 472.72 ;
     RECT  1383.58 1129.591 1388.009 1466.86 ;
     RECT  1386.265 324.86 1388.185 473.481 ;
     RECT  1388.009 1129.442 1392.466 1466.86 ;
     RECT  1392.466 1129.175 1392.985 1466.86 ;
     RECT  1392.985 1129.143 1393.505 1466.86 ;
     RECT  1372.413 899.72 1399.662 1119.49 ;
     RECT  1393.505 1129.106 1399.662 1466.86 ;
     RECT  1388.185 324.86 1402.159 472.72 ;
     RECT  1402.159 324.843 1404.079 472.72 ;
     RECT  1404.079 324.86 1421.705 472.72 ;
     RECT  1145.275 484 1421.705 703.77 ;
     RECT  1421.705 324.86 1423.625 703.77 ;
     RECT  1423.625 324.86 1425.259 472.728 ;
     RECT  1425.259 324.86 1436.431 472.72 ;
     RECT  1436.431 324.387 1438.351 472.72 ;
     RECT  1438.351 324.86 1439.059 472.72 ;
     RECT  1423.625 484 1439.059 703.77 ;
     RECT  1439.059 324.86 1440.979 703.77 ;
     RECT  1440.979 324.86 1454.089 472.72 ;
     RECT  1440.979 484 1454.089 703.77 ;
     RECT  1230.487 92 1454.301 311.77 ;
     RECT  1454.089 324.86 1454.301 703.77 ;
     RECT  1454.301 92 1456.221 703.77 ;
     RECT  1456.221 324.45 1457.588 703.77 ;
     RECT  1457.588 324.86 1460.807 703.77 ;
     RECT  1456.221 92 1471.846 311.77 ;
     RECT  1460.807 324.86 1471.846 472.72 ;
     RECT  1471.846 92 1473.766 472.72 ;
     RECT  1473.766 324.86 1474.384 472.72 ;
     RECT  1460.807 484 1474.384 703.77 ;
     RECT  1474.384 324.86 1476.304 703.77 ;
     RECT  1473.766 92 1489.528 311.77 ;
     RECT  1476.304 324.86 1489.528 472.72 ;
     RECT  1489.528 92 1491.448 472.72 ;
     RECT  1491.448 324.567 1492.298 472.72 ;
     RECT  1476.304 484 1492.298 703.77 ;
     RECT  1492.298 324.567 1501.607 703.77 ;
     RECT  1491.448 92 1506.756 311.77 ;
     RECT  1501.607 324.567 1506.756 472.72 ;
     RECT  1506.756 92 1508.676 472.72 ;
     RECT  1508.676 92 1524.481 311.77 ;
     RECT  1508.676 322.937 1524.481 472.72 ;
     RECT  1524.481 92 1526.401 472.72 ;
     RECT  1526.401 322.826 1527.558 472.72 ;
     RECT  1501.607 484 1527.558 703.77 ;
     RECT  1399.662 899.72 1536.374 1466.86 ;
     RECT  1333.601 1480 1536.374 1699.77 ;
     RECT  1527.558 322.826 1538.077 703.77 ;
     RECT  1536.374 899.72 1538.294 1699.77 ;
     RECT  1526.401 92 1542.193 311.77 ;
     RECT  1538.077 322.749 1542.193 703.77 ;
     RECT  1542.193 92 1544.113 703.77 ;
     RECT  1544.113 321.529 1547.25 703.77 ;
     RECT  1547.25 321.529 1555.695 472.72 ;
     RECT  1544.113 92 1559.858 311.77 ;
     RECT  1555.695 321.4 1559.858 472.72 ;
     RECT  1559.858 92 1563.049 472.72 ;
     RECT  1547.25 484 1563.049 703.77 ;
     RECT  1563.049 92 1564.969 703.77 ;
     RECT  1538.294 899.72 1566.75 1466.86 ;
     RECT  1566.75 899.72 1568.069 1466.996 ;
     RECT  1564.969 92 1576.316 472.72 ;
     RECT  1564.969 484 1576.316 703.77 ;
     RECT  1568.069 899.72 1578.127 1467.983 ;
     RECT  1538.294 1480 1578.127 1699.77 ;
     RECT  1265.533 1980.5 1585.18 2185.06 ;
     RECT  1576.316 92 1585.259 703.77 ;
     RECT  1585.18 1979.434 1587.1 2185.06 ;
     RECT  1587.1 1979.485 1588.129 2185.06 ;
     RECT  1578.127 899.72 1591.714 1699.77 ;
     RECT  1585.259 92 1598.313 472.72 ;
     RECT  1585.259 484 1598.313 703.77 ;
     RECT  1598.313 92 1600.233 703.77 ;
     RECT  1600.233 92 1601.716 472.889 ;
     RECT  1591.714 899.72 1602.194 1466.86 ;
     RECT  1591.714 1480 1602.194 1699.77 ;
     RECT  1334.723 1749.64 1609.919 1969.41 ;
     RECT  1588.129 1980.5 1609.919 2185.06 ;
     RECT  1601.716 92 1612.217 472.72 ;
     RECT  1600.233 484 1612.217 703.77 ;
     RECT  1609.919 1749.64 1613.279 2185.06 ;
     RECT  1612.217 92 1620.734 703.77 ;
     RECT  1602.194 899.72 1626.752 1699.77 ;
     RECT  1626.752 899.72 1628.048 1467.994 ;
     RECT  1620.734 92 1630.883 472.72 ;
     RECT  1620.734 484 1630.883 703.77 ;
     RECT  1613.279 1749.64 1631.55 1969.41 ;
     RECT  1613.279 1979.38 1631.55 2185.06 ;
     RECT  1630.883 92 1634.164 703.77 ;
     RECT  1628.048 899.72 1634.887 1466.86 ;
     RECT  1634.164 484 1635.49 703.77 ;
     RECT  1634.887 899.72 1635.49 1119.49 ;
     RECT  1634.887 1130 1637.913 1466.86 ;
     RECT  1626.752 1480 1637.913 1699.77 ;
     RECT  1637.913 1130 1641.185 1699.77 ;
     RECT  1635.49 974.212 1645.748 978.432 ;
     RECT  1634.164 92 1645.92 472.72 ;
     RECT  939.84 714.2 1645.92 888.52 ;
     RECT  1645.748 961.961 1645.92 978.432 ;
     RECT  1635.49 1015.141 1645.92 1019.972 ;
     RECT  1645.507 1109.576 1645.92 1113.796 ;
     RECT  1641.185 1130 1645.92 1466.86 ;
     RECT  1645.92 92 1655.84 1466.86 ;
     RECT  1641.185 1480 1655.84 1699.77 ;
     RECT  1655.84 92 1664.512 1699.77 ;
     RECT  1664.512 92 1677.982 1466.86 ;
     RECT  1677.982 92 1679.261 1468.538 ;
     RECT  1664.512 1480 1679.261 1699.77 ;
     RECT  1679.261 92 1681.181 1699.77 ;
     RECT  1681.181 92 1684.427 1466.86 ;
     RECT  1684.427 92 1685.49 311.77 ;
     RECT  1684.427 324.86 1691.69 1466.86 ;
     RECT  1681.181 1480 1691.69 1699.77 ;
     RECT  989.76 14.9 1695.84 79.6 ;
     RECT  1691.69 324.86 1695.84 1699.77 ;
     RECT  1695.84 14.9 1698.544 1699.77 ;
     RECT  1698.544 14.9 1708.489 1466.91 ;
     RECT  1698.544 1480 1708.489 1699.77 ;
     RECT  1708.489 14.9 1750.22 1699.77 ;
     RECT  1750.22 1477.498 1752.113 1699.77 ;
     RECT  1750.22 14.9 1764.715 1467.749 ;
     RECT  1752.113 1480 1764.715 1699.77 ;
     RECT  1764.715 14.9 1767.102 1699.77 ;
     RECT  1767.102 1478.14 1778.742 1699.77 ;
     RECT  1767.102 14.9 1779.426 1466.86 ;
     RECT  1779.426 14.9 1780.272 1466.926 ;
     RECT  1780.272 14.9 1782.192 1469.529 ;
     RECT  1778.742 1480 1785.49 1699.77 ;
     RECT  1782.192 14.9 1793.247 1466.86 ;
     RECT  1793.247 14.9 1793.597 1467.873 ;
     RECT  1334.723 1712.12 1793.962 1739.02 ;
     RECT  1793.962 1701.972 1795.523 1739.02 ;
     RECT  1793.597 14.9 1795.68 1472.321 ;
     RECT  1785.49 1489.883 1795.68 1494.103 ;
     RECT  1785.49 1598.652 1795.68 1602.872 ;
     RECT  1785.49 1644.945 1795.68 1649.165 ;
     RECT  1795.523 1700.473 1795.68 1739.02 ;
     RECT  1631.55 1749.64 1809.221 2185.06 ;
     RECT  1809.221 1749.64 1810.49 1969.41 ;
     RECT  1795.68 14.9 1820.64 1739.02 ;
     RECT  1809.221 1980.5 1820.64 2185.06 ;
     RECT  1820.64 14.9 1894.08 2185.06 ;
     RECT  1894.08 1856.114 1894.39 1860.334 ;
     RECT  1894.08 1811.315 1894.547 1815.535 ;
     RECT  1894.08 1002.286 1894.728 1006.506 ;
     RECT  1894.08 1032.734 1894.728 1053.679 ;
     RECT  1894.08 1063.73 1894.728 1085.106 ;
    LAYER Metal2 ;
     RECT  18.455 14.975 19.065 18.755 ;
     RECT  68.455 14.975 69.065 18.755 ;
     RECT  118.455 14.975 119.065 18.755 ;
     RECT  168.455 14.975 169.065 18.755 ;
     RECT  218.455 14.975 219.065 18.755 ;
     RECT  268.455 14.975 269.065 18.755 ;
     RECT  318.455 14.975 319.065 18.755 ;
     RECT  368.455 14.975 369.065 18.755 ;
     RECT  418.455 14.975 419.065 18.755 ;
     RECT  468.455 14.975 469.065 18.755 ;
     RECT  518.455 14.975 519.065 18.755 ;
     RECT  568.455 14.975 569.065 18.755 ;
     RECT  618.455 14.975 619.065 18.755 ;
     RECT  668.455 14.975 669.065 18.755 ;
     RECT  718.455 14.975 719.065 18.755 ;
     RECT  768.455 14.975 769.065 18.755 ;
     RECT  818.455 14.975 819.065 18.755 ;
     RECT  868.455 14.975 869.065 18.755 ;
     RECT  918.455 14.975 919.065 18.755 ;
     RECT  968.455 14.975 969.065 18.755 ;
     RECT  1018.455 14.975 1019.065 18.755 ;
     RECT  1068.455 14.975 1069.065 18.755 ;
     RECT  1118.455 14.975 1119.065 18.755 ;
     RECT  1168.455 14.975 1169.065 18.755 ;
     RECT  1218.455 14.975 1219.065 18.755 ;
     RECT  1268.455 14.975 1269.065 18.755 ;
     RECT  1318.455 14.975 1319.065 18.755 ;
     RECT  1368.455 14.975 1369.065 18.755 ;
     RECT  1418.455 14.975 1419.065 18.755 ;
     RECT  1468.455 14.975 1469.065 18.755 ;
     RECT  1518.455 14.975 1519.065 18.755 ;
     RECT  1568.455 14.975 1569.065 18.755 ;
     RECT  1618.455 14.975 1619.065 18.755 ;
     RECT  1668.455 14.975 1669.065 18.755 ;
     RECT  1718.455 14.975 1719.065 18.755 ;
     RECT  1768.455 14.975 1769.065 18.755 ;
     RECT  1818.455 14.975 1819.065 18.755 ;
     RECT  1868.455 14.975 1869.065 18.755 ;
     RECT  1015.455 18.755 1019.065 75.745 ;
     RECT  1065.455 18.755 1069.065 75.745 ;
     RECT  1115.455 18.755 1119.065 75.745 ;
     RECT  1165.455 18.755 1169.065 75.745 ;
     RECT  1215.455 18.755 1219.065 75.745 ;
     RECT  1265.455 18.755 1269.065 75.745 ;
     RECT  1315.455 18.755 1319.065 75.745 ;
     RECT  1365.455 18.755 1369.065 75.745 ;
     RECT  1415.455 18.755 1419.065 75.745 ;
     RECT  1465.455 18.755 1469.065 75.745 ;
     RECT  1515.455 18.755 1519.065 75.745 ;
     RECT  1565.455 18.755 1569.065 75.745 ;
     RECT  1615.455 18.755 1619.065 75.745 ;
     RECT  1665.455 18.755 1669.065 75.745 ;
     RECT  1015.455 75.745 1016.065 79.525 ;
     RECT  1065.455 75.745 1066.065 79.525 ;
     RECT  1115.455 75.745 1116.065 79.525 ;
     RECT  1165.455 75.745 1166.065 79.525 ;
     RECT  1215.455 75.745 1216.065 79.525 ;
     RECT  1265.455 75.745 1266.065 79.525 ;
     RECT  1315.455 75.745 1316.065 79.525 ;
     RECT  1365.455 75.745 1366.065 79.525 ;
     RECT  1415.455 75.745 1416.065 79.525 ;
     RECT  1465.455 75.745 1466.065 79.525 ;
     RECT  1515.455 75.745 1516.065 79.525 ;
     RECT  1565.455 75.745 1566.065 79.525 ;
     RECT  1615.455 75.745 1616.065 79.525 ;
     RECT  1665.455 75.745 1666.065 79.525 ;
     RECT  65.455 18.755 69.065 185.365 ;
     RECT  115.455 18.755 119.065 185.365 ;
     RECT  165.455 18.755 169.065 185.365 ;
     RECT  215.455 18.755 219.065 185.365 ;
     RECT  265.455 18.755 269.065 185.365 ;
     RECT  315.455 18.755 319.065 185.365 ;
     RECT  365.455 18.755 369.065 185.365 ;
     RECT  415.455 18.755 419.065 185.365 ;
     RECT  465.455 18.755 469.065 185.365 ;
     RECT  515.455 18.755 519.065 185.365 ;
     RECT  565.455 18.755 569.065 185.365 ;
     RECT  615.455 18.755 619.065 185.365 ;
     RECT  665.455 18.755 669.065 185.365 ;
     RECT  715.455 18.755 719.065 185.365 ;
     RECT  68.455 185.365 69.065 189.145 ;
     RECT  118.455 185.365 119.065 189.145 ;
     RECT  168.455 185.365 169.065 189.145 ;
     RECT  218.455 185.365 219.065 189.145 ;
     RECT  268.455 185.365 269.065 189.145 ;
     RECT  318.455 185.365 319.065 189.145 ;
     RECT  368.455 185.365 369.065 189.145 ;
     RECT  418.455 185.365 419.065 189.145 ;
     RECT  468.455 185.365 469.065 189.145 ;
     RECT  518.455 185.365 519.065 189.145 ;
     RECT  568.455 185.365 569.065 189.145 ;
     RECT  618.455 185.365 619.065 189.145 ;
     RECT  668.455 185.365 669.065 189.145 ;
     RECT  718.455 185.365 719.065 189.145 ;
     RECT  1000 92 1685.49 311.77 ;
     RECT  1018.455 324.935 1019.065 328.715 ;
     RECT  1068.455 324.935 1069.065 328.715 ;
     RECT  1118.455 324.935 1119.065 328.715 ;
     RECT  1168.455 324.935 1169.065 328.715 ;
     RECT  1218.455 324.935 1219.065 328.715 ;
     RECT  1268.455 324.935 1269.065 328.715 ;
     RECT  1318.455 324.935 1319.065 328.715 ;
     RECT  1368.455 324.935 1369.065 328.715 ;
     RECT  1418.455 324.935 1419.065 328.715 ;
     RECT  1468.455 324.935 1469.065 328.715 ;
     RECT  1518.455 324.935 1519.065 328.715 ;
     RECT  1568.455 324.935 1569.065 328.715 ;
     RECT  1618.455 324.935 1619.065 328.715 ;
     RECT  1668.455 324.935 1669.065 328.715 ;
     RECT  50 200 735.49 419.77 ;
     RECT  68.455 430.775 69.065 434.555 ;
     RECT  118.455 430.775 119.065 434.555 ;
     RECT  168.455 430.775 169.065 434.555 ;
     RECT  218.455 430.775 219.065 434.555 ;
     RECT  268.455 430.775 269.065 434.555 ;
     RECT  318.455 430.775 319.065 434.555 ;
     RECT  368.455 430.775 369.065 434.555 ;
     RECT  418.455 430.775 419.065 434.555 ;
     RECT  468.455 430.775 469.065 434.555 ;
     RECT  518.455 430.775 519.065 434.555 ;
     RECT  568.455 430.775 569.065 434.555 ;
     RECT  618.455 430.775 619.065 434.555 ;
     RECT  668.455 430.775 669.065 434.555 ;
     RECT  718.455 430.775 719.065 434.555 ;
     RECT  965.455 18.755 969.065 468.865 ;
     RECT  1015.455 328.715 1019.065 468.865 ;
     RECT  1065.455 328.715 1069.065 468.865 ;
     RECT  1115.455 328.715 1119.065 468.865 ;
     RECT  1165.455 328.715 1169.065 468.865 ;
     RECT  1215.455 328.715 1219.065 468.865 ;
     RECT  1265.455 328.715 1269.065 468.865 ;
     RECT  1315.455 328.715 1319.065 468.865 ;
     RECT  1365.455 328.715 1369.065 468.865 ;
     RECT  1415.455 328.715 1419.065 468.865 ;
     RECT  1465.455 328.715 1469.065 468.865 ;
     RECT  1515.455 328.715 1519.065 468.865 ;
     RECT  1565.455 328.715 1569.065 468.865 ;
     RECT  1615.455 328.715 1619.065 468.865 ;
     RECT  965.455 468.865 966.065 472.645 ;
     RECT  1015.455 468.865 1016.065 472.645 ;
     RECT  1065.455 468.865 1066.065 472.645 ;
     RECT  1115.455 468.865 1116.065 472.645 ;
     RECT  1165.455 468.865 1166.065 472.645 ;
     RECT  1215.455 468.865 1216.065 472.645 ;
     RECT  1265.455 468.865 1266.065 472.645 ;
     RECT  1315.455 468.865 1316.065 472.645 ;
     RECT  1365.455 468.865 1366.065 472.645 ;
     RECT  1415.455 468.865 1416.065 472.645 ;
     RECT  1465.455 468.865 1466.065 472.645 ;
     RECT  1515.455 468.865 1516.065 472.645 ;
     RECT  1565.455 468.865 1566.065 472.645 ;
     RECT  1615.455 468.865 1616.065 472.645 ;
     RECT  65.455 434.555 69.065 620.065 ;
     RECT  115.455 434.555 119.065 620.065 ;
     RECT  165.455 434.555 169.065 620.065 ;
     RECT  215.455 434.555 219.065 620.065 ;
     RECT  265.455 434.555 269.065 620.065 ;
     RECT  315.455 434.555 319.065 620.065 ;
     RECT  365.455 434.555 369.065 620.065 ;
     RECT  415.455 434.555 419.065 620.065 ;
     RECT  465.455 434.555 469.065 620.065 ;
     RECT  515.455 434.555 519.065 620.065 ;
     RECT  565.455 434.555 569.065 620.065 ;
     RECT  615.455 434.555 619.065 620.065 ;
     RECT  665.455 434.555 669.065 620.065 ;
     RECT  715.455 434.555 719.065 620.065 ;
     RECT  65.455 620.065 66.065 623.845 ;
     RECT  115.455 620.065 116.065 623.845 ;
     RECT  165.455 620.065 166.065 623.845 ;
     RECT  215.455 620.065 216.065 623.845 ;
     RECT  265.455 620.065 266.065 623.845 ;
     RECT  315.455 620.065 316.065 623.845 ;
     RECT  365.455 620.065 366.065 623.845 ;
     RECT  415.455 620.065 416.065 623.845 ;
     RECT  465.455 620.065 466.065 623.845 ;
     RECT  515.455 620.065 516.065 623.845 ;
     RECT  565.455 620.065 566.065 623.845 ;
     RECT  615.455 620.065 616.065 623.845 ;
     RECT  665.455 620.065 666.065 623.845 ;
     RECT  715.455 620.065 716.065 623.845 ;
     RECT  950 484 1635.49 703.77 ;
     RECT  965.455 714.275 966.065 718.055 ;
     RECT  1015.455 714.275 1016.065 718.055 ;
     RECT  1065.455 714.275 1066.065 718.055 ;
     RECT  1115.455 714.275 1116.065 718.055 ;
     RECT  1165.455 714.275 1166.065 718.055 ;
     RECT  1215.455 714.275 1216.065 718.055 ;
     RECT  1265.455 714.275 1266.065 718.055 ;
     RECT  1315.455 714.275 1316.065 718.055 ;
     RECT  1365.455 714.275 1366.065 718.055 ;
     RECT  1415.455 714.275 1416.065 718.055 ;
     RECT  1465.455 714.275 1466.065 718.055 ;
     RECT  1515.455 714.275 1516.065 718.055 ;
     RECT  1565.455 714.275 1566.065 718.055 ;
     RECT  1615.455 714.275 1616.065 718.055 ;
     RECT  50 636 735.49 855.77 ;
     RECT  68.455 869.255 69.065 873.035 ;
     RECT  118.455 869.255 119.065 873.035 ;
     RECT  168.455 869.255 169.065 873.035 ;
     RECT  218.455 869.255 219.065 873.035 ;
     RECT  268.455 869.255 269.065 873.035 ;
     RECT  318.455 869.255 319.065 873.035 ;
     RECT  368.455 869.255 369.065 873.035 ;
     RECT  418.455 869.255 419.065 873.035 ;
     RECT  468.455 869.255 469.065 873.035 ;
     RECT  518.455 869.255 519.065 873.035 ;
     RECT  568.455 869.255 569.065 873.035 ;
     RECT  618.455 869.255 619.065 873.035 ;
     RECT  668.455 869.255 669.065 873.035 ;
     RECT  718.455 869.255 719.065 873.035 ;
     RECT  65.455 873.035 69.065 873.325 ;
     RECT  115.455 873.035 119.065 873.325 ;
     RECT  165.455 873.035 169.065 873.325 ;
     RECT  215.455 873.035 219.065 873.325 ;
     RECT  265.455 873.035 269.065 873.325 ;
     RECT  315.455 873.035 319.065 873.325 ;
     RECT  365.455 873.035 369.065 873.325 ;
     RECT  415.455 873.035 419.065 873.325 ;
     RECT  465.455 873.035 469.065 873.325 ;
     RECT  515.455 873.035 519.065 873.325 ;
     RECT  565.455 873.035 569.065 873.325 ;
     RECT  615.455 873.035 619.065 873.325 ;
     RECT  665.455 873.035 669.065 873.325 ;
     RECT  715.455 873.035 719.065 873.325 ;
     RECT  68.455 873.325 69.065 877.105 ;
     RECT  118.455 873.325 119.065 877.105 ;
     RECT  168.455 873.325 169.065 877.105 ;
     RECT  218.455 873.325 219.065 877.105 ;
     RECT  268.455 873.325 269.065 877.105 ;
     RECT  318.455 873.325 319.065 877.105 ;
     RECT  368.455 873.325 369.065 877.105 ;
     RECT  418.455 873.325 419.065 877.105 ;
     RECT  468.455 873.325 469.065 877.105 ;
     RECT  518.455 873.325 519.065 877.105 ;
     RECT  568.455 873.325 569.065 877.105 ;
     RECT  618.455 873.325 619.065 877.105 ;
     RECT  668.455 873.325 669.065 877.105 ;
     RECT  718.455 873.325 719.065 877.105 ;
     RECT  965.455 718.055 969.065 884.665 ;
     RECT  1015.455 718.055 1019.065 884.665 ;
     RECT  1065.455 718.055 1069.065 884.665 ;
     RECT  1115.455 718.055 1119.065 884.665 ;
     RECT  1165.455 718.055 1169.065 884.665 ;
     RECT  1215.455 718.055 1219.065 884.665 ;
     RECT  1265.455 718.055 1269.065 884.665 ;
     RECT  1315.455 718.055 1319.065 884.665 ;
     RECT  1365.455 718.055 1369.065 884.665 ;
     RECT  1415.455 718.055 1419.065 884.665 ;
     RECT  1465.455 718.055 1469.065 884.665 ;
     RECT  1515.455 718.055 1519.065 884.665 ;
     RECT  1565.455 718.055 1569.065 884.665 ;
     RECT  1615.455 718.055 1619.065 884.665 ;
     RECT  965.455 884.665 966.065 888.445 ;
     RECT  1015.455 884.665 1016.065 888.445 ;
     RECT  1065.455 884.665 1066.065 888.445 ;
     RECT  1115.455 884.665 1116.065 888.445 ;
     RECT  1165.455 884.665 1166.065 888.445 ;
     RECT  1215.455 884.665 1216.065 888.445 ;
     RECT  1265.455 884.665 1266.065 888.445 ;
     RECT  1315.455 884.665 1316.065 888.445 ;
     RECT  1365.455 884.665 1366.065 888.445 ;
     RECT  1415.455 884.665 1416.065 888.445 ;
     RECT  1465.455 884.665 1466.065 888.445 ;
     RECT  1515.455 884.665 1516.065 888.445 ;
     RECT  1565.455 884.665 1566.065 888.445 ;
     RECT  1615.455 884.665 1616.065 888.445 ;
     RECT  50 888 735.49 1107.77 ;
     RECT  950 899.72 1635.49 1119.49 ;
     RECT  68.455 1118.735 69.065 1122.515 ;
     RECT  118.455 1118.735 119.065 1122.515 ;
     RECT  168.455 1118.735 169.065 1122.515 ;
     RECT  218.455 1118.735 219.065 1122.515 ;
     RECT  268.455 1118.735 269.065 1122.515 ;
     RECT  318.455 1118.735 319.065 1122.515 ;
     RECT  368.455 1118.735 369.065 1122.515 ;
     RECT  418.455 1118.735 419.065 1122.515 ;
     RECT  468.455 1118.735 469.065 1122.515 ;
     RECT  518.455 1118.735 519.065 1122.515 ;
     RECT  568.455 1118.735 569.065 1122.515 ;
     RECT  618.455 1118.735 619.065 1122.515 ;
     RECT  668.455 1118.735 669.065 1122.515 ;
     RECT  718.455 1118.735 719.065 1122.515 ;
     RECT  965.455 1130.075 966.065 1133.855 ;
     RECT  1015.455 1130.075 1016.065 1133.855 ;
     RECT  1065.455 1130.075 1066.065 1133.855 ;
     RECT  1115.455 1130.075 1116.065 1133.855 ;
     RECT  1165.455 1130.075 1166.065 1133.855 ;
     RECT  1215.455 1130.075 1216.065 1133.855 ;
     RECT  1265.455 1130.075 1266.065 1133.855 ;
     RECT  1315.455 1130.075 1316.065 1133.855 ;
     RECT  1365.455 1130.075 1366.065 1133.855 ;
     RECT  1415.455 1130.075 1416.065 1133.855 ;
     RECT  1465.455 1130.075 1466.065 1133.855 ;
     RECT  1515.455 1130.075 1516.065 1133.855 ;
     RECT  1565.455 1130.075 1566.065 1133.855 ;
     RECT  1615.455 1130.075 1616.065 1133.855 ;
     RECT  65.455 1122.515 69.065 1255.105 ;
     RECT  115.455 1122.515 119.065 1255.105 ;
     RECT  165.455 1122.515 169.065 1255.105 ;
     RECT  215.455 1122.515 219.065 1255.105 ;
     RECT  265.455 1122.515 269.065 1255.105 ;
     RECT  315.455 1122.515 319.065 1255.105 ;
     RECT  365.455 1122.515 369.065 1255.105 ;
     RECT  415.455 1122.515 419.065 1255.105 ;
     RECT  465.455 1122.515 469.065 1255.105 ;
     RECT  515.455 1122.515 519.065 1255.105 ;
     RECT  565.455 1122.515 569.065 1255.105 ;
     RECT  615.455 1122.515 619.065 1255.105 ;
     RECT  665.455 1122.515 669.065 1255.105 ;
     RECT  715.455 1122.515 719.065 1255.105 ;
     RECT  65.455 1255.105 66.065 1258.885 ;
     RECT  115.455 1255.105 116.065 1258.885 ;
     RECT  165.455 1255.105 166.065 1258.885 ;
     RECT  215.455 1255.105 216.065 1258.885 ;
     RECT  265.455 1255.105 266.065 1258.885 ;
     RECT  315.455 1255.105 316.065 1258.885 ;
     RECT  365.455 1255.105 366.065 1258.885 ;
     RECT  415.455 1255.105 416.065 1258.885 ;
     RECT  465.455 1255.105 466.065 1258.885 ;
     RECT  515.455 1255.105 516.065 1258.885 ;
     RECT  565.455 1255.105 566.065 1258.885 ;
     RECT  615.455 1255.105 616.065 1258.885 ;
     RECT  665.455 1255.105 666.065 1258.885 ;
     RECT  715.455 1255.105 716.065 1258.885 ;
     RECT  1115.455 1133.855 1119.065 1463.005 ;
     RECT  1165.455 1133.855 1169.065 1463.005 ;
     RECT  1215.455 1133.855 1219.065 1463.005 ;
     RECT  1265.455 1133.855 1269.065 1463.005 ;
     RECT  1315.455 1133.855 1319.065 1463.005 ;
     RECT  1365.455 1133.855 1369.065 1463.005 ;
     RECT  1415.455 1133.855 1419.065 1463.005 ;
     RECT  1465.455 1133.855 1469.065 1463.005 ;
     RECT  1515.455 1133.855 1519.065 1463.005 ;
     RECT  1565.455 1133.855 1569.065 1463.005 ;
     RECT  1615.455 1133.855 1619.065 1463.005 ;
     RECT  1665.455 328.715 1669.065 1463.005 ;
     RECT  1715.455 18.755 1719.065 1463.005 ;
     RECT  1765.455 18.755 1769.065 1463.005 ;
     RECT  1118.455 1463.005 1119.065 1466.785 ;
     RECT  1168.455 1463.005 1169.065 1466.785 ;
     RECT  1218.455 1463.005 1219.065 1466.785 ;
     RECT  1268.455 1463.005 1269.065 1466.785 ;
     RECT  1318.455 1463.005 1319.065 1466.785 ;
     RECT  1368.455 1463.005 1369.065 1466.785 ;
     RECT  1418.455 1463.005 1419.065 1466.785 ;
     RECT  1468.455 1463.005 1469.065 1466.785 ;
     RECT  1518.455 1463.005 1519.065 1466.785 ;
     RECT  1568.455 1463.005 1569.065 1466.785 ;
     RECT  1618.455 1463.005 1619.065 1466.785 ;
     RECT  1668.455 1463.005 1669.065 1466.785 ;
     RECT  1718.455 1463.005 1719.065 1466.785 ;
     RECT  1768.455 1463.005 1769.065 1466.785 ;
     RECT  50 1270 735.49 1489.77 ;
     RECT  65.455 1500.515 66.065 1504.295 ;
     RECT  115.455 1500.515 116.065 1504.295 ;
     RECT  165.455 1500.515 166.065 1504.295 ;
     RECT  215.455 1500.515 216.065 1504.295 ;
     RECT  265.455 1500.515 266.065 1504.295 ;
     RECT  315.455 1500.515 316.065 1504.295 ;
     RECT  365.455 1500.515 366.065 1504.295 ;
     RECT  415.455 1500.515 416.065 1504.295 ;
     RECT  465.455 1500.515 466.065 1504.295 ;
     RECT  515.455 1500.515 516.065 1504.295 ;
     RECT  565.455 1500.515 566.065 1504.295 ;
     RECT  615.455 1500.515 616.065 1504.295 ;
     RECT  665.455 1500.515 666.065 1504.295 ;
     RECT  715.455 1500.515 716.065 1504.295 ;
     RECT  65.455 1504.295 69.065 1538.605 ;
     RECT  115.455 1504.295 119.065 1538.605 ;
     RECT  165.455 1504.295 169.065 1538.605 ;
     RECT  215.455 1504.295 219.065 1538.605 ;
     RECT  265.455 1504.295 269.065 1538.605 ;
     RECT  315.455 1504.295 319.065 1538.605 ;
     RECT  365.455 1504.295 369.065 1538.605 ;
     RECT  415.455 1504.295 419.065 1538.605 ;
     RECT  465.455 1504.295 469.065 1538.605 ;
     RECT  515.455 1504.295 519.065 1538.605 ;
     RECT  565.455 1504.295 569.065 1538.605 ;
     RECT  615.455 1504.295 619.065 1538.605 ;
     RECT  665.455 1504.295 669.065 1538.605 ;
     RECT  715.455 1504.295 719.065 1538.605 ;
     RECT  68.455 1538.605 69.065 1542.385 ;
     RECT  118.455 1538.605 119.065 1542.385 ;
     RECT  168.455 1538.605 169.065 1542.385 ;
     RECT  218.455 1538.605 219.065 1542.385 ;
     RECT  268.455 1538.605 269.065 1542.385 ;
     RECT  318.455 1538.605 319.065 1542.385 ;
     RECT  368.455 1538.605 369.065 1542.385 ;
     RECT  418.455 1538.605 419.065 1542.385 ;
     RECT  468.455 1538.605 469.065 1542.385 ;
     RECT  518.455 1538.605 519.065 1542.385 ;
     RECT  568.455 1538.605 569.065 1542.385 ;
     RECT  618.455 1538.605 619.065 1542.385 ;
     RECT  668.455 1538.605 669.065 1542.385 ;
     RECT  718.455 1538.605 719.065 1542.385 ;
     RECT  1100 1480 1785.49 1699.77 ;
     RECT  1115.455 1712.195 1116.065 1715.975 ;
     RECT  1165.455 1712.195 1166.065 1715.975 ;
     RECT  1215.455 1712.195 1216.065 1715.975 ;
     RECT  1265.455 1712.195 1266.065 1715.975 ;
     RECT  1315.455 1712.195 1316.065 1715.975 ;
     RECT  1365.455 1712.195 1366.065 1715.975 ;
     RECT  1415.455 1712.195 1416.065 1715.975 ;
     RECT  1465.455 1712.195 1466.065 1715.975 ;
     RECT  1515.455 1712.195 1516.065 1715.975 ;
     RECT  1565.455 1712.195 1566.065 1715.975 ;
     RECT  1615.455 1712.195 1616.065 1715.975 ;
     RECT  1665.455 1712.195 1666.065 1715.975 ;
     RECT  1715.455 1712.195 1716.065 1715.975 ;
     RECT  1765.455 1712.195 1766.065 1715.975 ;
     RECT  1115.455 1715.975 1119.065 1735.165 ;
     RECT  1165.455 1715.975 1169.065 1735.165 ;
     RECT  1215.455 1715.975 1219.065 1735.165 ;
     RECT  1265.455 1715.975 1269.065 1735.165 ;
     RECT  1315.455 1715.975 1319.065 1735.165 ;
     RECT  1365.455 1715.975 1369.065 1735.165 ;
     RECT  1415.455 1715.975 1419.065 1735.165 ;
     RECT  1465.455 1715.975 1469.065 1735.165 ;
     RECT  1515.455 1715.975 1519.065 1735.165 ;
     RECT  1565.455 1715.975 1569.065 1735.165 ;
     RECT  1615.455 1715.975 1619.065 1735.165 ;
     RECT  1665.455 1715.975 1669.065 1735.165 ;
     RECT  1715.455 1715.975 1719.065 1735.165 ;
     RECT  1765.455 1715.975 1769.065 1735.165 ;
     RECT  1815.455 18.755 1819.065 1735.165 ;
     RECT  1118.455 1735.165 1119.065 1738.945 ;
     RECT  1168.455 1735.165 1169.065 1738.945 ;
     RECT  1218.455 1735.165 1219.065 1738.945 ;
     RECT  1268.455 1735.165 1269.065 1738.945 ;
     RECT  1318.455 1735.165 1319.065 1738.945 ;
     RECT  1368.455 1735.165 1369.065 1738.945 ;
     RECT  1418.455 1735.165 1419.065 1738.945 ;
     RECT  1468.455 1735.165 1469.065 1738.945 ;
     RECT  1518.455 1735.165 1519.065 1738.945 ;
     RECT  1568.455 1735.165 1569.065 1738.945 ;
     RECT  1618.455 1735.165 1619.065 1738.945 ;
     RECT  1668.455 1735.165 1669.065 1738.945 ;
     RECT  1718.455 1735.165 1719.065 1738.945 ;
     RECT  1768.455 1735.165 1769.065 1738.945 ;
     RECT  1818.455 1735.165 1819.065 1738.945 ;
     RECT  50 1556 735.49 1775.77 ;
     RECT  65.455 1787.795 66.065 1791.575 ;
     RECT  115.455 1787.795 116.065 1791.575 ;
     RECT  165.455 1787.795 166.065 1791.575 ;
     RECT  215.455 1787.795 216.065 1791.575 ;
     RECT  265.455 1787.795 266.065 1791.575 ;
     RECT  315.455 1787.795 316.065 1791.575 ;
     RECT  365.455 1787.795 366.065 1791.575 ;
     RECT  415.455 1787.795 416.065 1791.575 ;
     RECT  465.455 1787.795 466.065 1791.575 ;
     RECT  515.455 1787.795 516.065 1791.575 ;
     RECT  565.455 1787.795 566.065 1791.575 ;
     RECT  615.455 1787.795 616.065 1791.575 ;
     RECT  665.455 1787.795 666.065 1791.575 ;
     RECT  715.455 1787.795 716.065 1791.575 ;
     RECT  65.455 1791.575 69.065 1912.825 ;
     RECT  115.455 1791.575 119.065 1912.825 ;
     RECT  165.455 1791.575 169.065 1912.825 ;
     RECT  215.455 1791.575 219.065 1912.825 ;
     RECT  265.455 1791.575 269.065 1912.825 ;
     RECT  315.455 1791.575 319.065 1912.825 ;
     RECT  365.455 1791.575 369.065 1912.825 ;
     RECT  415.455 1791.575 419.065 1912.825 ;
     RECT  465.455 1791.575 469.065 1912.825 ;
     RECT  515.455 1791.575 519.065 1912.825 ;
     RECT  565.455 1791.575 569.065 1912.825 ;
     RECT  615.455 1791.575 619.065 1912.825 ;
     RECT  665.455 1791.575 669.065 1912.825 ;
     RECT  715.455 1791.575 719.065 1912.825 ;
     RECT  65.455 1912.825 66.065 1916.605 ;
     RECT  115.455 1912.825 116.065 1916.605 ;
     RECT  165.455 1912.825 166.065 1916.605 ;
     RECT  215.455 1912.825 216.065 1916.605 ;
     RECT  265.455 1912.825 266.065 1916.605 ;
     RECT  315.455 1912.825 316.065 1916.605 ;
     RECT  365.455 1912.825 366.065 1916.605 ;
     RECT  415.455 1912.825 416.065 1916.605 ;
     RECT  465.455 1912.825 466.065 1916.605 ;
     RECT  515.455 1912.825 516.065 1916.605 ;
     RECT  565.455 1912.825 566.065 1916.605 ;
     RECT  615.455 1912.825 616.065 1916.605 ;
     RECT  665.455 1912.825 666.065 1916.605 ;
     RECT  715.455 1912.825 716.065 1916.605 ;
     RECT  1125 1749.64 1810.49 1969.41 ;
     RECT  1118.455 1980.575 1119.065 1984.355 ;
     RECT  1168.455 1980.575 1169.065 1984.355 ;
     RECT  1218.455 1980.575 1219.065 1984.355 ;
     RECT  1268.455 1980.575 1269.065 1984.355 ;
     RECT  1318.455 1980.575 1319.065 1984.355 ;
     RECT  1368.455 1980.575 1369.065 1984.355 ;
     RECT  1418.455 1980.575 1419.065 1984.355 ;
     RECT  1468.455 1980.575 1469.065 1984.355 ;
     RECT  1518.455 1980.575 1519.065 1984.355 ;
     RECT  1568.455 1980.575 1569.065 1984.355 ;
     RECT  1618.455 1980.575 1619.065 1984.355 ;
     RECT  1668.455 1980.575 1669.065 1984.355 ;
     RECT  1718.455 1980.575 1719.065 1984.355 ;
     RECT  1768.455 1980.575 1769.065 1984.355 ;
     RECT  1818.455 1980.575 1819.065 1984.355 ;
     RECT  50 1930 735.49 2149.77 ;
     RECT  68.455 2162.015 69.065 2165.795 ;
     RECT  118.455 2162.015 119.065 2165.795 ;
     RECT  168.455 2162.015 169.065 2165.795 ;
     RECT  218.455 2162.015 219.065 2165.795 ;
     RECT  268.455 2162.015 269.065 2165.795 ;
     RECT  318.455 2162.015 319.065 2165.795 ;
     RECT  368.455 2162.015 369.065 2165.795 ;
     RECT  418.455 2162.015 419.065 2165.795 ;
     RECT  468.455 2162.015 469.065 2165.795 ;
     RECT  518.455 2162.015 519.065 2165.795 ;
     RECT  568.455 2162.015 569.065 2165.795 ;
     RECT  618.455 2162.015 619.065 2165.795 ;
     RECT  668.455 2162.015 669.065 2165.795 ;
     RECT  718.455 2162.015 719.065 2165.795 ;
     RECT  15.455 18.755 19.065 2181.205 ;
     RECT  65.455 2165.795 69.065 2181.205 ;
     RECT  115.455 2165.795 119.065 2181.205 ;
     RECT  165.455 2165.795 169.065 2181.205 ;
     RECT  215.455 2165.795 219.065 2181.205 ;
     RECT  265.455 2165.795 269.065 2181.205 ;
     RECT  315.455 2165.795 319.065 2181.205 ;
     RECT  365.455 2165.795 369.065 2181.205 ;
     RECT  415.455 2165.795 419.065 2181.205 ;
     RECT  465.455 2165.795 469.065 2181.205 ;
     RECT  515.455 2165.795 519.065 2181.205 ;
     RECT  565.455 2165.795 569.065 2181.205 ;
     RECT  615.455 2165.795 619.065 2181.205 ;
     RECT  665.455 2165.795 669.065 2181.205 ;
     RECT  715.455 2165.795 719.065 2181.205 ;
     RECT  765.455 18.755 769.065 2181.205 ;
     RECT  815.455 18.755 819.065 2181.205 ;
     RECT  865.455 18.755 869.065 2181.205 ;
     RECT  915.455 18.755 919.065 2181.205 ;
     RECT  965.455 1133.855 969.065 2181.205 ;
     RECT  1015.455 1133.855 1019.065 2181.205 ;
     RECT  1065.455 1133.855 1069.065 2181.205 ;
     RECT  1115.455 1984.355 1119.065 2181.205 ;
     RECT  1165.455 1984.355 1169.065 2181.205 ;
     RECT  1215.455 1984.355 1219.065 2181.205 ;
     RECT  1265.455 1984.355 1269.065 2181.205 ;
     RECT  1315.455 1984.355 1319.065 2181.205 ;
     RECT  1365.455 1984.355 1369.065 2181.205 ;
     RECT  1415.455 1984.355 1419.065 2181.205 ;
     RECT  1465.455 1984.355 1469.065 2181.205 ;
     RECT  1515.455 1984.355 1519.065 2181.205 ;
     RECT  1565.455 1984.355 1569.065 2181.205 ;
     RECT  1615.455 1984.355 1619.065 2181.205 ;
     RECT  1665.455 1984.355 1669.065 2181.205 ;
     RECT  1715.455 1984.355 1719.065 2181.205 ;
     RECT  1765.455 1984.355 1769.065 2181.205 ;
     RECT  1815.455 1984.355 1819.065 2181.205 ;
     RECT  1865.455 18.755 1869.065 2181.205 ;
     RECT  18.455 2181.205 19.065 2184.985 ;
     RECT  68.455 2181.205 69.065 2184.985 ;
     RECT  118.455 2181.205 119.065 2184.985 ;
     RECT  168.455 2181.205 169.065 2184.985 ;
     RECT  218.455 2181.205 219.065 2184.985 ;
     RECT  268.455 2181.205 269.065 2184.985 ;
     RECT  318.455 2181.205 319.065 2184.985 ;
     RECT  368.455 2181.205 369.065 2184.985 ;
     RECT  418.455 2181.205 419.065 2184.985 ;
     RECT  468.455 2181.205 469.065 2184.985 ;
     RECT  518.455 2181.205 519.065 2184.985 ;
     RECT  568.455 2181.205 569.065 2184.985 ;
     RECT  618.455 2181.205 619.065 2184.985 ;
     RECT  668.455 2181.205 669.065 2184.985 ;
     RECT  718.455 2181.205 719.065 2184.985 ;
     RECT  768.455 2181.205 769.065 2184.985 ;
     RECT  818.455 2181.205 819.065 2184.985 ;
     RECT  868.455 2181.205 869.065 2184.985 ;
     RECT  918.455 2181.205 919.065 2184.985 ;
     RECT  968.455 2181.205 969.065 2184.985 ;
     RECT  1018.455 2181.205 1019.065 2184.985 ;
     RECT  1068.455 2181.205 1069.065 2184.985 ;
     RECT  1118.455 2181.205 1119.065 2184.985 ;
     RECT  1168.455 2181.205 1169.065 2184.985 ;
     RECT  1218.455 2181.205 1219.065 2184.985 ;
     RECT  1268.455 2181.205 1269.065 2184.985 ;
     RECT  1318.455 2181.205 1319.065 2184.985 ;
     RECT  1368.455 2181.205 1369.065 2184.985 ;
     RECT  1418.455 2181.205 1419.065 2184.985 ;
     RECT  1468.455 2181.205 1469.065 2184.985 ;
     RECT  1518.455 2181.205 1519.065 2184.985 ;
     RECT  1568.455 2181.205 1569.065 2184.985 ;
     RECT  1618.455 2181.205 1619.065 2184.985 ;
     RECT  1668.455 2181.205 1669.065 2184.985 ;
     RECT  1718.455 2181.205 1719.065 2184.985 ;
     RECT  1768.455 2181.205 1769.065 2184.985 ;
     RECT  1818.455 2181.205 1819.065 2184.985 ;
     RECT  1868.455 2181.205 1869.065 2184.985 ;
    LAYER Metal3 ;
     RECT  15.4 18.8 18.4 2181.16 ;
     RECT  18.4 15.02 19.12 2184.94 ;
     RECT  65.4 434.6 66.12 623.8 ;
     RECT  65.4 1122.56 66.12 1258.84 ;
     RECT  65.4 1500.56 66.12 1538.56 ;
     RECT  65.4 1787.84 66.12 1916.56 ;
     RECT  65.4 18.8 68.4 185.32 ;
     RECT  66.12 434.6 68.4 620.02 ;
     RECT  65.4 873.08 68.4 873.28 ;
     RECT  66.12 1122.56 68.4 1255.06 ;
     RECT  66.12 1504.34 68.4 1538.56 ;
     RECT  65.4 2165.84 68.4 2181.16 ;
     RECT  68.4 15.02 69.12 189.1 ;
     RECT  68.4 430.82 69.12 620.02 ;
     RECT  68.4 869.3 69.12 877.06 ;
     RECT  68.4 1118.78 69.12 1255.06 ;
     RECT  68.4 1504.34 69.12 1542.34 ;
     RECT  66.12 1791.62 69.12 1912.78 ;
     RECT  68.4 2162.06 69.12 2184.94 ;
     RECT  115.4 434.6 116.12 623.8 ;
     RECT  115.4 1122.56 116.12 1258.84 ;
     RECT  115.4 1500.56 116.12 1538.56 ;
     RECT  115.4 1787.84 116.12 1916.56 ;
     RECT  115.4 18.8 118.4 185.32 ;
     RECT  116.12 434.6 118.4 620.02 ;
     RECT  115.4 873.08 118.4 873.28 ;
     RECT  116.12 1122.56 118.4 1255.06 ;
     RECT  116.12 1504.34 118.4 1538.56 ;
     RECT  115.4 2165.84 118.4 2181.16 ;
     RECT  118.4 15.02 119.12 189.1 ;
     RECT  118.4 430.82 119.12 620.02 ;
     RECT  118.4 869.3 119.12 877.06 ;
     RECT  118.4 1118.78 119.12 1255.06 ;
     RECT  118.4 1504.34 119.12 1542.34 ;
     RECT  116.12 1791.62 119.12 1912.78 ;
     RECT  118.4 2162.06 119.12 2184.94 ;
     RECT  165.4 434.6 166.12 623.8 ;
     RECT  165.4 1122.56 166.12 1258.84 ;
     RECT  165.4 1500.56 166.12 1538.56 ;
     RECT  165.4 1787.84 166.12 1916.56 ;
     RECT  165.4 18.8 168.4 185.32 ;
     RECT  166.12 434.6 168.4 620.02 ;
     RECT  165.4 873.08 168.4 873.28 ;
     RECT  166.12 1122.56 168.4 1255.06 ;
     RECT  166.12 1504.34 168.4 1538.56 ;
     RECT  165.4 2165.84 168.4 2181.16 ;
     RECT  168.4 15.02 169.12 189.1 ;
     RECT  168.4 430.82 169.12 620.02 ;
     RECT  168.4 869.3 169.12 877.06 ;
     RECT  168.4 1118.78 169.12 1255.06 ;
     RECT  168.4 1504.34 169.12 1542.34 ;
     RECT  166.12 1791.62 169.12 1912.78 ;
     RECT  168.4 2162.06 169.12 2184.94 ;
     RECT  215.4 434.6 216.12 623.8 ;
     RECT  215.4 1122.56 216.12 1258.84 ;
     RECT  215.4 1500.56 216.12 1538.56 ;
     RECT  215.4 1787.84 216.12 1916.56 ;
     RECT  215.4 18.8 218.4 185.32 ;
     RECT  216.12 434.6 218.4 620.02 ;
     RECT  215.4 873.08 218.4 873.28 ;
     RECT  216.12 1122.56 218.4 1255.06 ;
     RECT  216.12 1504.34 218.4 1538.56 ;
     RECT  215.4 2165.84 218.4 2181.16 ;
     RECT  218.4 15.02 219.12 189.1 ;
     RECT  218.4 430.82 219.12 620.02 ;
     RECT  218.4 869.3 219.12 877.06 ;
     RECT  218.4 1118.78 219.12 1255.06 ;
     RECT  218.4 1504.34 219.12 1542.34 ;
     RECT  216.12 1791.62 219.12 1912.78 ;
     RECT  218.4 2162.06 219.12 2184.94 ;
     RECT  265.4 434.6 266.12 623.8 ;
     RECT  265.4 1122.56 266.12 1258.84 ;
     RECT  265.4 1500.56 266.12 1538.56 ;
     RECT  265.4 1787.84 266.12 1916.56 ;
     RECT  265.4 18.8 268.4 185.32 ;
     RECT  266.12 434.6 268.4 620.02 ;
     RECT  265.4 873.08 268.4 873.28 ;
     RECT  266.12 1122.56 268.4 1255.06 ;
     RECT  266.12 1504.34 268.4 1538.56 ;
     RECT  265.4 2165.84 268.4 2181.16 ;
     RECT  268.4 15.02 269.12 189.1 ;
     RECT  268.4 430.82 269.12 620.02 ;
     RECT  268.4 869.3 269.12 877.06 ;
     RECT  268.4 1118.78 269.12 1255.06 ;
     RECT  268.4 1504.34 269.12 1542.34 ;
     RECT  266.12 1791.62 269.12 1912.78 ;
     RECT  268.4 2162.06 269.12 2184.94 ;
     RECT  315.4 434.6 316.12 623.8 ;
     RECT  315.4 1122.56 316.12 1258.84 ;
     RECT  315.4 1500.56 316.12 1538.56 ;
     RECT  315.4 1787.84 316.12 1916.56 ;
     RECT  315.4 18.8 318.4 185.32 ;
     RECT  316.12 434.6 318.4 620.02 ;
     RECT  315.4 873.08 318.4 873.28 ;
     RECT  316.12 1122.56 318.4 1255.06 ;
     RECT  316.12 1504.34 318.4 1538.56 ;
     RECT  315.4 2165.84 318.4 2181.16 ;
     RECT  318.4 15.02 319.12 189.1 ;
     RECT  318.4 430.82 319.12 620.02 ;
     RECT  318.4 869.3 319.12 877.06 ;
     RECT  318.4 1118.78 319.12 1255.06 ;
     RECT  318.4 1504.34 319.12 1542.34 ;
     RECT  316.12 1791.62 319.12 1912.78 ;
     RECT  318.4 2162.06 319.12 2184.94 ;
     RECT  365.4 434.6 366.12 623.8 ;
     RECT  365.4 1122.56 366.12 1258.84 ;
     RECT  365.4 1500.56 366.12 1538.56 ;
     RECT  365.4 1787.84 366.12 1916.56 ;
     RECT  365.4 18.8 368.4 185.32 ;
     RECT  366.12 434.6 368.4 620.02 ;
     RECT  365.4 873.08 368.4 873.28 ;
     RECT  366.12 1122.56 368.4 1255.06 ;
     RECT  366.12 1504.34 368.4 1538.56 ;
     RECT  365.4 2165.84 368.4 2181.16 ;
     RECT  368.4 15.02 369.12 189.1 ;
     RECT  368.4 430.82 369.12 620.02 ;
     RECT  368.4 869.3 369.12 877.06 ;
     RECT  368.4 1118.78 369.12 1255.06 ;
     RECT  368.4 1504.34 369.12 1542.34 ;
     RECT  366.12 1791.62 369.12 1912.78 ;
     RECT  368.4 2162.06 369.12 2184.94 ;
     RECT  415.4 434.6 416.12 623.8 ;
     RECT  415.4 1122.56 416.12 1258.84 ;
     RECT  415.4 1500.56 416.12 1538.56 ;
     RECT  415.4 1787.84 416.12 1916.56 ;
     RECT  415.4 18.8 418.4 185.32 ;
     RECT  416.12 434.6 418.4 620.02 ;
     RECT  415.4 873.08 418.4 873.28 ;
     RECT  416.12 1122.56 418.4 1255.06 ;
     RECT  416.12 1504.34 418.4 1538.56 ;
     RECT  415.4 2165.84 418.4 2181.16 ;
     RECT  418.4 15.02 419.12 189.1 ;
     RECT  418.4 430.82 419.12 620.02 ;
     RECT  418.4 869.3 419.12 877.06 ;
     RECT  418.4 1118.78 419.12 1255.06 ;
     RECT  418.4 1504.34 419.12 1542.34 ;
     RECT  416.12 1791.62 419.12 1912.78 ;
     RECT  418.4 2162.06 419.12 2184.94 ;
     RECT  465.4 434.6 466.12 623.8 ;
     RECT  465.4 1122.56 466.12 1258.84 ;
     RECT  465.4 1500.56 466.12 1538.56 ;
     RECT  465.4 1787.84 466.12 1916.56 ;
     RECT  465.4 18.8 468.4 185.32 ;
     RECT  466.12 434.6 468.4 620.02 ;
     RECT  465.4 873.08 468.4 873.28 ;
     RECT  466.12 1122.56 468.4 1255.06 ;
     RECT  466.12 1504.34 468.4 1538.56 ;
     RECT  465.4 2165.84 468.4 2181.16 ;
     RECT  468.4 15.02 469.12 189.1 ;
     RECT  468.4 430.82 469.12 620.02 ;
     RECT  468.4 869.3 469.12 877.06 ;
     RECT  468.4 1118.78 469.12 1255.06 ;
     RECT  468.4 1504.34 469.12 1542.34 ;
     RECT  466.12 1791.62 469.12 1912.78 ;
     RECT  468.4 2162.06 469.12 2184.94 ;
     RECT  515.4 434.6 516.12 623.8 ;
     RECT  515.4 1122.56 516.12 1258.84 ;
     RECT  515.4 1500.56 516.12 1538.56 ;
     RECT  515.4 1787.84 516.12 1916.56 ;
     RECT  515.4 18.8 518.4 185.32 ;
     RECT  516.12 434.6 518.4 620.02 ;
     RECT  515.4 873.08 518.4 873.28 ;
     RECT  516.12 1122.56 518.4 1255.06 ;
     RECT  516.12 1504.34 518.4 1538.56 ;
     RECT  515.4 2165.84 518.4 2181.16 ;
     RECT  518.4 15.02 519.12 189.1 ;
     RECT  518.4 430.82 519.12 620.02 ;
     RECT  518.4 869.3 519.12 877.06 ;
     RECT  518.4 1118.78 519.12 1255.06 ;
     RECT  518.4 1504.34 519.12 1542.34 ;
     RECT  516.12 1791.62 519.12 1912.78 ;
     RECT  518.4 2162.06 519.12 2184.94 ;
     RECT  565.4 434.6 566.12 623.8 ;
     RECT  565.4 1122.56 566.12 1258.84 ;
     RECT  565.4 1500.56 566.12 1538.56 ;
     RECT  565.4 1787.84 566.12 1916.56 ;
     RECT  565.4 18.8 568.4 185.32 ;
     RECT  566.12 434.6 568.4 620.02 ;
     RECT  565.4 873.08 568.4 873.28 ;
     RECT  566.12 1122.56 568.4 1255.06 ;
     RECT  566.12 1504.34 568.4 1538.56 ;
     RECT  565.4 2165.84 568.4 2181.16 ;
     RECT  568.4 15.02 569.12 189.1 ;
     RECT  568.4 430.82 569.12 620.02 ;
     RECT  568.4 869.3 569.12 877.06 ;
     RECT  568.4 1118.78 569.12 1255.06 ;
     RECT  568.4 1504.34 569.12 1542.34 ;
     RECT  566.12 1791.62 569.12 1912.78 ;
     RECT  568.4 2162.06 569.12 2184.94 ;
     RECT  615.4 434.6 616.12 623.8 ;
     RECT  615.4 1122.56 616.12 1258.84 ;
     RECT  615.4 1500.56 616.12 1538.56 ;
     RECT  615.4 1787.84 616.12 1916.56 ;
     RECT  615.4 18.8 618.4 185.32 ;
     RECT  616.12 434.6 618.4 620.02 ;
     RECT  615.4 873.08 618.4 873.28 ;
     RECT  616.12 1122.56 618.4 1255.06 ;
     RECT  616.12 1504.34 618.4 1538.56 ;
     RECT  615.4 2165.84 618.4 2181.16 ;
     RECT  618.4 15.02 619.12 189.1 ;
     RECT  618.4 430.82 619.12 620.02 ;
     RECT  618.4 869.3 619.12 877.06 ;
     RECT  618.4 1118.78 619.12 1255.06 ;
     RECT  618.4 1504.34 619.12 1542.34 ;
     RECT  616.12 1791.62 619.12 1912.78 ;
     RECT  618.4 2162.06 619.12 2184.94 ;
     RECT  665.4 434.6 666.12 623.8 ;
     RECT  665.4 1122.56 666.12 1258.84 ;
     RECT  665.4 1500.56 666.12 1538.56 ;
     RECT  665.4 1787.84 666.12 1916.56 ;
     RECT  665.4 18.8 668.4 185.32 ;
     RECT  666.12 434.6 668.4 620.02 ;
     RECT  665.4 873.08 668.4 873.28 ;
     RECT  666.12 1122.56 668.4 1255.06 ;
     RECT  666.12 1504.34 668.4 1538.56 ;
     RECT  665.4 2165.84 668.4 2181.16 ;
     RECT  668.4 15.02 669.12 189.1 ;
     RECT  668.4 430.82 669.12 620.02 ;
     RECT  668.4 869.3 669.12 877.06 ;
     RECT  668.4 1118.78 669.12 1255.06 ;
     RECT  668.4 1504.34 669.12 1542.34 ;
     RECT  666.12 1791.62 669.12 1912.78 ;
     RECT  668.4 2162.06 669.12 2184.94 ;
     RECT  715.4 434.6 716.12 623.8 ;
     RECT  715.4 1122.56 716.12 1258.84 ;
     RECT  715.4 1500.56 716.12 1538.56 ;
     RECT  715.4 1787.84 716.12 1916.56 ;
     RECT  715.4 18.8 718.4 185.32 ;
     RECT  716.12 434.6 718.4 620.02 ;
     RECT  715.4 873.08 718.4 873.28 ;
     RECT  716.12 1122.56 718.4 1255.06 ;
     RECT  716.12 1504.34 718.4 1538.56 ;
     RECT  715.4 2165.84 718.4 2181.16 ;
     RECT  718.4 15.02 719.12 189.1 ;
     RECT  718.4 430.82 719.12 620.02 ;
     RECT  718.4 869.3 719.12 877.06 ;
     RECT  718.4 1118.78 719.12 1255.06 ;
     RECT  718.4 1504.34 719.12 1542.34 ;
     RECT  716.12 1791.62 719.12 1912.78 ;
     RECT  718.4 2162.06 719.12 2184.94 ;
     RECT  50 200 735.49 419.77 ;
     RECT  50 636 735.49 855.77 ;
     RECT  50 888 735.49 1107.77 ;
     RECT  50 1270 735.49 1489.77 ;
     RECT  50 1556 735.49 1775.77 ;
     RECT  50 1930 735.49 2149.77 ;
     RECT  765.4 18.8 768.4 2181.16 ;
     RECT  768.4 15.02 769.12 2184.94 ;
     RECT  815.4 18.8 818.4 2181.16 ;
     RECT  818.4 15.02 819.12 2184.94 ;
     RECT  865.4 18.8 868.4 2181.16 ;
     RECT  868.4 15.02 869.12 2184.94 ;
     RECT  915.4 18.8 918.4 2181.16 ;
     RECT  918.4 15.02 919.12 2184.94 ;
     RECT  965.4 18.8 966.12 472.6 ;
     RECT  965.4 714.32 966.12 888.4 ;
     RECT  965.4 1130.12 966.12 2181.16 ;
     RECT  966.12 18.8 968.4 468.82 ;
     RECT  966.12 1133.9 968.4 2181.16 ;
     RECT  968.4 15.02 969.12 468.82 ;
     RECT  966.12 718.1 969.12 884.62 ;
     RECT  968.4 1133.9 969.12 2184.94 ;
     RECT  1015.4 18.8 1016.12 79.48 ;
     RECT  1015.4 328.76 1016.12 472.6 ;
     RECT  1015.4 714.32 1016.12 888.4 ;
     RECT  1015.4 1130.12 1016.12 2181.16 ;
     RECT  1016.12 18.8 1018.4 75.7 ;
     RECT  1016.12 328.76 1018.4 468.82 ;
     RECT  1016.12 1133.9 1018.4 2181.16 ;
     RECT  1018.4 15.02 1019.12 75.7 ;
     RECT  1018.4 324.98 1019.12 468.82 ;
     RECT  1016.12 718.1 1019.12 884.62 ;
     RECT  1018.4 1133.9 1019.12 2184.94 ;
     RECT  1065.4 18.8 1066.12 79.48 ;
     RECT  1065.4 328.76 1066.12 472.6 ;
     RECT  1065.4 714.32 1066.12 888.4 ;
     RECT  1065.4 1130.12 1066.12 2181.16 ;
     RECT  1066.12 18.8 1068.4 75.7 ;
     RECT  1066.12 328.76 1068.4 468.82 ;
     RECT  1066.12 1133.9 1068.4 2181.16 ;
     RECT  1068.4 15.02 1069.12 75.7 ;
     RECT  1068.4 324.98 1069.12 468.82 ;
     RECT  1066.12 718.1 1069.12 884.62 ;
     RECT  1068.4 1133.9 1069.12 2184.94 ;
     RECT  1115.4 18.8 1116.12 79.48 ;
     RECT  1115.4 328.76 1116.12 472.6 ;
     RECT  1115.4 714.32 1116.12 888.4 ;
     RECT  1115.4 1130.12 1116.12 1462.96 ;
     RECT  1115.4 1712.24 1116.12 1735.12 ;
     RECT  1116.12 18.8 1118.4 75.7 ;
     RECT  1116.12 328.76 1118.4 468.82 ;
     RECT  1116.12 1133.9 1118.4 1462.96 ;
     RECT  1116.12 1716.02 1118.4 1735.12 ;
     RECT  1115.4 1984.4 1118.4 2181.16 ;
     RECT  1118.4 15.02 1119.12 75.7 ;
     RECT  1118.4 324.98 1119.12 468.82 ;
     RECT  1116.12 718.1 1119.12 884.62 ;
     RECT  1118.4 1133.9 1119.12 1466.74 ;
     RECT  1118.4 1716.02 1119.12 1738.9 ;
     RECT  1118.4 1980.62 1119.12 2184.94 ;
     RECT  1165.4 18.8 1166.12 79.48 ;
     RECT  1165.4 328.76 1166.12 472.6 ;
     RECT  1165.4 714.32 1166.12 888.4 ;
     RECT  1165.4 1130.12 1166.12 1462.96 ;
     RECT  1165.4 1712.24 1166.12 1735.12 ;
     RECT  1166.12 18.8 1168.4 75.7 ;
     RECT  1166.12 328.76 1168.4 468.82 ;
     RECT  1166.12 1133.9 1168.4 1462.96 ;
     RECT  1166.12 1716.02 1168.4 1735.12 ;
     RECT  1165.4 1984.4 1168.4 2181.16 ;
     RECT  1168.4 15.02 1169.12 75.7 ;
     RECT  1168.4 324.98 1169.12 468.82 ;
     RECT  1166.12 718.1 1169.12 884.62 ;
     RECT  1168.4 1133.9 1169.12 1466.74 ;
     RECT  1168.4 1716.02 1169.12 1738.9 ;
     RECT  1168.4 1980.62 1169.12 2184.94 ;
     RECT  1215.4 18.8 1216.12 79.48 ;
     RECT  1215.4 328.76 1216.12 472.6 ;
     RECT  1215.4 714.32 1216.12 888.4 ;
     RECT  1215.4 1130.12 1216.12 1462.96 ;
     RECT  1215.4 1712.24 1216.12 1735.12 ;
     RECT  1216.12 18.8 1218.4 75.7 ;
     RECT  1216.12 328.76 1218.4 468.82 ;
     RECT  1216.12 1133.9 1218.4 1462.96 ;
     RECT  1216.12 1716.02 1218.4 1735.12 ;
     RECT  1215.4 1984.4 1218.4 2181.16 ;
     RECT  1218.4 15.02 1219.12 75.7 ;
     RECT  1218.4 324.98 1219.12 468.82 ;
     RECT  1216.12 718.1 1219.12 884.62 ;
     RECT  1218.4 1133.9 1219.12 1466.74 ;
     RECT  1218.4 1716.02 1219.12 1738.9 ;
     RECT  1218.4 1980.62 1219.12 2184.94 ;
     RECT  1265.4 18.8 1266.12 79.48 ;
     RECT  1265.4 328.76 1266.12 472.6 ;
     RECT  1265.4 714.32 1266.12 888.4 ;
     RECT  1265.4 1130.12 1266.12 1462.96 ;
     RECT  1265.4 1712.24 1266.12 1735.12 ;
     RECT  1266.12 18.8 1268.4 75.7 ;
     RECT  1266.12 328.76 1268.4 468.82 ;
     RECT  1266.12 1133.9 1268.4 1462.96 ;
     RECT  1266.12 1716.02 1268.4 1735.12 ;
     RECT  1265.4 1984.4 1268.4 2181.16 ;
     RECT  1268.4 15.02 1269.12 75.7 ;
     RECT  1268.4 324.98 1269.12 468.82 ;
     RECT  1266.12 718.1 1269.12 884.62 ;
     RECT  1268.4 1133.9 1269.12 1466.74 ;
     RECT  1268.4 1716.02 1269.12 1738.9 ;
     RECT  1268.4 1980.62 1269.12 2184.94 ;
     RECT  1315.4 18.8 1316.12 79.48 ;
     RECT  1315.4 328.76 1316.12 472.6 ;
     RECT  1315.4 714.32 1316.12 888.4 ;
     RECT  1315.4 1130.12 1316.12 1462.96 ;
     RECT  1315.4 1712.24 1316.12 1735.12 ;
     RECT  1316.12 18.8 1318.4 75.7 ;
     RECT  1316.12 328.76 1318.4 468.82 ;
     RECT  1316.12 1133.9 1318.4 1462.96 ;
     RECT  1316.12 1716.02 1318.4 1735.12 ;
     RECT  1315.4 1984.4 1318.4 2181.16 ;
     RECT  1318.4 15.02 1319.12 75.7 ;
     RECT  1318.4 324.98 1319.12 468.82 ;
     RECT  1316.12 718.1 1319.12 884.62 ;
     RECT  1318.4 1133.9 1319.12 1466.74 ;
     RECT  1318.4 1716.02 1319.12 1738.9 ;
     RECT  1318.4 1980.62 1319.12 2184.94 ;
     RECT  1365.4 18.8 1366.12 79.48 ;
     RECT  1365.4 328.76 1366.12 472.6 ;
     RECT  1365.4 714.32 1366.12 888.4 ;
     RECT  1365.4 1130.12 1366.12 1462.96 ;
     RECT  1365.4 1712.24 1366.12 1735.12 ;
     RECT  1366.12 18.8 1368.4 75.7 ;
     RECT  1366.12 328.76 1368.4 468.82 ;
     RECT  1366.12 1133.9 1368.4 1462.96 ;
     RECT  1366.12 1716.02 1368.4 1735.12 ;
     RECT  1365.4 1984.4 1368.4 2181.16 ;
     RECT  1368.4 15.02 1369.12 75.7 ;
     RECT  1368.4 324.98 1369.12 468.82 ;
     RECT  1366.12 718.1 1369.12 884.62 ;
     RECT  1368.4 1133.9 1369.12 1466.74 ;
     RECT  1368.4 1716.02 1369.12 1738.9 ;
     RECT  1368.4 1980.62 1369.12 2184.94 ;
     RECT  1415.4 18.8 1416.12 79.48 ;
     RECT  1415.4 328.76 1416.12 472.6 ;
     RECT  1415.4 714.32 1416.12 888.4 ;
     RECT  1415.4 1130.12 1416.12 1462.96 ;
     RECT  1415.4 1712.24 1416.12 1735.12 ;
     RECT  1416.12 18.8 1418.4 75.7 ;
     RECT  1416.12 328.76 1418.4 468.82 ;
     RECT  1416.12 1133.9 1418.4 1462.96 ;
     RECT  1416.12 1716.02 1418.4 1735.12 ;
     RECT  1415.4 1984.4 1418.4 2181.16 ;
     RECT  1418.4 15.02 1419.12 75.7 ;
     RECT  1418.4 324.98 1419.12 468.82 ;
     RECT  1416.12 718.1 1419.12 884.62 ;
     RECT  1418.4 1133.9 1419.12 1466.74 ;
     RECT  1418.4 1716.02 1419.12 1738.9 ;
     RECT  1418.4 1980.62 1419.12 2184.94 ;
     RECT  1465.4 18.8 1466.12 79.48 ;
     RECT  1465.4 328.76 1466.12 472.6 ;
     RECT  1465.4 714.32 1466.12 888.4 ;
     RECT  1465.4 1130.12 1466.12 1462.96 ;
     RECT  1465.4 1712.24 1466.12 1735.12 ;
     RECT  1466.12 18.8 1468.4 75.7 ;
     RECT  1466.12 328.76 1468.4 468.82 ;
     RECT  1466.12 1133.9 1468.4 1462.96 ;
     RECT  1466.12 1716.02 1468.4 1735.12 ;
     RECT  1465.4 1984.4 1468.4 2181.16 ;
     RECT  1468.4 15.02 1469.12 75.7 ;
     RECT  1468.4 324.98 1469.12 468.82 ;
     RECT  1466.12 718.1 1469.12 884.62 ;
     RECT  1468.4 1133.9 1469.12 1466.74 ;
     RECT  1468.4 1716.02 1469.12 1738.9 ;
     RECT  1468.4 1980.62 1469.12 2184.94 ;
     RECT  1515.4 18.8 1516.12 79.48 ;
     RECT  1515.4 328.76 1516.12 472.6 ;
     RECT  1515.4 714.32 1516.12 888.4 ;
     RECT  1515.4 1130.12 1516.12 1462.96 ;
     RECT  1515.4 1712.24 1516.12 1735.12 ;
     RECT  1516.12 18.8 1518.4 75.7 ;
     RECT  1516.12 328.76 1518.4 468.82 ;
     RECT  1516.12 1133.9 1518.4 1462.96 ;
     RECT  1516.12 1716.02 1518.4 1735.12 ;
     RECT  1515.4 1984.4 1518.4 2181.16 ;
     RECT  1518.4 15.02 1519.12 75.7 ;
     RECT  1518.4 324.98 1519.12 468.82 ;
     RECT  1516.12 718.1 1519.12 884.62 ;
     RECT  1518.4 1133.9 1519.12 1466.74 ;
     RECT  1518.4 1716.02 1519.12 1738.9 ;
     RECT  1518.4 1980.62 1519.12 2184.94 ;
     RECT  1565.4 18.8 1566.12 79.48 ;
     RECT  1565.4 328.76 1566.12 472.6 ;
     RECT  1565.4 714.32 1566.12 888.4 ;
     RECT  1565.4 1130.12 1566.12 1462.96 ;
     RECT  1565.4 1712.24 1566.12 1735.12 ;
     RECT  1566.12 18.8 1568.4 75.7 ;
     RECT  1566.12 328.76 1568.4 468.82 ;
     RECT  1566.12 1133.9 1568.4 1462.96 ;
     RECT  1566.12 1716.02 1568.4 1735.12 ;
     RECT  1565.4 1984.4 1568.4 2181.16 ;
     RECT  1568.4 15.02 1569.12 75.7 ;
     RECT  1568.4 324.98 1569.12 468.82 ;
     RECT  1566.12 718.1 1569.12 884.62 ;
     RECT  1568.4 1133.9 1569.12 1466.74 ;
     RECT  1568.4 1716.02 1569.12 1738.9 ;
     RECT  1568.4 1980.62 1569.12 2184.94 ;
     RECT  1615.4 18.8 1616.12 79.48 ;
     RECT  1615.4 328.76 1616.12 472.6 ;
     RECT  1615.4 714.32 1616.12 888.4 ;
     RECT  1615.4 1130.12 1616.12 1462.96 ;
     RECT  1615.4 1712.24 1616.12 1735.12 ;
     RECT  1616.12 18.8 1618.4 75.7 ;
     RECT  1616.12 328.76 1618.4 468.82 ;
     RECT  1616.12 1133.9 1618.4 1462.96 ;
     RECT  1616.12 1716.02 1618.4 1735.12 ;
     RECT  1615.4 1984.4 1618.4 2181.16 ;
     RECT  1618.4 15.02 1619.12 75.7 ;
     RECT  1618.4 324.98 1619.12 468.82 ;
     RECT  1616.12 718.1 1619.12 884.62 ;
     RECT  1618.4 1133.9 1619.12 1466.74 ;
     RECT  1618.4 1716.02 1619.12 1738.9 ;
     RECT  1618.4 1980.62 1619.12 2184.94 ;
     RECT  950 484 1635.49 703.77 ;
     RECT  950 899.72 1635.49 1119.49 ;
     RECT  1665.4 18.8 1666.12 79.48 ;
     RECT  1665.4 1712.24 1666.12 1735.12 ;
     RECT  1666.12 18.8 1668.4 75.7 ;
     RECT  1665.4 328.76 1668.4 1462.96 ;
     RECT  1666.12 1716.02 1668.4 1735.12 ;
     RECT  1665.4 1984.4 1668.4 2181.16 ;
     RECT  1668.4 15.02 1669.12 75.7 ;
     RECT  1668.4 324.98 1669.12 1466.74 ;
     RECT  1668.4 1716.02 1669.12 1738.9 ;
     RECT  1668.4 1980.62 1669.12 2184.94 ;
     RECT  1000 92 1685.49 311.77 ;
     RECT  1715.4 1712.24 1716.12 1735.12 ;
     RECT  1715.4 18.8 1718.4 1462.96 ;
     RECT  1716.12 1716.02 1718.4 1735.12 ;
     RECT  1715.4 1984.4 1718.4 2181.16 ;
     RECT  1718.4 15.02 1719.12 1466.74 ;
     RECT  1718.4 1716.02 1719.12 1738.9 ;
     RECT  1718.4 1980.62 1719.12 2184.94 ;
     RECT  1765.4 1712.24 1766.12 1735.12 ;
     RECT  1765.4 18.8 1768.4 1462.96 ;
     RECT  1766.12 1716.02 1768.4 1735.12 ;
     RECT  1765.4 1984.4 1768.4 2181.16 ;
     RECT  1768.4 15.02 1769.12 1466.74 ;
     RECT  1768.4 1716.02 1769.12 1738.9 ;
     RECT  1768.4 1980.62 1769.12 2184.94 ;
     RECT  1100 1480 1785.49 1699.77 ;
     RECT  1125 1749.64 1810.49 1969.41 ;
     RECT  1815.4 18.8 1818.4 1735.12 ;
     RECT  1815.4 1984.4 1818.4 2181.16 ;
     RECT  1818.4 15.02 1819.12 1738.9 ;
     RECT  1818.4 1980.62 1819.12 2184.94 ;
     RECT  1865.4 18.8 1868.4 2181.16 ;
     RECT  1868.4 15.02 1869.12 2184.94 ;
    LAYER Metal4 ;
     RECT  1015.26 14.9 1019.26 81.52 ;
     RECT  1065.26 14.9 1069.26 81.52 ;
     RECT  1115.26 14.9 1119.26 81.52 ;
     RECT  1165.26 14.9 1169.26 81.52 ;
     RECT  1215.26 14.9 1219.26 81.52 ;
     RECT  1265.26 14.9 1269.26 81.52 ;
     RECT  1315.26 14.9 1319.26 81.52 ;
     RECT  1365.26 14.9 1369.26 81.52 ;
     RECT  1415.26 14.9 1419.26 81.52 ;
     RECT  1465.26 14.9 1469.26 81.52 ;
     RECT  1515.26 14.9 1519.26 81.52 ;
     RECT  1565.26 14.9 1569.26 81.52 ;
     RECT  1615.26 14.9 1619.26 81.52 ;
     RECT  1665.26 14.9 1669.26 81.52 ;
     RECT  1065.26 81.52 1066.26 81.76 ;
     RECT  1118.26 81.52 1119.26 81.76 ;
     RECT  1215.26 81.52 1216.26 81.76 ;
     RECT  1268.26 81.52 1269.26 81.76 ;
     RECT  1415.26 81.52 1416.26 81.76 ;
     RECT  1468.26 81.52 1469.26 81.76 ;
     RECT  1565.26 81.52 1566.26 81.76 ;
     RECT  1618.26 81.52 1619.26 81.76 ;
     RECT  65.26 14.9 69.26 189.52 ;
     RECT  115.26 14.9 119.26 189.52 ;
     RECT  165.26 14.9 169.26 189.52 ;
     RECT  215.26 14.9 219.26 189.52 ;
     RECT  265.26 14.9 269.26 189.52 ;
     RECT  315.26 14.9 319.26 189.52 ;
     RECT  365.26 14.9 369.26 189.52 ;
     RECT  415.26 14.9 419.26 189.52 ;
     RECT  465.26 14.9 469.26 189.52 ;
     RECT  515.26 14.9 519.26 189.52 ;
     RECT  565.26 14.9 569.26 189.52 ;
     RECT  615.26 14.9 619.26 189.52 ;
     RECT  665.26 14.9 669.26 189.52 ;
     RECT  715.26 14.9 719.26 189.52 ;
     RECT  115.26 189.52 116.26 189.76 ;
     RECT  168.26 189.52 169.26 189.76 ;
     RECT  265.26 189.52 266.26 189.76 ;
     RECT  318.26 189.52 319.26 189.76 ;
     RECT  465.26 189.52 466.26 189.76 ;
     RECT  518.26 189.52 519.26 189.76 ;
     RECT  615.26 189.52 616.26 189.76 ;
     RECT  668.26 189.52 669.26 189.76 ;
     RECT  1000 92 1685.49 311.77 ;
     RECT  1065.26 322.01 1066.26 322.25 ;
     RECT  1118.26 322.01 1119.26 322.25 ;
     RECT  1215.26 322.01 1216.26 322.25 ;
     RECT  1268.26 322.01 1269.26 322.25 ;
     RECT  1415.26 322.01 1416.26 322.25 ;
     RECT  1468.26 322.01 1469.26 322.25 ;
     RECT  1565.26 322.01 1566.26 322.25 ;
     RECT  1618.26 322.01 1619.26 322.25 ;
     RECT  50 200 735.49 419.77 ;
     RECT  115.26 430.01 116.26 430.12 ;
     RECT  265.26 430.01 266.26 430.12 ;
     RECT  465.26 430.01 466.26 430.12 ;
     RECT  615.26 430.01 616.26 430.12 ;
     RECT  68.26 430.12 69.26 430.25 ;
     RECT  168.26 430.01 169.26 430.25 ;
     RECT  218.26 430.12 219.26 430.25 ;
     RECT  318.26 430.01 319.26 430.25 ;
     RECT  368.26 430.12 369.26 430.25 ;
     RECT  418.26 430.12 419.26 430.25 ;
     RECT  518.26 430.01 519.26 430.25 ;
     RECT  568.26 430.12 569.26 430.25 ;
     RECT  668.26 430.01 669.26 430.25 ;
     RECT  718.26 430.12 719.26 430.25 ;
     RECT  965.26 14.9 969.26 473.52 ;
     RECT  1015.26 322.25 1019.26 473.52 ;
     RECT  1065.26 322.25 1069.26 473.52 ;
     RECT  1115.26 322.25 1119.26 473.52 ;
     RECT  1165.26 322.25 1169.26 473.52 ;
     RECT  1215.26 322.25 1219.26 473.52 ;
     RECT  1265.26 322.25 1269.26 473.52 ;
     RECT  1315.26 322.25 1319.26 473.52 ;
     RECT  1365.26 322.25 1369.26 473.52 ;
     RECT  1415.26 322.25 1419.26 473.52 ;
     RECT  1465.26 322.25 1469.26 473.52 ;
     RECT  1515.26 322.25 1519.26 473.52 ;
     RECT  1565.26 322.25 1569.26 473.52 ;
     RECT  1615.26 322.25 1619.26 473.52 ;
     RECT  1015.26 473.52 1016.26 473.76 ;
     RECT  1068.26 473.52 1069.26 473.76 ;
     RECT  1165.26 473.52 1166.26 473.76 ;
     RECT  1218.26 473.52 1219.26 473.76 ;
     RECT  1365.26 473.52 1366.26 473.76 ;
     RECT  1418.26 473.52 1419.26 473.76 ;
     RECT  1515.26 473.52 1516.26 473.76 ;
     RECT  1568.26 473.52 1569.26 473.76 ;
     RECT  65.26 430.25 69.26 625.52 ;
     RECT  115.26 430.12 119.26 625.52 ;
     RECT  165.26 430.25 169.26 625.52 ;
     RECT  215.26 430.25 219.26 625.52 ;
     RECT  265.26 430.12 269.26 625.52 ;
     RECT  315.26 430.25 319.26 625.52 ;
     RECT  365.26 430.25 369.26 625.52 ;
     RECT  415.26 430.25 419.26 625.52 ;
     RECT  465.26 430.12 469.26 625.52 ;
     RECT  515.26 430.25 519.26 625.52 ;
     RECT  565.26 430.25 569.26 625.52 ;
     RECT  615.26 430.12 619.26 625.52 ;
     RECT  665.26 430.25 669.26 625.52 ;
     RECT  715.26 430.25 719.26 625.52 ;
     RECT  115.26 625.52 116.26 625.76 ;
     RECT  168.26 625.52 169.26 625.76 ;
     RECT  265.26 625.52 266.26 625.76 ;
     RECT  318.26 625.52 319.26 625.76 ;
     RECT  465.26 625.52 466.26 625.76 ;
     RECT  518.26 625.52 519.26 625.76 ;
     RECT  615.26 625.52 616.26 625.76 ;
     RECT  668.26 625.52 669.26 625.76 ;
     RECT  950 484 1635.49 703.77 ;
     RECT  1068.26 714.01 1069.26 714.2 ;
     RECT  1218.26 714.01 1219.26 714.2 ;
     RECT  1418.26 714.01 1419.26 714.2 ;
     RECT  1568.26 714.01 1569.26 714.2 ;
     RECT  965.26 714.2 966.26 714.25 ;
     RECT  1015.26 714.01 1016.26 714.25 ;
     RECT  1115.26 714.2 1116.26 714.25 ;
     RECT  1165.26 714.01 1166.26 714.25 ;
     RECT  1265.26 714.2 1266.26 714.25 ;
     RECT  1315.26 714.2 1316.26 714.25 ;
     RECT  1365.26 714.01 1366.26 714.25 ;
     RECT  1465.26 714.2 1466.26 714.25 ;
     RECT  1515.26 714.01 1516.26 714.25 ;
     RECT  1615.26 714.2 1616.26 714.25 ;
     RECT  50 636 735.49 855.77 ;
     RECT  115.26 866.01 116.26 866.25 ;
     RECT  168.26 866.01 169.26 866.25 ;
     RECT  265.26 866.01 266.26 866.25 ;
     RECT  318.26 866.01 319.26 866.25 ;
     RECT  465.26 866.01 466.26 866.25 ;
     RECT  518.26 866.01 519.26 866.25 ;
     RECT  615.26 866.01 616.26 866.25 ;
     RECT  668.26 866.01 669.26 866.25 ;
     RECT  65.26 866.25 69.26 877.52 ;
     RECT  115.26 866.25 119.26 877.52 ;
     RECT  165.26 866.25 169.26 877.52 ;
     RECT  215.26 866.25 219.26 877.52 ;
     RECT  265.26 866.25 269.26 877.52 ;
     RECT  315.26 866.25 319.26 877.52 ;
     RECT  365.26 866.25 369.26 877.52 ;
     RECT  415.26 866.25 419.26 877.52 ;
     RECT  465.26 866.25 469.26 877.52 ;
     RECT  515.26 866.25 519.26 877.52 ;
     RECT  565.26 866.25 569.26 877.52 ;
     RECT  615.26 866.25 619.26 877.52 ;
     RECT  665.26 866.25 669.26 877.52 ;
     RECT  715.26 866.25 719.26 877.52 ;
     RECT  115.26 877.52 116.26 877.76 ;
     RECT  168.26 877.52 169.26 877.76 ;
     RECT  265.26 877.52 266.26 877.76 ;
     RECT  318.26 877.52 319.26 877.76 ;
     RECT  465.26 877.52 466.26 877.76 ;
     RECT  518.26 877.52 519.26 877.76 ;
     RECT  615.26 877.52 616.26 877.76 ;
     RECT  668.26 877.52 669.26 877.76 ;
     RECT  965.26 714.25 969.26 889.24 ;
     RECT  1015.26 714.25 1019.26 889.24 ;
     RECT  1065.26 714.2 1069.26 889.24 ;
     RECT  1115.26 714.25 1119.26 889.24 ;
     RECT  1165.26 714.25 1169.26 889.24 ;
     RECT  1215.26 714.2 1219.26 889.24 ;
     RECT  1265.26 714.25 1269.26 889.24 ;
     RECT  1315.26 714.25 1319.26 889.24 ;
     RECT  1365.26 714.25 1369.26 889.24 ;
     RECT  1415.26 714.2 1419.26 889.24 ;
     RECT  1465.26 714.25 1469.26 889.24 ;
     RECT  1515.26 714.25 1519.26 889.24 ;
     RECT  1565.26 714.2 1569.26 889.24 ;
     RECT  1615.26 714.25 1619.26 889.24 ;
     RECT  1015.26 889.24 1016.26 889.48 ;
     RECT  1068.26 889.24 1069.26 889.48 ;
     RECT  1165.26 889.24 1166.26 889.48 ;
     RECT  1218.26 889.24 1219.26 889.48 ;
     RECT  1365.26 889.24 1366.26 889.48 ;
     RECT  1418.26 889.24 1419.26 889.48 ;
     RECT  1515.26 889.24 1516.26 889.48 ;
     RECT  1568.26 889.24 1569.26 889.48 ;
     RECT  50 888 735.49 1107.77 ;
     RECT  115.26 1118.01 116.26 1118.25 ;
     RECT  168.26 1118.01 169.26 1118.25 ;
     RECT  265.26 1118.01 266.26 1118.25 ;
     RECT  318.26 1118.01 319.26 1118.25 ;
     RECT  465.26 1118.01 466.26 1118.25 ;
     RECT  518.26 1118.01 519.26 1118.25 ;
     RECT  615.26 1118.01 616.26 1118.25 ;
     RECT  668.26 1118.01 669.26 1118.25 ;
     RECT  950 899.72 1635.49 1119.49 ;
     RECT  1015.26 1129.73 1016.26 1129.97 ;
     RECT  1068.26 1129.73 1069.26 1129.97 ;
     RECT  1165.26 1129.73 1166.26 1129.97 ;
     RECT  1218.26 1129.73 1219.26 1129.97 ;
     RECT  1365.26 1129.73 1366.26 1129.97 ;
     RECT  1418.26 1129.73 1419.26 1129.97 ;
     RECT  1515.26 1129.73 1516.26 1129.97 ;
     RECT  1568.26 1129.73 1569.26 1129.97 ;
     RECT  65.26 1118.25 69.26 1259.52 ;
     RECT  115.26 1118.25 119.26 1259.52 ;
     RECT  165.26 1118.25 169.26 1259.52 ;
     RECT  215.26 1118.25 219.26 1259.52 ;
     RECT  265.26 1118.25 269.26 1259.52 ;
     RECT  315.26 1118.25 319.26 1259.52 ;
     RECT  365.26 1118.25 369.26 1259.52 ;
     RECT  415.26 1118.25 419.26 1259.52 ;
     RECT  465.26 1118.25 469.26 1259.52 ;
     RECT  515.26 1118.25 519.26 1259.52 ;
     RECT  565.26 1118.25 569.26 1259.52 ;
     RECT  615.26 1118.25 619.26 1259.52 ;
     RECT  665.26 1118.25 669.26 1259.52 ;
     RECT  715.26 1118.25 719.26 1259.52 ;
     RECT  115.26 1259.52 116.26 1259.76 ;
     RECT  168.26 1259.52 169.26 1259.76 ;
     RECT  265.26 1259.52 266.26 1259.76 ;
     RECT  318.26 1259.52 319.26 1259.76 ;
     RECT  465.26 1259.52 466.26 1259.76 ;
     RECT  518.26 1259.52 519.26 1259.76 ;
     RECT  615.26 1259.52 616.26 1259.76 ;
     RECT  668.26 1259.52 669.26 1259.76 ;
     RECT  1115.26 1129.97 1119.26 1469.52 ;
     RECT  1165.26 1129.97 1169.26 1469.52 ;
     RECT  1215.26 1129.97 1219.26 1469.52 ;
     RECT  1265.26 1129.97 1269.26 1469.52 ;
     RECT  1315.26 1129.97 1319.26 1469.52 ;
     RECT  1365.26 1129.97 1369.26 1469.52 ;
     RECT  1415.26 1129.97 1419.26 1469.52 ;
     RECT  1465.26 1129.97 1469.26 1469.52 ;
     RECT  1515.26 1129.97 1519.26 1469.52 ;
     RECT  1565.26 1129.97 1569.26 1469.52 ;
     RECT  1615.26 1129.97 1619.26 1469.52 ;
     RECT  1665.26 322.25 1669.26 1469.52 ;
     RECT  1715.26 14.9 1719.26 1469.52 ;
     RECT  1765.26 14.9 1769.26 1469.52 ;
     RECT  1165.26 1469.52 1166.26 1469.76 ;
     RECT  1218.26 1469.52 1219.26 1469.76 ;
     RECT  1315.26 1469.52 1316.26 1469.76 ;
     RECT  1368.26 1469.52 1369.26 1469.76 ;
     RECT  1515.26 1469.52 1516.26 1469.76 ;
     RECT  1568.26 1469.52 1569.26 1469.76 ;
     RECT  1665.26 1469.52 1666.26 1469.76 ;
     RECT  1718.26 1469.52 1719.26 1469.76 ;
     RECT  50 1270 735.49 1489.77 ;
     RECT  115.26 1500.01 116.26 1500.25 ;
     RECT  168.26 1500.01 169.26 1500.25 ;
     RECT  265.26 1500.01 266.26 1500.25 ;
     RECT  318.26 1500.01 319.26 1500.25 ;
     RECT  465.26 1500.01 466.26 1500.25 ;
     RECT  518.26 1500.01 519.26 1500.25 ;
     RECT  615.26 1500.01 616.26 1500.25 ;
     RECT  668.26 1500.01 669.26 1500.25 ;
     RECT  65.26 1500.25 69.26 1545.52 ;
     RECT  115.26 1500.25 119.26 1545.52 ;
     RECT  165.26 1500.25 169.26 1545.52 ;
     RECT  215.26 1500.25 219.26 1545.52 ;
     RECT  265.26 1500.25 269.26 1545.52 ;
     RECT  315.26 1500.25 319.26 1545.52 ;
     RECT  365.26 1500.25 369.26 1545.52 ;
     RECT  415.26 1500.25 419.26 1545.52 ;
     RECT  465.26 1500.25 469.26 1545.52 ;
     RECT  515.26 1500.25 519.26 1545.52 ;
     RECT  565.26 1500.25 569.26 1545.52 ;
     RECT  615.26 1500.25 619.26 1545.52 ;
     RECT  665.26 1500.25 669.26 1545.52 ;
     RECT  715.26 1500.25 719.26 1545.52 ;
     RECT  115.26 1545.52 116.26 1545.76 ;
     RECT  168.26 1545.52 169.26 1545.76 ;
     RECT  265.26 1545.52 266.26 1545.76 ;
     RECT  318.26 1545.52 319.26 1545.76 ;
     RECT  465.26 1545.52 466.26 1545.76 ;
     RECT  518.26 1545.52 519.26 1545.76 ;
     RECT  615.26 1545.52 616.26 1545.76 ;
     RECT  668.26 1545.52 669.26 1545.76 ;
     RECT  1100 1480 1785.49 1699.77 ;
     RECT  1165.26 1710.01 1166.26 1710.25 ;
     RECT  1218.26 1710.01 1219.26 1710.25 ;
     RECT  1315.26 1710.01 1316.26 1710.25 ;
     RECT  1368.26 1710.01 1369.26 1710.25 ;
     RECT  1515.26 1710.01 1516.26 1710.25 ;
     RECT  1568.26 1710.01 1569.26 1710.25 ;
     RECT  1665.26 1710.01 1666.26 1710.25 ;
     RECT  1718.26 1710.01 1719.26 1710.25 ;
     RECT  1165.26 1710.25 1169.26 1739.16 ;
     RECT  1215.26 1710.25 1219.26 1739.16 ;
     RECT  1265.26 1710.25 1269.26 1739.16 ;
     RECT  1315.26 1710.25 1319.26 1739.16 ;
     RECT  1365.26 1710.25 1369.26 1739.16 ;
     RECT  1465.26 1710.25 1469.26 1739.16 ;
     RECT  1565.26 1710.25 1569.26 1739.16 ;
     RECT  1615.26 1710.25 1619.26 1739.16 ;
     RECT  1665.26 1710.25 1669.26 1739.16 ;
     RECT  1715.26 1710.25 1719.26 1739.16 ;
     RECT  1765.26 1710.25 1769.26 1739.16 ;
     RECT  1115.26 1710.25 1119.26 1739.4 ;
     RECT  1315.26 1739.16 1316.26 1739.4 ;
     RECT  1368.26 1739.16 1369.26 1739.4 ;
     RECT  1415.26 1710.25 1419.26 1739.4 ;
     RECT  1515.26 1710.25 1519.26 1739.4 ;
     RECT  1568.26 1739.16 1569.26 1739.4 ;
     RECT  1665.26 1739.16 1666.26 1739.4 ;
     RECT  1718.26 1739.16 1719.26 1739.4 ;
     RECT  1815.26 14.9 1819.26 1739.4 ;
     RECT  50 1556 735.49 1775.77 ;
     RECT  115.26 1786.01 116.26 1786.25 ;
     RECT  168.26 1786.01 169.26 1786.25 ;
     RECT  265.26 1786.01 266.26 1786.25 ;
     RECT  318.26 1786.01 319.26 1786.25 ;
     RECT  465.26 1786.01 466.26 1786.25 ;
     RECT  518.26 1786.01 519.26 1786.25 ;
     RECT  615.26 1786.01 616.26 1786.25 ;
     RECT  668.26 1786.01 669.26 1786.25 ;
     RECT  65.26 1786.25 69.26 1919.52 ;
     RECT  115.26 1786.25 119.26 1919.52 ;
     RECT  165.26 1786.25 169.26 1919.52 ;
     RECT  215.26 1786.25 219.26 1919.52 ;
     RECT  265.26 1786.25 269.26 1919.52 ;
     RECT  315.26 1786.25 319.26 1919.52 ;
     RECT  365.26 1786.25 369.26 1919.52 ;
     RECT  415.26 1786.25 419.26 1919.52 ;
     RECT  465.26 1786.25 469.26 1919.52 ;
     RECT  515.26 1786.25 519.26 1919.52 ;
     RECT  565.26 1786.25 569.26 1919.52 ;
     RECT  615.26 1786.25 619.26 1919.52 ;
     RECT  665.26 1786.25 669.26 1919.52 ;
     RECT  715.26 1786.25 719.26 1919.52 ;
     RECT  115.26 1919.52 116.26 1919.76 ;
     RECT  168.26 1919.52 169.26 1919.76 ;
     RECT  265.26 1919.52 266.26 1919.76 ;
     RECT  318.26 1919.52 319.26 1919.76 ;
     RECT  465.26 1919.52 466.26 1919.76 ;
     RECT  518.26 1919.52 519.26 1919.76 ;
     RECT  615.26 1919.52 616.26 1919.76 ;
     RECT  668.26 1919.52 669.26 1919.76 ;
     RECT  1125 1749.64 1810.49 1969.41 ;
     RECT  1315.26 1979.65 1316.26 1979.89 ;
     RECT  1368.26 1979.65 1369.26 1979.89 ;
     RECT  1568.26 1979.65 1569.26 1979.89 ;
     RECT  1665.26 1979.65 1666.26 1979.89 ;
     RECT  1718.26 1979.65 1719.26 1979.89 ;
     RECT  50 1930 735.49 2149.77 ;
     RECT  115.26 2160.01 116.26 2160.25 ;
     RECT  168.26 2160.01 169.26 2160.25 ;
     RECT  265.26 2160.01 266.26 2160.25 ;
     RECT  318.26 2160.01 319.26 2160.25 ;
     RECT  465.26 2160.01 466.26 2160.25 ;
     RECT  518.26 2160.01 519.26 2160.25 ;
     RECT  615.26 2160.01 616.26 2160.25 ;
     RECT  668.26 2160.01 669.26 2160.25 ;
     RECT  15.26 14.9 19.26 2185.06 ;
     RECT  65.26 2160.25 69.26 2185.06 ;
     RECT  115.26 2160.25 119.26 2185.06 ;
     RECT  165.26 2160.25 169.26 2185.06 ;
     RECT  215.26 2160.25 219.26 2185.06 ;
     RECT  265.26 2160.25 269.26 2185.06 ;
     RECT  315.26 2160.25 319.26 2185.06 ;
     RECT  365.26 2160.25 369.26 2185.06 ;
     RECT  415.26 2160.25 419.26 2185.06 ;
     RECT  465.26 2160.25 469.26 2185.06 ;
     RECT  515.26 2160.25 519.26 2185.06 ;
     RECT  565.26 2160.25 569.26 2185.06 ;
     RECT  615.26 2160.25 619.26 2185.06 ;
     RECT  665.26 2160.25 669.26 2185.06 ;
     RECT  715.26 2160.25 719.26 2185.06 ;
     RECT  765.26 14.9 769.26 2185.06 ;
     RECT  815.26 14.9 819.26 2185.06 ;
     RECT  865.26 14.9 869.26 2185.06 ;
     RECT  915.26 14.9 919.26 2185.06 ;
     RECT  965.26 1129.97 969.26 2185.06 ;
     RECT  1015.26 1129.97 1019.26 2185.06 ;
     RECT  1065.26 1129.97 1069.26 2185.06 ;
     RECT  1115.26 1979.65 1119.26 2185.06 ;
     RECT  1165.26 1979.89 1169.26 2185.06 ;
     RECT  1215.26 1979.89 1219.26 2185.06 ;
     RECT  1265.26 1979.89 1269.26 2185.06 ;
     RECT  1315.26 1979.89 1319.26 2185.06 ;
     RECT  1365.26 1979.89 1369.26 2185.06 ;
     RECT  1415.26 1979.65 1419.26 2185.06 ;
     RECT  1465.26 1979.89 1469.26 2185.06 ;
     RECT  1515.26 1979.65 1519.26 2185.06 ;
     RECT  1565.26 1979.89 1569.26 2185.06 ;
     RECT  1615.26 1979.89 1619.26 2185.06 ;
     RECT  1665.26 1979.89 1669.26 2185.06 ;
     RECT  1715.26 1979.89 1719.26 2185.06 ;
     RECT  1765.26 1979.89 1769.26 2185.06 ;
     RECT  1815.26 1979.65 1819.26 2185.06 ;
     RECT  1865.26 14.9 1869.26 2185.06 ;
    LAYER TopMetal1 ;
     RECT  5.76 24.12 1894.08 2182.12 ;
  END
END ino_fetch
END LIBRARY
